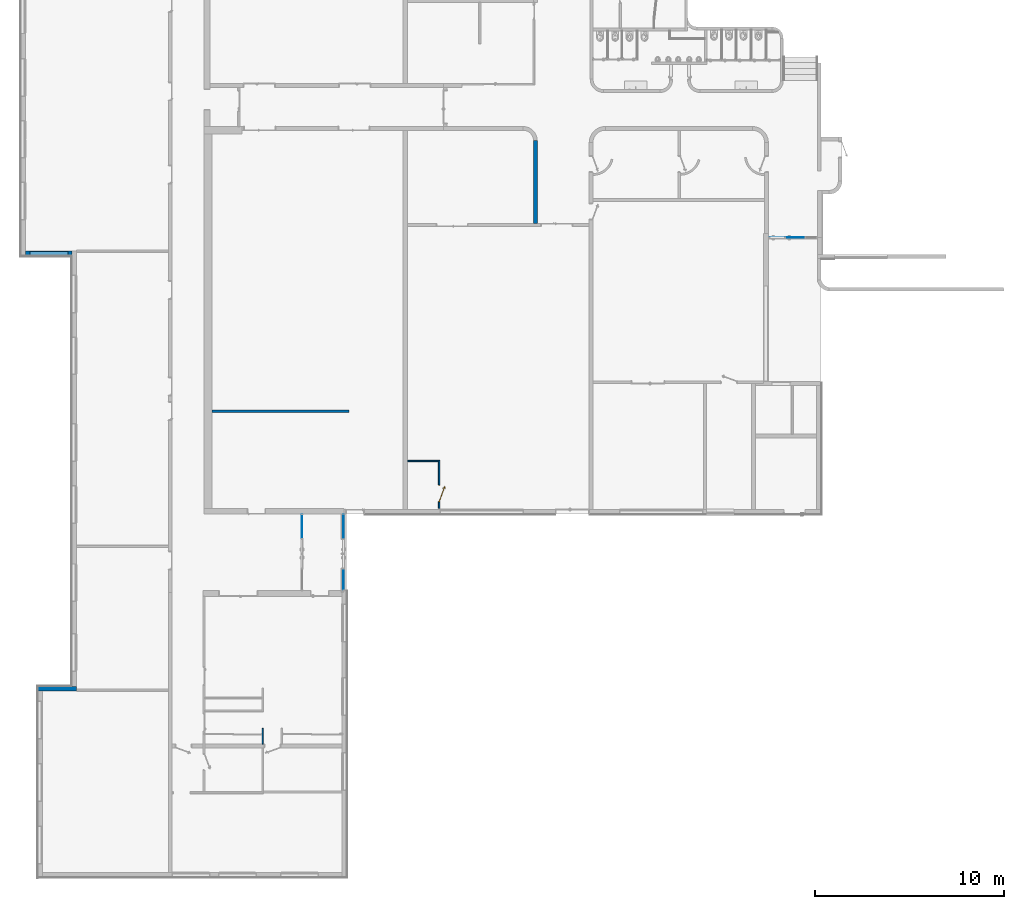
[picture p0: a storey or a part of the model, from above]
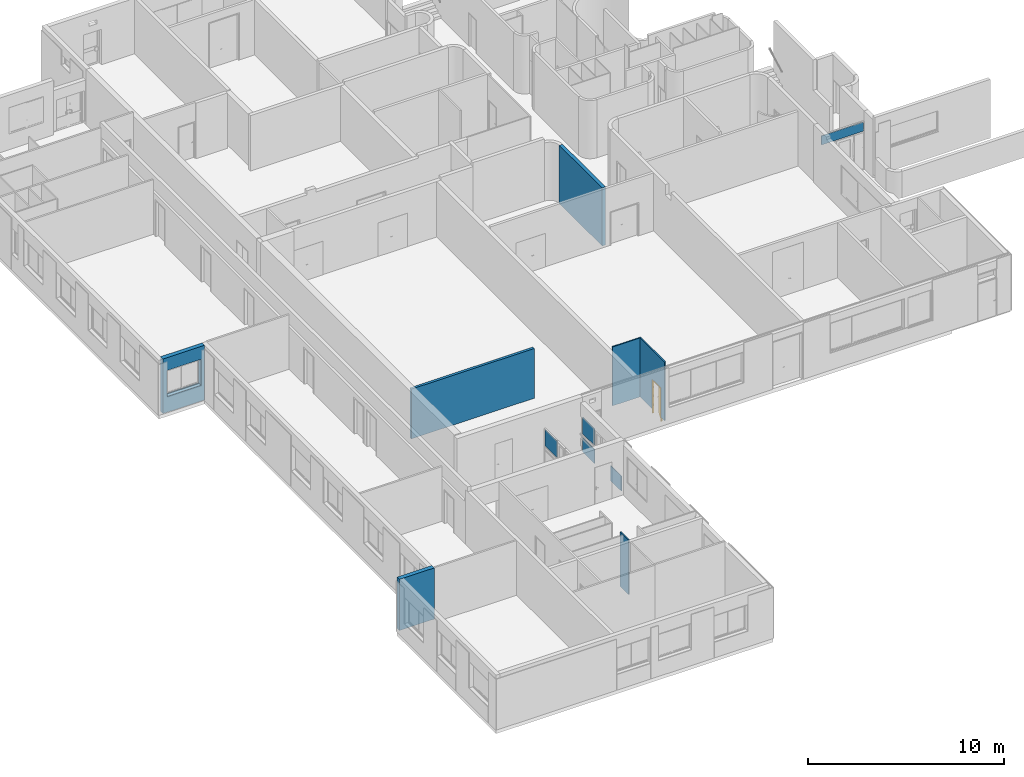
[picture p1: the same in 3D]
Properties of the parts of a building model (IFC2X3), part 1 of 4

# File
Description: ViewDefinition [CoordinationView_V2.0]
File name: 0001
Time: 2023-09-12T17:05:40
Written by: The EXPRESS Data Manager Version 5.02.0100.07 : 28 Aug 2013
Made in: 21.1.21.45 - Exporter 21.1.21.45 - Interface utilisateur alternative 21.1.21.45
Comment: STEP Physical File produced by: The EXPRESS Data Manager Version 5.02.0100.07 : 28 Aug 2013 * Module: EDMstepFileFactory/EDMstandAlone * Creation date: Tue Sep 12 17:05:40 2023 * Host: ws-vpa-259 * Database: C:\Users\ABDENO~1.BOU\AppData\Local\Temp\62183a18-c517-4f01-aa17-57c33f67edc7\9ac1ab08-a385-47ce-b0ed-35d248a44ec6\ifc * Database version: 5507 * Database creation date: Tue Sep 12 17:04:09 2023 * Schema: IFC2X3 * Model: DataRepository.ifc * Model creation date: Tue Sep 12 17:04:09 2023 * Header model: DataRepository.ifc_HeaderModel * Header model creation date: Tue Sep 12 17:04:09 2023 * EDMuser: sdai-user * EDMgroup: sdai-group * License ID and type: 5605 : Permanent license. Expiry date: * EDMstepFileFactory options: 020000

# IfcProject, 0001
LongName: SITE CEPRECO; Phase: Etat du projet

# IfcSite, Default
RefLatitude: 48, 51, 23, 999633; RefLongitude: 2, 21, 3, 553905; RefElevation: 35.0467 m

# IfcBuilding
Pset_BuildingCommon - NumberOfStoreys: 16

# IfcBuildingStorey: Niveau:Pointe 8 mm (16)
Name | LongName | Elevation (m)
SOUS SOL | SOUS SOL | -0.316692
Niveau 00 | Niveau 00 | 0
Niveau 00 - 01 | Niveau 00 - 01 | 0.253308
Niveau 00 - 02 | Niveau 00 - 02 | 0.893308
Niveau 00 - 03 | Niveau 00 - 03 | 2.31331
Niveau 1 - 03 | Niveau 1 - 03 | 3.22981
Niveau 1 - 01 | Niveau 1 - 01 | 3.95331
Niveau 1 | Niveau 1 | 4.12187
Niveau 1 - 02 | Niveau 1 - 02 | 4.31331
Niveau 1 - 03 | Niveau 1 - 03 | 5.77187
Niveau 2 | Niveau 2 | 7.36731
Niveau 3 - 02 | Niveau 3 - 02 | 9.74731
Niveau 3 - 01 | Niveau 3 - 01 | 10.1533
Niveau 3 | Niveau 3 | 10.7533
Niveau 4 | Niveau 4 | 13.0433
Niveau Toiture | Niveau Toiture | 14.9533

# IfcBeam: IPE 30:IPE300 (4)
In: Niveau 2
Type - Pset_BeamCommon - IsExternal: no; Reference: IPE300; LoadBearing: yes
Type - Pset_QuantityTakeOff - Reference: IPE300
Type - Pset_ReinforcementBarPitchOfBeam - Reference: IPE300
Material: Acier structurel - S235
Pset_BeamCommon - Slope: 0 deg
Pset_QuantityTakeOff - sets with these values: 2
Name (IPE 30:IPE300:...) | Span (m)
1296346 | 5.86
1296515 | 6.495
1296573 | 5.86
1481665 | 6.535

# IfcBeam: M_Béton-Poutre rectangulaire T2:20x60h (3)
In: Niveau 1 - 01
Type - Pset_BeamCommon - IsExternal: no; LoadBearing: yes; Reference: 20x60h
Type - Pset_QuantityTakeOff - Reference: 20x60h
Type - Pset_ReinforcementBarPitchOfBeam - Reference: 20x60h
Material: Béton, coulé sur place gris
Pset_BeamCommon - Slope: 0 deg
Pset_QuantityTakeOff - sets with these values: 2
Name (M_Béton-Poutre rectangulaire T2:20x60h:...) | Span (m)
1301493 | 29.0879
1301525 | 25.9214
1309314 | 25.9214

# IfcBeam: M_Béton-Poutre rectangulaire T2:20x65h (5)
In: Niveau 1 - 01
Type - Pset_BeamCommon - IsExternal: no; LoadBearing: yes; Reference: 20x65h
Type - Pset_QuantityTakeOff - Reference: 20x65h
Type - Pset_ReinforcementBarPitchOfBeam - Reference: 20x65h
Material: Béton, coulé sur place gris
Pset_BeamCommon - Slope: 0 deg
Pset_QuantityTakeOff - sets with these values: 2
Name (M_Béton-Poutre rectangulaire T2:20x65h:...) | Span (m)
1301378 | 29.0879
1309497 | 10.075
1309510 | 10.075
1506846 | 10.075
1506879 | 10.075

# IfcBeam: M_Béton-Poutre rectangulaire T2:30x65h, M_Béton-Poutre rectangulaire T2:30x65h:1506975
In: Niveau 1 - 01
Type - Pset_BeamCommon - IsExternal: no; LoadBearing: yes; Reference: 30x65h
Type - Pset_QuantityTakeOff - Reference: 30x65h
Type - Pset_ReinforcementBarPitchOfBeam - Reference: 30x65h
Material: Béton, coulé sur place gris
Pset_BeamCommon - Slope: 0 deg; Span: 10.075 m
Pset_QuantityTakeOff - sets with these values: 2

# IfcBeam: M_Béton-Poutre rectangulaire T2:40x90h, M_Béton-Poutre rectangulaire T2:40x90h:1398448
In: Niveau 2
Type - Pset_BeamCommon - IsExternal: no; LoadBearing: yes; Reference: 40x90h
Type - Pset_QuantityTakeOff - Reference: 40x90h
Type - Pset_ReinforcementBarPitchOfBeam - Reference: 40x90h
Material: Béton, coulé sur place gris
Pset_BeamCommon - Slope: 0 deg; Span: 9 m
Pset_QuantityTakeOff - sets with these values: 2

# IfcBeam: M_Béton-Poutre rectangulaire T2:55x65h, M_Béton-Poutre rectangulaire T2:55x65h:1502197
In: Niveau 00
Type - Pset_BeamCommon - IsExternal: no; LoadBearing: yes; Reference: 55x65h
Type - Pset_QuantityTakeOff - Reference: 55x65h
Type - Pset_ReinforcementBarPitchOfBeam - Reference: 55x65h
Material: Béton, coulé sur place gris
Pset_BeamCommon - Slope: 0 deg; Span: 29.0879 m
Pset_QuantityTakeOff - sets with these values: 2

# IfcBuildingElementProxy: Accrotère R+1:Accrotère R+1, Accrotère R+1:Accrotère R+1:1333942
In: Niveau 1 - 03
Type - Pset_BuildingElementProxyCommon - Reference: Accrotère R+1
Type - Pset_QuantityTakeOff - Reference: Accrotère R+1
Pset_BuildingElementProxyCommon - sets with these values: 2

# IfcBuildingElementProxy: BAC:BAC, BAC:BAC:1120224
In: Niveau 00 - 02
Type - Pset_BuildingElementProxyCommon - Reference: BAC
Type - Pset_QuantityTakeOff - Reference: BAC
Pset_BuildingElementProxyCommon - sets with these values: 2

# IfcBuildingElementProxy: Conduit Gaz1:Conduit Gaz, Conduit Gaz1:Conduit Gaz:1187289
In: Niveau 3
Type - Material: @_Peinture Gris Anthracite
Type - Pset_BuildingElementProxyCommon - Reference: Conduit Gaz
Type - Pset_QuantityTakeOff - Reference: Conduit Gaz
Pset_BuildingElementProxyCommon - sets with these values: 2
Pset_ProvisionForVoid - Width: 0.76389 m; Height: 0.308591 m; Depth: 0.76389 m

# IfcBuildingElementProxy: Conduit Gaz2:Conduit Gaz, Conduit Gaz2:Conduit Gaz:1188168
In: Niveau 3
Type - Material: @_Peinture Gris Anthracite
Type - Pset_BuildingElementProxyCommon - Reference: Conduit Gaz
Type - Pset_QuantityTakeOff - Reference: Conduit Gaz
Pset_BuildingElementProxyCommon - sets with these values: 2
Pset_ProvisionForVoid - Width: 0.76389 m; Height: 0.308591 m; Depth: 0.76389 m

# IfcBuildingElementProxy: Conduit Gaz3:Conduit Gaz, Conduit Gaz3:Conduit Gaz:1188640
In: Niveau 3
Type - Material: @_Peinture Gris Anthracite
Type - Pset_BuildingElementProxyCommon - Reference: Conduit Gaz
Type - Pset_QuantityTakeOff - Reference: Conduit Gaz
Pset_BuildingElementProxyCommon - sets with these values: 2

# IfcBuildingElementProxy: Conduit Gaz4:Conduit Gaz, Conduit Gaz4:Conduit Gaz:1189637
In: Niveau 3
Type - Material: @_Peinture Gris Anthracite
Type - Pset_BuildingElementProxyCommon - Reference: Conduit Gaz
Type - Pset_QuantityTakeOff - Reference: Conduit Gaz
Pset_BuildingElementProxyCommon - sets with these values: 2
Pset_ProvisionForVoid - Width: 0.506277 m; Height: 0.571712 m; Depth: 0.506277 m

# IfcBuildingElementProxy: Conduit Gaz5:Conduit Gaz, Conduit Gaz5:Conduit Gaz:1326465
In: Niveau 1 - 01
Type - Material: @_Peinture Gris Anthracite
Type - Pset_BuildingElementProxyCommon - Reference: Conduit Gaz
Type - Pset_QuantityTakeOff - Reference: Conduit Gaz
Pset_BuildingElementProxyCommon - sets with these values: 2
Pset_ProvisionForVoid - Width: 0.419194 m; Height: 0.55 m; Depth: 0.419194 m

# IfcBuildingElementProxy: Conduit Gaz6:Conduit Gaz, Conduit Gaz6:Conduit Gaz:1327238
In: Niveau 1
Type - Material: @_Peinture Gris Anthracite
Type - Pset_BuildingElementProxyCommon - Reference: Conduit Gaz
Type - Pset_QuantityTakeOff - Reference: Conduit Gaz
Pset_BuildingElementProxyCommon - sets with these values: 2
Pset_ProvisionForVoid - Width: 0.499194 m; Height: 0.55 m; Depth: 0.499194 m

# IfcBuildingElementProxy: Conduit Gaz:Conduit Gaz, Conduit Gaz:Conduit Gaz:1063076
In: Niveau 00
Type - Material: rouge
Type - Pset_BuildingElementProxyCommon - Reference: Conduit Gaz
Type - Pset_QuantityTakeOff - Reference: Conduit Gaz
Material: rouge, @_Peinture Gris Anthracite, Gaz jaune
Pset_BuildingElementProxyCommon - sets with these values: 2
Pset_ProvisionForVoid - Width: 11.1694 m; Height: 0.16 m; Depth: 11.1694 m

# IfcBuildingElementProxy: Famille 0:Famille 110x110 (3)
Type - Material: Métal - Aluminium, Verre
Type - Pset_BuildingElementProxyCommon - Reference: Famille 110x110
Type - Pset_QuantityTakeOff - Reference: Famille 110x110
Material: Verre, Métal - Aluminium
Pset_BuildingElementProxyCommon - sets with these values: 2
Name (Famille 0:Famille 110x110:...) | In
1185069 | Niveau 00 - 02
1326302 | Niveau 1 - 03
1326333 | Niveau 1 - 03

# IfcBuildingElementProxy: Famille 0:Famille 110x110 TYPE 2, Famille 0:Famille 110x110 TYPE 2:1201014
In: Niveau 00 - 02
Type - Material: Métal - Aluminium, Verre
Type - Pset_BuildingElementProxyCommon - Reference: Famille 110x110 TYPE 2
Type - Pset_QuantityTakeOff - Reference: Famille 110x110 TYPE 2
Material: Verre, Métal - Aluminium
Pset_BuildingElementProxyCommon - sets with these values: 2

# IfcBuildingElementProxy: Famille 0:Famille 120x120 (2)
In: Niveau 00 - 02
Type - Material: Métal - Aluminium, Verre
Type - Pset_BuildingElementProxyCommon - Reference: Famille 120x120
Type - Pset_QuantityTakeOff - Reference: Famille 120x120
Material: Verre, Métal - Aluminium
Pset_BuildingElementProxyCommon - sets with these values: 2
Name (Famille 0:Famille 120x120:...)
1168692
1168734

# IfcBuildingElementProxy: Famille 0:Famille 140x110, Famille 0:Famille 140x110:1310774
In: Niveau 1 - 01
Type - Material: Métal - Aluminium
Type - Pset_BuildingElementProxyCommon - Reference: Famille 140x110
Type - Pset_QuantityTakeOff - Reference: Famille 140x110
Material: Métal - Aluminium, Verre
Pset_BuildingElementProxyCommon - sets with these values: 2

# IfcBuildingElementProxy: Famille 0:Famille 140x110 (7)
Type - Material: Métal - Aluminium, Verre
Type - Pset_BuildingElementProxyCommon - Reference: Famille 140x110
Type - Pset_QuantityTakeOff - Reference: Famille 140x110
Material: Verre, Métal - Aluminium
Pset_BuildingElementProxyCommon - sets with these values: 2
Name (Famille 0:Famille 140x110:...) | In
1310134 | Niveau 1 - 03
1310135 | Niveau 1 - 03
1310775 | Niveau 1 - 01
1310776 | Niveau 1 - 01
1310777 | Niveau 1 - 01
1310778 | Niveau 1 - 01
1310779 | Niveau 1 - 01

# IfcBuildingElementProxy: Famille 0:Famille 150x120 (14)
Type - Material: Métal - Aluminium, Verre
Type - Pset_BuildingElementProxyCommon - Reference: Famille 150x120
Type - Pset_QuantityTakeOff - Reference: Famille 150x120
Material: Verre, Métal - Aluminium
Pset_BuildingElementProxyCommon - sets with these values: 2
Name (Famille 0:Famille 150x120:...) | In
1163506 | Niveau 00 - 02
1298098 | Niveau 00 - 02
1310329 | Niveau 1 - 01
1310574 | Niveau 1 - 01
1310575 | Niveau 1 - 01
1310576 | Niveau 1 - 01
1310577 | Niveau 1 - 01
1310578 | Niveau 1 - 01
1310588 | Niveau 1 - 01
1310761 | Niveau 1 - 01
1310762 | Niveau 1 - 01
1310763 | Niveau 1 - 01
1310764 | Niveau 1 - 01
1310765 | Niveau 1 - 01

# IfcBuildingElementProxy: Famille 0:Famille 85x55, Famille 0:Famille 85x55:1194350
In: Niveau 00 - 02
Type - Material: Métal - Aluminium, Verre
Type - Pset_BuildingElementProxyCommon - Reference: Famille 85x55
Type - Pset_QuantityTakeOff - Reference: Famille 85x55
Material: Verre, Métal - Aluminium
Pset_BuildingElementProxyCommon - sets with these values: 2

# IfcBuildingElementProxy: GAZ:#01, GAZ:#01:1062761
In: Niveau 00
Type - Material: rouge
Type - Pset_BuildingElementProxyCommon - Reference: #01
Type - Pset_QuantityTakeOff - Reference: #01
Pset_BuildingElementProxyCommon - sets with these values: 2

# IfcBuildingElementProxy: Grille d'aération - Mur:1000 x 820 mm, Grille d'aération - Mur:1000 x 820 mm:1200349
In: Niveau 3 - 02
Type - Material: Acier - Galvanisé (2)
Type - Pset_BuildingElementProxyCommon - Reference: 1000 x 820 mm
Type - Pset_QuantityTakeOff - Reference: 1000 x 820 mm
Material: Acier - Galvanisé
Pset_OpeningElementCommon - Reference: 1000 x 820 mm; sets with these values: 2

# IfcBuildingElementProxy: Grille d'aération - Mur:Type A (6)
Type - Material: Acier - Galvanisé (2)
Type - Pset_BuildingElementProxyCommon - Reference: Type A
Type - Pset_QuantityTakeOff - Reference: Type A
Material: Acier - Galvanisé
Name (Grille d'aération - Mur:Type A:...) | In | Reference | Pset_OpeningElementCommon, sets with these values
1138769 | Niveau 3 - 02 | Pset_BuildingElementProxyCommon - sets with these values: 2
1138918 | Niveau 3 - 02 | Type A | 2
1367621 | Niveau 00 | Type A | 2
1383589 | Niveau 00 - 03 | Type A | 2
1393028 | Niveau 00 - 03 | Type A | 2
1419079 | Niveau 00 - 03 | Type A | 2

# IfcBuildingElementProxy: Grille sol:Famille 2, Grille sol:Famille 2:1334444
In: Niveau 00 - 02
Type - Material: surface caillebotis
Type - Pset_BuildingElementProxyCommon - Reference: Famille 2
Type - Pset_QuantityTakeOff - Reference: Famille 2
Pset_BuildingElementProxyCommon - sets with these values: 2
Pset_ProvisionForVoid - Width: 0.025 m; Height: 0.4 m; Depth: 0.025 m

# IfcBuildingElementProxy: Grille sol:Famille1 (2)
In: Niveau 00 - 03
Type - Material: surface caillebotis
Type - Pset_BuildingElementProxyCommon - Reference: Famille1
Type - Pset_QuantityTakeOff - Reference: Famille1
Pset_BuildingElementProxyCommon - sets with these values: 2
Name (Grille sol:Famille1:...)
1186852 | Pset_ProvisionForVoid - Width: 0.025 m; Height: 1.25 m; Depth: 0.025 m
1186888

# IfcBuildingElementProxy: Modèles génériques 1:Modèles génériques 1, Modèles génériques 1:Modèles génériques 1:1211554
In: Niveau 3 - 01
Type - Pset_BuildingElementProxyCommon - Reference: Modèles génériques 1
Type - Pset_QuantityTakeOff - Reference: Modèles génériques 1
Pset_BuildingElementProxyCommon - sets with these values: 2
Pset_ProvisionForVoid - Width: 0.045 m; Height: 1.26264 m; Depth: 0.045 m

# IfcBuildingElementProxy: Modèles génériques 2:Modèles génériques 2, Modèles génériques 2:Modèles génériques 2:1303948
In: Niveau 00 - 03
Type - Pset_BuildingElementProxyCommon - Reference: Modèles génériques 2
Type - Pset_QuantityTakeOff - Reference: Modèles génériques 2
Pset_BuildingElementProxyCommon - sets with these values: 2
Pset_ProvisionForVoid - Width: 0.843308 m; Height: 1.215 m; Depth: 0.843308 m

# IfcBuildingElementProxy: Modèles génériques 3:Modèles génériques 3, Modèles génériques 3:Modèles génériques 3:1354350
In: Niveau 00 - 02
Type - Material: Maçonnerie - Voile BA rouge Brique
Type - Pset_BuildingElementProxyCommon - Reference: Modèles génériques 3
Type - Pset_QuantityTakeOff - Reference: Modèles génériques 3
Pset_BuildingElementProxyCommon - sets with these values: 2

# IfcBuildingElementProxy: Modèles génériques 4:Modèles génériques 4, Modèles génériques 4:Modèles génériques 4:1358634
In: Niveau 00 - 02
Type - Pset_BuildingElementProxyCommon - Reference: Modèles génériques 4
Type - Pset_QuantityTakeOff - Reference: Modèles génériques 4
Pset_BuildingElementProxyCommon - sets with these values: 2
Pset_ProvisionForVoid - Width: 0.89611 m; Height: 1.20011 m; Depth: 0.89611 m

# IfcBuildingElementProxy: Modèles génériques 5:Modèles génériques 5, Modèles génériques 5:Modèles génériques 5:1377466
In: Niveau 00 - 02
Type - Pset_BuildingElementProxyCommon - Reference: Modèles génériques 5
Type - Pset_QuantityTakeOff - Reference: Modèles génériques 5
Pset_BuildingElementProxyCommon - sets with these values: 2
Pset_ProvisionForVoid - Width: 0.160138 m; Height: 1.22 m; Depth: 0.160138 m

# IfcBuildingElementProxy: Modèles génériques 6:Modèles génériques 6, Modèles génériques 6:Modèles génériques 6:1497768
In: Niveau 00 - 02
Type - Pset_BuildingElementProxyCommon - Reference: Modèles génériques 6
Type - Pset_QuantityTakeOff - Reference: Modèles génériques 6
Pset_BuildingElementProxyCommon - sets with these values: 2
Pset_ProvisionForVoid - Width: 1.25 m; Height: 0.08 m; Depth: 1.25 m

# IfcBuildingElementProxy: Plan de travail:Plan de travail, Plan de travail:Plan de travail:1292339
In: Niveau 1
Type - Pset_BuildingElementProxyCommon - Reference: Plan de travail
Type - Pset_QuantityTakeOff - Reference: Plan de travail
Pset_BuildingElementProxyCommon - sets with these values: 2
Pset_ProvisionForVoid - Width: 0.874358 m; Height: 3.3175 m; Depth: 0.874358 m

# IfcBuildingElementProxy: Skydome 1:Skydome 110x120, Skydome 1:Skydome 110x120:1168822
In: Niveau 00 - 02
Type - Material: Verre, Métal - Bronze, Léger brossage
Type - Pset_BuildingElementProxyCommon - Reference: Skydome 110x120
Type - Pset_QuantityTakeOff - Reference: Skydome 110x120
Material: Métal - Bronze, Léger brossage, Verre
Pset_BuildingElementProxyCommon - sets with these values: 2

# IfcBuildingElementProxy: Skydome 3:Skydome 3, Skydome 3:Skydome 3:1171397
In: Niveau 00 - 02
Type - Material: Métal - Bronze, Léger brossage, Verre
Type - Pset_BuildingElementProxyCommon - Reference: Skydome 3
Type - Pset_QuantityTakeOff - Reference: Skydome 3
Material: Métal - Bronze, Léger brossage
Pset_BuildingElementProxyCommon - sets with these values: 2

# IfcBuildingElementProxy: Skydome 4:Skydome 110x110, Skydome 4:Skydome 110x110:1185118
In: Niveau 00 - 02
Type - Material: Métal - Bronze, Léger brossage, Verre
Type - Pset_BuildingElementProxyCommon - Reference: Skydome 110x110
Type - Pset_QuantityTakeOff - Reference: Skydome 110x110
Material: Verre
Pset_BuildingElementProxyCommon - sets with these values: 2

# IfcBuildingElementProxy: Skydome 4:Skydome 110x120, Skydome 4:Skydome 110x120:1178745
In: Niveau Toiture
Type - Material: Verre, Métal - Bronze, Léger brossage
Type - Pset_BuildingElementProxyCommon - Reference: Skydome 110x120
Type - Pset_QuantityTakeOff - Reference: Skydome 110x120
Material: Verre
Pset_BuildingElementProxyCommon - sets with these values: 2

# IfcBuildingElementProxy: Skydome 4:Skydome 110x120 (2)
In: Niveau 00 - 02
Type - Material: Verre, Métal - Bronze, Léger brossage, LIGNES
Type - Pset_BuildingElementProxyCommon - Reference: Skydome 110x120
Type - Pset_QuantityTakeOff - Reference: Skydome 110x120
Material: LIGNES, Verre
Pset_BuildingElementProxyCommon - sets with these values: 2
Name (Skydome 4:Skydome 110x120:...)
1184977
1185008

# IfcBuildingElementProxy: Tube de toiture1:Tube de toiture, Tube de toiture1:Tube de toiture:1176083
In: Niveau 1 - 03
Type - Material: @_Peinture Gris Anthracite
Type - Pset_BuildingElementProxyCommon - Reference: Tube de toiture
Type - Pset_QuantityTakeOff - Reference: Tube de toiture
Pset_BuildingElementProxyCommon - sets with these values: 2

# IfcBuildingElementProxy: Tube de toiture2:Tube de toiture, Tube de toiture2:Tube de toiture:1191322
In: Niveau 3
Type - Material: @_Peinture Gris Anthracite
Type - Pset_BuildingElementProxyCommon - Reference: Tube de toiture
Type - Pset_QuantityTakeOff - Reference: Tube de toiture
Pset_BuildingElementProxyCommon - sets with these values: 2

# IfcBuildingElementProxy: Tube de toiture3:Tube de toiture, Tube de toiture3:Tube de toiture:1312801
In: Niveau 1
Type - Material: @_Peinture Gris Anthracite
Type - Pset_BuildingElementProxyCommon - Reference: Tube de toiture
Type - Pset_QuantityTakeOff - Reference: Tube de toiture
Pset_BuildingElementProxyCommon - sets with these values: 2

# IfcBuildingElementProxy: Tube de toiture:Tube de toiture, Tube de toiture:Tube de toiture:1136618
In: Niveau 4
Type - Material: @_Peinture Gris Anthracite
Type - Pset_BuildingElementProxyCommon - Reference: Tube de toiture
Type - Pset_QuantityTakeOff - Reference: Tube de toiture
Pset_BuildingElementProxyCommon - sets with these values: 2

# IfcBuildingElementProxy: accortère1:accortère, accortère1:accortère:1152871
In: Niveau 3
Type - Pset_BuildingElementProxyCommon - Reference: accortère
Type - Pset_QuantityTakeOff - Reference: accortère
Pset_BuildingElementProxyCommon - sets with these values: 2

# IfcBuildingElementProxy: accortère2:accortère, accortère2:accortère:1436307
In: Niveau 1 - 03
Type - Pset_BuildingElementProxyCommon - Reference: accortère
Type - Pset_QuantityTakeOff - Reference: accortère
Pset_BuildingElementProxyCommon - sets with these values: 2

# IfcBuildingElementProxy: accortère3:accortère, accortère3:accortère:1436549
In: Niveau 1 - 03
Type - Pset_BuildingElementProxyCommon - Reference: accortère
Type - Pset_QuantityTakeOff - Reference: accortère
Pset_BuildingElementProxyCommon - sets with these values: 2

# IfcBuildingElementProxy: accortère4:accortère, accortère4:accortère:1436791
In: Niveau 00 - 03
Type - Pset_BuildingElementProxyCommon - Reference: accortère
Type - Pset_QuantityTakeOff - Reference: accortère
Pset_BuildingElementProxyCommon - sets with these values: 2

# IfcBuildingElementProxy: accortère5:accortère, accortère5:accortère:1437154
In: Niveau 3 - 02
Type - Pset_BuildingElementProxyCommon - Reference: accortère
Type - Pset_QuantityTakeOff - Reference: accortère
Pset_BuildingElementProxyCommon - sets with these values: 2

# IfcBuildingElementProxy: accortère6:accortère, accortère6:accortère:1437329
In: Niveau 00 - 03
Type - Pset_BuildingElementProxyCommon - Reference: accortère
Type - Pset_QuantityTakeOff - Reference: accortère
Pset_BuildingElementProxyCommon - sets with these values: 2

# IfcBuildingElementProxy: accortère:accortère, accortère:accortère:980411
In: Niveau 4
Type - Pset_BuildingElementProxyCommon - Reference: accortère
Type - Pset_QuantityTakeOff - Reference: accortère
Pset_BuildingElementProxyCommon - sets with these values: 2

# IfcCovering: Plafond composé:Normal (20)
Type - PredefinedType: CEILING
Type - Pset_CoveringCommon - Reference: Normal; TotalThickness: 0.05 m
Type - Pset_QuantityTakeOff - Reference: Normal
Material: Montant métallique 0.04 m, Faux-plafond - Trame 600 x 600 -90 0.01 m
Pset_CoveringCommon - Finish: Faux-plafond - Trame 600 x 600 -90;
Name (Plafond composé:Normal:...) | In
1043636 | Niveau 00 - 03
1047342 | Niveau 00 - 03
1047447 | Niveau 00
1047878 | Niveau 00
1124583 | Niveau 3
1255899 | Niveau 1
1302928 | Niveau 00
1314552 | Niveau 00
1315372 | Niveau 00
1335122 | Niveau 00
1398915 | Niveau 00
1403133 | Niveau 00
1407076 | Niveau 00
1500427 | Niveau 00
1501346 | Niveau 00
1501489 | Niveau 00
1501652 | SOUS SOL
1502257 | Niveau 00
1504277 | SOUS SOL
1508162 | Niveau 00

# IfcCovering: Plafond composé:Normal FP Bleu, Plafond composé:Normal FP Bleu:1109035
In: Niveau 00
Type - PredefinedType: CEILING
Type - Pset_CoveringCommon - Reference: Normal FP Bleu; TotalThickness: 0.03 m
Type - Pset_QuantityTakeOff - Reference: Normal FP Bleu
Material: FP - Peinture Grise 0.02 m, FP - Peinture bleu 0.01 m
Pset_CoveringCommon - Finish: FP - Peinture bleu;

# IfcCovering: Plafond composé:Normal FP bois, Plafond composé:Normal FP bois:1043869
In: Niveau 00 - 03
Type - PredefinedType: CEILING
Type - Pset_CoveringCommon - Reference: Normal FP bois; TotalThickness: 0.05 m
Type - Pset_QuantityTakeOff - Reference: Normal FP bois
Material: Montant métallique 0.04 m, Faux-plafond - bande bois 0.01 m
Pset_CoveringCommon - Finish: Faux-plafond - bande bois;

# IfcCurtainWall: Mur-rideau:SANS Calpinage (5)
Type - Pset_CurtainWallCommon - IsExternal: no; Reference: SANS Calpinage
Type - Pset_QuantityTakeOff - Reference: SANS Calpinage
Name (Mur-rideau:SANS Calpinage:...) | In
1121815 | Niveau 00 - 02
1361501 | Niveau 00 - 02 | Pset_OpeningElementCommon - Reference: SANS Calpinage; sets with these values: 2
1368376 | Niveau 00 - 01
1374202 | Niveau 00 - 01 | Pset_OpeningElementCommon - Reference: SANS Calpinage; sets with these values: 2
1528180 | Niveau 00 - 01

# IfcDistributionPort (2)
Description: Flow; FlowDirection: SINK
Name
Port_1289371
Port_1294219

# IfcDoor: @_Int. Simple:@_PP (0.63m x 2.04m) (3)
In: Niveau 00 - 01
Type - ParameterTakesPrecedence: no; Sizeable: no; Material: @_Finition Peinture - Blanc satiné, RAL1013-Blanc perle (3)
Type - Pset_DoorCommon - IsExternal: no; Reference: @_PP (0.63m x 2.04m)
Type - Pset_QuantityTakeOff - Reference: @_PP (0.63m x 2.04m)
OverallHeight: 2.075 m; OverallWidth: 0.7 m; Material: @_Finition Peinture - Blanc satiné, RAL1013-Blanc perle
Name (@_Int. Simple:@_PP (0.63m x 2.04m):...)
1404769
1404851
1404919

# IfcDoor: @_Int. Simple:@_PP (0.63m x 2.04m) (25)
Type - ParameterTakesPrecedence: no; Sizeable: no; Material: RAL1013-Blanc perle (3), @_Finition Peinture - Blanc satiné
Type - Pset_DoorCommon - IsExternal: no; Reference: @_PP (0.63m x 2.04m)
Type - Pset_QuantityTakeOff - Reference: @_PP (0.63m x 2.04m)
OverallHeight: 2.075 m; OverallWidth: 0.7 m; Material: @_Finition Peinture - Blanc satiné, RAL1013-Blanc perle
Name (@_Int. Simple:@_PP (0.63m x 2.04m):...) | In
1282573 | Niveau 1
1282698 | Niveau 1
1282734 | Niveau 1
1293008 | Niveau 2 | Pset_OpeningElementCommon - Reference: @_PP (0.63m x 2.04m); sets with these values: 2
1293082 | Niveau 2
1293188 | Niveau 2
1293949 | Niveau 1
1294012 | Niveau 1
1294067 | Niveau 1
1294088 | Niveau 1
1294376 | Niveau 2
1294378 | Niveau 2
1294380 | Niveau 2
1294382 | Niveau 2
1350456 | Niveau 00 - 02
1404965 | Niveau 00 - 01
1405068 | Niveau 00 - 01
1405116 | Niveau 00 - 01
1405150 | Niveau 00 - 01
1405199 | Niveau 00 - 01
1412120 | Niveau 00 - 01 | Pset_OpeningElementCommon - Reference: @_PP (0.63m x 2.04m); sets with these values: 2
1412158 | Niveau 00 - 01
1412204 | Niveau 00 - 01 | Pset_OpeningElementCommon - Reference: @_PP (0.63m x 2.04m); sets with these values: 2
1415135 | Niveau 00 - 01
1415207 | Niveau 00 - 01

# IfcDoor: @_Int. Simple:@_PP (0.73m x 2.04m) (14)
Type - ParameterTakesPrecedence: no; Sizeable: no; Material: @_Finition Peinture - Blanc satiné, RAL1013-Blanc perle (3)
Type - Pset_DoorCommon - IsExternal: no; Reference: @_PP (0.73m x 2.04m)
Type - Pset_QuantityTakeOff - Reference: @_PP (0.73m x 2.04m)
OverallHeight: 2.075 m; OverallWidth: 0.8 m; Material: @_Finition Peinture - Blanc satiné, RAL1013-Blanc perle
Name (@_Int. Simple:@_PP (0.73m x 2.04m):...) | In
1269008 | Niveau 1
1272663 | Niveau 1
1272706 | Niveau 1
1274033 | Niveau 1 | Pset_OpeningElementCommon - Reference: @_PP (0.73m x 2.04m); sets with these values: 2
1285083 | Niveau 1
1350262 | Niveau 00 - 02
1350312 | Niveau 00 - 02
1350398 | Niveau 00 - 02
1350508 | Niveau 00 - 02
1350536 | Niveau 00 - 02
1401739 | Niveau 00 - 01 | Pset_OpeningElementCommon - Reference: @_PP (0.73m x 2.04m); sets with these values: 2
1407251 | Niveau 00 - 01
1407285 | Niveau 00 - 01
1418454 | Niveau 00 - 02

# IfcDoor: @_Int. Simple:@_PP (0.73m x 2.04m) (13)
Type - ParameterTakesPrecedence: no; Sizeable: no; Material: RAL1013-Blanc perle (3), @_Finition Peinture - Blanc satiné
Type - Pset_DoorCommon - IsExternal: no; Reference: @_PP (0.73m x 2.04m)
Type - Pset_QuantityTakeOff - Reference: @_PP (0.73m x 2.04m)
OverallHeight: 2.075 m; OverallWidth: 0.8 m; Material: @_Finition Peinture - Blanc satiné, RAL1013-Blanc perle
Name (@_Int. Simple:@_PP (0.73m x 2.04m):...) | In
1095932 | SOUS SOL
1265753 | Niveau 1
1268579 | Niveau 1
1268599 | Niveau 1
1272618 | Niveau 1
1273967 | Niveau 1 | Pset_OpeningElementCommon - Reference: @_PP (0.73m x 2.04m); sets with these values: 2
1350556 | Niveau 00 - 02
1358109 | Niveau 00 - 02
1401716 | Niveau 00 - 01 | Pset_OpeningElementCommon - Reference: @_PP (0.73m x 2.04m); sets with these values: 2
1406095 | Niveau 00 - 01 | Pset_OpeningElementCommon - Reference: @_PP (0.73m x 2.04m); sets with these values: 2
1406932 | Niveau 00 - 01
1407017 | Niveau 00 - 01
1447539 | Niveau 1

# IfcDoor: @_Int. Simple:@_PP (0.83m x 2.04m) (4)
Type - ParameterTakesPrecedence: no; Sizeable: no; Material: @_Finition Peinture - Blanc satiné, RAL1013-Blanc perle (3)
Type - Pset_DoorCommon - IsExternal: no; Reference: @_PP (0.83m x 2.04m)
Type - Pset_QuantityTakeOff - Reference: @_PP (0.83m x 2.04m)
OverallHeight: 2.075 m; OverallWidth: 0.9 m; Material: @_Finition Peinture - Blanc satiné, RAL1013-Blanc perle
Name (@_Int. Simple:@_PP (0.83m x 2.04m):...) | In
1272736 | Niveau 1
1290945 | Niveau 1 | Pset_OpeningElementCommon - Reference: @_PP (0.83m x 2.04m); sets with these values: 2
1400419 | Niveau 00 - 02 | Pset_OpeningElementCommon - Reference: @_PP (0.83m x 2.04m); sets with these values: 2
1499070 | Niveau 00

# IfcDoor: @_Int. Simple:@_PP (0.83m x 2.04m) (19)
Type - ParameterTakesPrecedence: no; Sizeable: no; Material: RAL1013-Blanc perle (3), @_Finition Peinture - Blanc satiné
Type - Pset_DoorCommon - IsExternal: no; Reference: @_PP (0.83m x 2.04m)
Type - Pset_QuantityTakeOff - Reference: @_PP (0.83m x 2.04m)
OverallHeight: 2.075 m; OverallWidth: 0.9 m; Material: @_Finition Peinture - Blanc satiné, RAL1013-Blanc perle
Name (@_Int. Simple:@_PP (0.83m x 2.04m):...) | In
1225907 | Niveau 2 | Pset_OpeningElementCommon - Reference: @_PP (0.83m x 2.04m); sets with these values: 2
1225978 | Niveau 2
1228291 | Niveau 2
1272451 | Niveau 1
1273015 | Niveau 1
1292449 | Niveau 2
1397800 | Niveau 00 - 02
1401519 | Niveau 00 - 01
1406522 | Niveau 00 - 01
1408859 | Niveau 00 - 01
1409023 | Niveau 00 - 01
1410527 | Niveau 00 - 01
1411509 | Niveau 00 - 01
1414568 | Niveau 00 - 01
1414616 | Niveau 00 - 01
1487658 | Niveau 00
1518072 | Niveau 2
1522945 | Niveau 00
1535016 | Niveau 2

# IfcDoor: @_Int. Simple:@_PP (0.93m x 2.04m), @_Int. Simple:@_PP (0.93m x 2.04m):1490559
In: Niveau 00 - 02
Type - ParameterTakesPrecedence: no; Sizeable: no; Material: @_Finition Peinture - Blanc satiné, RAL1013-Blanc perle (3)
Type - Pset_DoorCommon - IsExternal: no; Reference: @_PP (0.93m x 2.04m)
Type - Pset_QuantityTakeOff - Reference: @_PP (0.93m x 2.04m)
OverallHeight: 2.075 m; OverallWidth: 1 m; Material: @_Finition Peinture - Blanc satiné, RAL1013-Blanc perle

# IfcDoor: @_Int. Simple:@_PP (0.93m x 2.04m) (11)
Type - ParameterTakesPrecedence: no; Sizeable: no; Material: RAL1013-Blanc perle (3), @_Finition Peinture - Blanc satiné
Type - Pset_DoorCommon - IsExternal: no; Reference: @_PP (0.93m x 2.04m)
Type - Pset_QuantityTakeOff - Reference: @_PP (0.93m x 2.04m)
OverallHeight: 2.075 m; OverallWidth: 1 m; Material: @_Finition Peinture - Blanc satiné, RAL1013-Blanc perle
Name (@_Int. Simple:@_PP (0.93m x 2.04m):...) | In
1100691 | SOUS SOL
1100895 | SOUS SOL
1211804 | Niveau 3 - 01
1232404 | Niveau 2
1265986 | Niveau 1 | Pset_OpeningElementCommon - Reference: @_PP (0.93m x 2.04m); sets with these values: 2
1266033 | Niveau 1
1272880 | Niveau 1
1291137 | Niveau 1
1291917 | Niveau 1
1400321 | Niveau 00 - 02
1410215 | Niveau 00 - 01

# IfcDoor: @_Int. Simple:@_PP (0.93m x 2.25), @_Int. Simple:@_PP (0.93m x 2.25):1415418
In: Niveau 00 - 01
Type - ParameterTakesPrecedence: no; Sizeable: no; Material: @_Finition Peinture - Blanc satiné, RAL1013-Blanc perle (3)
Type - Pset_DoorCommon - IsExternal: no; Reference: @_PP (0.93m x 2.25)
Type - Pset_QuantityTakeOff - Reference: @_PP (0.93m x 2.25)
OverallHeight: 2.265 m; OverallWidth: 1 m; Material: @_Finition Peinture - Blanc satiné, RAL1013-Blanc perle

# IfcDoor: @_Int. Simple:@_PP (0.93m x 2.25) (13)
In: Niveau 00 - 01
Type - ParameterTakesPrecedence: no; Sizeable: no; Material: RAL1013-Blanc perle (3), @_Finition Peinture - Blanc satiné
Type - Pset_DoorCommon - IsExternal: no; Reference: @_PP (0.93m x 2.25)
Type - Pset_QuantityTakeOff - Reference: @_PP (0.93m x 2.25)
OverallHeight: 2.265 m; OverallWidth: 1 m; Material: @_Finition Peinture - Blanc satiné, RAL1013-Blanc perle
Name (@_Int. Simple:@_PP (0.93m x 2.25):...)
1373748
1409657
1409742
1409800
1409892
1409947
1410001
1410127
1410189
1411536
1411562
1411926
1416117

# IfcDoor: @_Int. Simple:@_PP (1.03m x 1.8m), @_Int. Simple:@_PP (1.03m x 1.8m):1408319
In: Niveau 00 - 01
Type - ParameterTakesPrecedence: no; Sizeable: no; Material: RAL1013-Blanc perle (3), @_Finition Peinture - Blanc satiné
Type - Pset_DoorCommon - IsExternal: no; Reference: @_PP (1.03m x 1.8m)
Type - Pset_QuantityTakeOff - Reference: @_PP (1.03m x 1.8m)
OverallHeight: 1.835 m; OverallWidth: 1.1 m; Material: @_Finition Peinture - Blanc satiné, RAL1013-Blanc perle

# IfcDoor: @_Int. Simple:@_PP (1.03m x 2.30m), @_Int. Simple:@_PP (1.03m x 2.30m):1419078
In: Niveau 00 - 01
Type - ParameterTakesPrecedence: no; Sizeable: no; Material: RAL1013-Blanc perle (3), @_Finition Peinture - Blanc satiné
Type - Pset_DoorCommon - IsExternal: no; Reference: @_PP (1.03m x 2.30m)
Type - Pset_QuantityTakeOff - Reference: @_PP (1.03m x 2.30m)
OverallHeight: 2.335 m; OverallWidth: 1.1 m; Material: @_Finition Peinture - Blanc satiné, RAL1013-Blanc perle
Pset_OpeningElementCommon - Reference: @_PP (1.03m x 2.30m); sets with these values: 2

# IfcDoor: Double (R):1.23m x 2.04m, Double (R):1.23m x 2.04m:1094404
In: SOUS SOL
Type - OperationType: DOUBLE_DOOR_SINGLE_SWING; ParameterTakesPrecedence: no; Sizeable: no; Material: Porte - Panneau, Porte - Poignée, Porte - Cadre
Type - Double (R):1.23m x 2.04m:1094404 - PanelOperation: SWINGING
Type - Pset_DoorCommon - IsExternal: no; Reference: 1.23m x 2.04m; ThermalTransmittance: 3.7021 kg/K/s3
Type - Pset_QuantityTakeOff - Reference: 1.23m x 2.04m
OverallHeight: 2.075 m; OverallWidth: 1.3 m; Material: Porte - Poignée, Porte - Cadre, Porte - Panneau

# IfcDoor: Double (R):1.23m x 2.04m (2)
Type - OperationType: DOUBLE_DOOR_SINGLE_SWING; ParameterTakesPrecedence: no; Sizeable: no; Material: Porte - Poignée, Porte - Panneau, Porte - Cadre
Type - Double (R):1.23m x 2.04m:1094072 - PanelOperation: SWINGING
Type - Pset_DoorCommon - IsExternal: no; Reference: 1.23m x 2.04m; ThermalTransmittance: 3.7021 kg/K/s3
Type - Pset_QuantityTakeOff - Reference: 1.23m x 2.04m
OverallHeight: 2.075 m; OverallWidth: 1.3 m; Material: Porte - Poignée, Porte - Cadre, Porte - Panneau
Name (Double (R):1.23m x 2.04m:...) | In
1094072 | Niveau 00 - 02
1406318 | Niveau 00 - 01

# IfcDoor: Double (R):1.43m x 2.04m, Double (R):1.43m x 2.04m:1397711
In: Niveau 00 - 02
Type - OperationType: DOUBLE_DOOR_SINGLE_SWING; ParameterTakesPrecedence: no; Sizeable: no; Material: Porte - Cadre, Porte - Poignée, Porte - Panneau
Type - Double (R):1.43m x 2.04m:1397711 - PanelOperation: SWINGING
Type - Pset_DoorCommon - IsExternal: no; Reference: 1.43m x 2.04m; ThermalTransmittance: 3.7021 kg/K/s3
Type - Pset_QuantityTakeOff - Reference: 1.43m x 2.04m
OverallHeight: 2.075 m; OverallWidth: 1.5 m; Material: Porte - Poignée, Porte - Cadre, Porte - Panneau
Pset_OpeningElementCommon - Reference: 1.43m x 2.04m; sets with these values: 2

# IfcDoor: Double (R):1.43m x 2.04m (2)
In: Niveau 1
Type - OperationType: DOUBLE_DOOR_SINGLE_SWING; ParameterTakesPrecedence: no; Sizeable: no; Material: Porte - Panneau, Porte - Cadre, Porte - Poignée
Type - Double (R):1.43m x 2.04m:1269104 - PanelOperation: SWINGING
Type - Pset_DoorCommon - IsExternal: no; Reference: 1.43m x 2.04m; ThermalTransmittance: 3.7021 kg/K/s3
Type - Pset_QuantityTakeOff - Reference: 1.43m x 2.04m
OverallHeight: 2.075 m; OverallWidth: 1.5 m; Material: Porte - Poignée, Porte - Cadre, Porte - Panneau
Pset_OpeningElementCommon - Reference: 1.43m x 2.04m; sets with these values: 2
Name (Double (R):1.43m x 2.04m:...)
1269104
1269138

# IfcDoor: Double (R):1.43m x 2.04m (3)
Type - OperationType: DOUBLE_DOOR_SINGLE_SWING; ParameterTakesPrecedence: no; Sizeable: no; Material: Porte - Poignée, Porte - Panneau, Porte - Cadre
Type - Double (R):1.43m x 2.04m:1231099 - PanelOperation: SWINGING
Type - Pset_DoorCommon - IsExternal: no; Reference: 1.43m x 2.04m; ThermalTransmittance: 3.7021 kg/K/s3
Type - Pset_QuantityTakeOff - Reference: 1.43m x 2.04m
OverallHeight: 2.075 m; OverallWidth: 1.5 m; Material: Porte - Poignée, Porte - Cadre, Porte - Panneau
Name (Double (R):1.43m x 2.04m:...) | In
1231099 | Niveau 2
1231157 | Niveau 2
1409179 | Niveau 00 - 01

# IfcDoor: Double (R):1.43m x 2.04m, Double (R):1.43m x 2.04m:1265112
In: Niveau 1
Type - OperationType: DOUBLE_DOOR_SINGLE_SWING; ParameterTakesPrecedence: no; Sizeable: no; Material: Porte - Poignée, Porte - Panneau, Porte - Cadre
Type - Double (R):1.43m x 2.04m:1265112 - PanelOperation: SWINGING
Type - Pset_DoorCommon - IsExternal: no; Reference: 1.43m x 2.04m; ThermalTransmittance: 3.7021 kg/K/s3
Type - Pset_QuantityTakeOff - Reference: 1.43m x 2.04m
OverallHeight: 2.075 m; OverallWidth: 1.5 m; Material: Porte - Poignée, Porte - Cadre, Porte - Panneau

# IfcDoor: Double (R):1.63m x 2.04m, Double (R):1.63m x 2.04m:1397896
In: Niveau 00 - 02
Type - OperationType: DOUBLE_DOOR_SINGLE_SWING; ParameterTakesPrecedence: no; Sizeable: no; Material: Porte - Cadre, Porte - Panneau, Porte - Poignée
Type - Double (R):1.63m x 2.04m:1397896 - PanelOperation: SWINGING
Type - Pset_DoorCommon - IsExternal: no; Reference: 1.63m x 2.04m; ThermalTransmittance: 3.7021 kg/K/s3
Type - Pset_QuantityTakeOff - Reference: 1.63m x 2.04m
OverallHeight: 2.075 m; OverallWidth: 1.7 m; Material: Porte - Poignée, Porte - Cadre, Porte - Panneau

# IfcDoor: Double (R):1.63m x 2.04m (3)
Type - OperationType: DOUBLE_DOOR_SINGLE_SWING; ParameterTakesPrecedence: no; Sizeable: no; Material: Porte - Cadre, Porte - Panneau, Porte - Poignée
Type - Double (R):1.63m x 2.04m:1398069 - PanelOperation: SWINGING
Type - Pset_DoorCommon - IsExternal: no; Reference: 1.63m x 2.04m; ThermalTransmittance: 3.7021 kg/K/s3
Type - Pset_QuantityTakeOff - Reference: 1.63m x 2.04m
OverallHeight: 2.075 m; OverallWidth: 1.7 m; Material: Porte - Poignée, Porte - Cadre, Porte - Panneau
Name (Double (R):1.63m x 2.04m:...) | In
1398069 | Niveau 00 - 02
1408812 | Niveau 00 - 01
1414296 | Niveau 00 - 01

# IfcDoor: Double (R):1.63m x 2.04m (2)
In: Niveau 2
Type - OperationType: DOUBLE_DOOR_SINGLE_SWING; ParameterTakesPrecedence: no; Sizeable: no; Material: Porte - Panneau, Porte - Cadre, Porte - Poignée
Type - Double (R):1.63m x 2.04m:1226216 - PanelOperation: SWINGING
Type - Pset_DoorCommon - IsExternal: no; Reference: 1.63m x 2.04m; ThermalTransmittance: 3.7021 kg/K/s3
Type - Pset_QuantityTakeOff - Reference: 1.63m x 2.04m
OverallHeight: 2.075 m; OverallWidth: 1.7 m; Material: Porte - Poignée, Porte - Cadre, Porte - Panneau
Name (Double (R):1.63m x 2.04m:...)
1226216
1232490

# IfcDoor: Double (R):1.63m x 2.04m (2)
In: Niveau 1
Type - OperationType: DOUBLE_DOOR_SINGLE_SWING; ParameterTakesPrecedence: no; Sizeable: no; Material: Porte - Panneau, Porte - Cadre, Porte - Poignée
Type - Double (R):1.63m x 2.04m:1265850 - PanelOperation: SWINGING
Type - Pset_DoorCommon - IsExternal: no; Reference: 1.63m x 2.04m; ThermalTransmittance: 3.7021 kg/K/s3
Type - Pset_QuantityTakeOff - Reference: 1.63m x 2.04m
OverallHeight: 2.075 m; OverallWidth: 1.7 m; Material: Porte - Poignée, Porte - Cadre, Porte - Panneau
Name (Double (R):1.63m x 2.04m:...)
1265850
1273372

# IfcDoor: Double (R):1.63m x 2.04m, Double (R):1.63m x 2.04m:1408282
In: Niveau 00 - 01
Type - OperationType: DOUBLE_DOOR_SINGLE_SWING; ParameterTakesPrecedence: no; Sizeable: no; Material: Porte - Panneau, Porte - Cadre, Porte - Poignée
Type - Double (R):1.63m x 2.04m:1408282 - PanelOperation: SWINGING
Type - Pset_DoorCommon - IsExternal: no; Reference: 1.63m x 2.04m; ThermalTransmittance: 3.7021 kg/K/s3
Type - Pset_QuantityTakeOff - Reference: 1.63m x 2.04m
OverallHeight: 2.075 m; OverallWidth: 1.7 m; Material: Porte - Poignée, Porte - Cadre, Porte - Panneau

# IfcDoor: Double (R):1.63m x 2.04m (3)
Type - OperationType: DOUBLE_DOOR_SINGLE_SWING; ParameterTakesPrecedence: no; Sizeable: no; Material: Porte - Panneau, Porte - Poignée, Porte - Cadre
Type - Double (R):1.63m x 2.04m:1213401 - PanelOperation: SWINGING
Type - Pset_DoorCommon - IsExternal: no; Reference: 1.63m x 2.04m; ThermalTransmittance: 3.7021 kg/K/s3
Type - Pset_QuantityTakeOff - Reference: 1.63m x 2.04m
OverallHeight: 2.075 m; OverallWidth: 1.7 m; Material: Porte - Poignée, Porte - Cadre, Porte - Panneau
Name (Double (R):1.63m x 2.04m:...) | In
1213401 | Niveau 2
1232284 | Niveau 2
1275222 | Niveau 1

# IfcDoor: Double (R):1.63m x 2.04m, Double (R):1.63m x 2.04m:1397982
In: Niveau 00 - 02
Type - OperationType: DOUBLE_DOOR_SINGLE_SWING; ParameterTakesPrecedence: no; Sizeable: no; Material: Porte - Panneau, Porte - Poignée, Porte - Cadre
Type - Double (R):1.63m x 2.04m:1397982 - PanelOperation: SWINGING
Type - Pset_DoorCommon - IsExternal: no; Reference: 1.63m x 2.04m; ThermalTransmittance: 3.7021 kg/K/s3
Type - Pset_QuantityTakeOff - Reference: 1.63m x 2.04m
OverallHeight: 2.075 m; OverallWidth: 1.7 m; Material: Porte - Poignée, Porte - Cadre, Porte - Panneau

# IfcDoor: Double (R):1.63m x 2.04m, Double (R):1.63m x 2.04m:1281705
In: Niveau 1
Type - OperationType: DOUBLE_DOOR_SINGLE_SWING; ParameterTakesPrecedence: no; Sizeable: no; Material: Porte - Poignée, Porte - Cadre, Porte - Panneau
Type - Double (R):1.63m x 2.04m:1281705 - PanelOperation: SWINGING
Type - Pset_DoorCommon - IsExternal: no; Reference: 1.63m x 2.04m; ThermalTransmittance: 3.7021 kg/K/s3
Type - Pset_QuantityTakeOff - Reference: 1.63m x 2.04m
OverallHeight: 2.075 m; OverallWidth: 1.7 m

# IfcDoor: Double (R):1.63m x 2.04m (3)
In: Niveau 00 - 01
Type - OperationType: DOUBLE_DOOR_SINGLE_SWING; ParameterTakesPrecedence: no; Sizeable: no; Material: Porte - Poignée, Porte - Cadre, Porte - Panneau
Type - Double (R):1.63m x 2.04m:1408029 - PanelOperation: SWINGING
Type - Pset_DoorCommon - IsExternal: no; Reference: 1.63m x 2.04m; ThermalTransmittance: 3.7021 kg/K/s3
Type - Pset_QuantityTakeOff - Reference: 1.63m x 2.04m
OverallHeight: 2.075 m; OverallWidth: 1.7 m
Name (Double (R):1.63m x 2.04m:...)
1408029
1408130
1408237

# IfcDoor: Double (R):1.73m x 2.10m, Double (R):1.73m x 2.10m:1398163
In: Niveau 00 - 02
Type - OperationType: DOUBLE_DOOR_SINGLE_SWING; ParameterTakesPrecedence: no; Sizeable: no; Material: Porte - Cadre, Porte - Panneau, Porte - Poignée
Type - Double (R):1.73m x 2.10m:1398163 - PanelOperation: SWINGING
Type - Pset_DoorCommon - IsExternal: no; Reference: 1.73m x 2.10m; ThermalTransmittance: 3.7021 kg/K/s3
Type - Pset_QuantityTakeOff - Reference: 1.73m x 2.10m
OverallHeight: 2.135 m; OverallWidth: 1.8 m; Material: Porte - Poignée, Porte - Cadre, Porte - Panneau

# IfcDoor: Double (R):1.73m x 2.10m, Double (R):1.73m x 2.10m:1405736
In: Niveau 00 - 01
Type - OperationType: DOUBLE_DOOR_SINGLE_SWING; ParameterTakesPrecedence: no; Sizeable: no; Material: Porte - Cadre, Porte - Poignée, Porte - Panneau
Type - Double (R):1.73m x 2.10m:1405736 - PanelOperation: SWINGING
Type - Pset_DoorCommon - IsExternal: no; Reference: 1.73m x 2.10m; ThermalTransmittance: 3.7021 kg/K/s3
Type - Pset_QuantityTakeOff - Reference: 1.73m x 2.10m
OverallHeight: 2.135 m; OverallWidth: 1.8 m; Material: Porte - Poignée, Porte - Cadre, Porte - Panneau

# IfcDoor: Double (R):1.73m x 2.10m (2)
In: Niveau 00 - 01
Type - OperationType: DOUBLE_DOOR_SINGLE_SWING; ParameterTakesPrecedence: no; Sizeable: no; Material: Porte - Poignée, Porte - Cadre, Porte - Panneau
Type - Double (R):1.73m x 2.10m:1406038 - PanelOperation: SWINGING
Type - Pset_DoorCommon - IsExternal: no; Reference: 1.73m x 2.10m; ThermalTransmittance: 3.7021 kg/K/s3
Type - Pset_QuantityTakeOff - Reference: 1.73m x 2.10m
OverallHeight: 2.135 m; OverallWidth: 1.8 m
Pset_OpeningElementCommon - Reference: 1.73m x 2.10m; sets with these values: 2
Name (Double (R):1.73m x 2.10m:...)
1406038
1406223

# IfcDoor: Double (R):1.73m x 2.9m, Double (R):1.73m x 2.9m:1414511
In: Niveau 00 - 01
Type - OperationType: DOUBLE_DOOR_SINGLE_SWING; ParameterTakesPrecedence: no; Sizeable: no; Material: Porte - Cadre, Porte - Panneau, Porte - Poignée
Type - Double (R):1.73m x 2.9m:1414511 - PanelOperation: SWINGING
Type - Pset_DoorCommon - IsExternal: no; Reference: 1.73m x 2.9m; ThermalTransmittance: 3.7021 kg/K/s3
Type - Pset_QuantityTakeOff - Reference: 1.73m x 2.9m
OverallHeight: 2.935 m; OverallWidth: 1.8 m; Material: Porte - Poignée, Porte - Cadre, Porte - Panneau

# IfcDoor: Double (R):1.73m x 2.9m, Double (R):1.73m x 2.9m:1372745
In: Niveau 00 - 01
Type - OperationType: DOUBLE_DOOR_SINGLE_SWING; ParameterTakesPrecedence: no; Sizeable: no; Material: Porte - Cadre, Porte - Poignée, Porte - Panneau
Type - Double (R):1.73m x 2.9m:1372745 - PanelOperation: SWINGING
Type - Pset_DoorCommon - IsExternal: no; Reference: 1.73m x 2.9m; ThermalTransmittance: 3.7021 kg/K/s3
Type - Pset_QuantityTakeOff - Reference: 1.73m x 2.9m
OverallHeight: 2.935 m; OverallWidth: 1.8 m; Material: Porte - Poignée, Porte - Cadre, Porte - Panneau

# IfcDoor: Double (R):1.73m x 2.9m, Double (R):1.73m x 2.9m:1415340
In: Niveau 00 - 01
Type - OperationType: DOUBLE_DOOR_SINGLE_SWING; ParameterTakesPrecedence: no; Sizeable: no; Material: Porte - Panneau, Porte - Poignée, Porte - Cadre
Type - Double (R):1.73m x 2.9m:1415340 - PanelOperation: SWINGING
Type - Pset_DoorCommon - IsExternal: no; Reference: 1.73m x 2.9m; ThermalTransmittance: 3.7021 kg/K/s3
Type - Pset_QuantityTakeOff - Reference: 1.73m x 2.9m
OverallHeight: 2.935 m; OverallWidth: 1.8 m; Material: Porte - Poignée, Porte - Cadre, Porte - Panneau

# IfcDoor: Double (R):200m x 2.10m, Double (R):200m x 2.10m:1411594
In: Niveau 00 - 01
Type - OperationType: DOUBLE_DOOR_SINGLE_SWING; ParameterTakesPrecedence: no; Sizeable: no; Material: Porte - Cadre, Porte - Poignée, Porte - Panneau
Type - Double (R):200m x 2.10m:1411594 - PanelOperation: SWINGING
Type - Pset_DoorCommon - IsExternal: no; Reference: 200m x 2.10m; ThermalTransmittance: 3.7021 kg/K/s3
Type - Pset_QuantityTakeOff - Reference: 200m x 2.10m
OverallHeight: 2.135 m; OverallWidth: 2.07 m; Material: Porte - Poignée, Porte - Cadre, Porte - Panneau

# IfcDoor: Double Vitrée :1.63m x 2.04m, Double Vitrée :1.63m x 2.04m:1223007
In: Niveau 2
Type - OperationType: DOUBLE_DOOR_SINGLE_SWING; ParameterTakesPrecedence: no; Sizeable: no; Material: Porte - Poignée, Porte - Panneau, Porte - Cadre
Type - Double Vitrée :1.63m x 2.04m:1223007 - PanelOperation: SWINGING
Type - Pset_DoorCommon - IsExternal: no; Reference: 1.63m x 2.04m; ThermalTransmittance: 3.7021 kg/K/s3
Type - Pset_QuantityTakeOff - Reference: 1.63m x 2.04m
OverallHeight: 2.08 m; OverallWidth: 1.71 m; Material: Porte - Poignée, Porte - Cadre, Porte - Panneau, Verre

# IfcDoor: Ouverture en rectangle:Ouverture 85x210, Ouverture en rectangle:Ouverture 85x210:1272475
In: Niveau 1
Type - ParameterTakesPrecedence: no; Sizeable: no; Material: Bois - Chêne
Type - Pset_DoorCommon - IsExternal: no; Reference: Ouverture 85x210
Type - Pset_QuantityTakeOff - Reference: Ouverture 85x210
OverallHeight: 2.1 m; OverallWidth: 0.85 m

# IfcDoor: Ouverture en rectangle:Ouverture 90x210, Ouverture en rectangle:Ouverture 90x210:1523056
In: Niveau 00
Type - ParameterTakesPrecedence: no; Sizeable: no; Material: Bois - Chêne
Type - Pset_DoorCommon - IsExternal: no; Reference: Ouverture 90x210
Type - Pset_QuantityTakeOff - Reference: Ouverture 90x210
OverallHeight: 2.1 m; OverallWidth: 0.9 m

# IfcDoor: Ouverture en rectangle:Ouverture100x200 (8)
In: Niveau 2
Type - ParameterTakesPrecedence: no; Sizeable: no; Material: Bois - Chêne
Type - Pset_DoorCommon - IsExternal: no; Reference: Ouverture100x200
Type - Pset_QuantityTakeOff - Reference: Ouverture100x200
OverallHeight: 2 m; OverallWidth: 1 m
Name (Ouverture en rectangle:Ouverture100x200:...)
1215167
1221558
1228006
1228117
1230978
1230979
1231056 | Pset_OpeningElementCommon - Reference: Ouverture100x200; sets with these values: 2
1231057 | Pset_OpeningElementCommon - Reference: Ouverture100x200; sets with these values: 2

# IfcDoor: Ouverture en rectangle:Ouverture110x210, Ouverture en rectangle:Ouverture110x210:1408471
In: Niveau 00 - 01
Type - ParameterTakesPrecedence: no; Sizeable: no; Material: Bois - Chêne
Type - Pset_DoorCommon - IsExternal: no; Reference: Ouverture110x210
Type - Pset_QuantityTakeOff - Reference: Ouverture110x210
OverallHeight: 2.1 m; OverallWidth: 1.1 m

# IfcDoor: PRT-plaard coulissant:PRT_COL_207*100 (3)
In: Niveau 00
Type - ParameterTakesPrecedence: no; Sizeable: no; Material: <Unnamed> (4)
Type - Pset_DoorCommon - IsExternal: no; Reference: PRT_COL_207*100
Type - Pset_QuantityTakeOff - Reference: PRT_COL_207*100
OverallHeight: 2.075 m; OverallWidth: 3.05 m
Name (PRT-plaard coulissant:PRT_COL_207*100:...) | Reference | sets with these values
1523199 | PRT_COL_207*100 | 2
1527764 | PRT_COL_207*100 | 2
1527814

# IfcDoor: PVC Double - Panneaux vitrés haut:1.43m x 2.20m, PVC Double - Panneaux vitrés haut:1.43m x 2.20m:1047159
In: Niveau 00 - 02
Type - OperationType: DOUBLE_DOOR_SINGLE_SWING; ParameterTakesPrecedence: no; Sizeable: no; Material: PVC - Blanc (3)
Type - PVC Double - Panneaux vitrés haut:1.43m x 2.20m:1047159 - PanelOperation: SWINGING
Type - Pset_DoorCommon - IsExternal: no; Reference: 1.43m x 2.20m; ThermalTransmittance: 3.6886 kg/K/s3
Type - Pset_QuantityTakeOff - Reference: 1.43m x 2.20m
OverallHeight: 2.25 m; OverallWidth: 1.53 m; Material: PVC - Blanc, Verre

# IfcDoor: PVC Double - Panneaux vitrés haut:1.43m x 2.20m, PVC Double - Panneaux vitrés haut:1.43m x 2.20m:1062307
In: Niveau 00 - 01
Type - OperationType: DOUBLE_DOOR_SINGLE_SWING; ParameterTakesPrecedence: no; Sizeable: no; Material: PVC - Blanc (3)
Type - PVC Double - Panneaux vitrés haut:1.43m x 2.20m:1062307 - PanelOperation: SWINGING
Type - Pset_DoorCommon - IsExternal: no; Reference: 1.43m x 2.20m; ThermalTransmittance: 3.6886 kg/K/s3
Type - Pset_QuantityTakeOff - Reference: 1.43m x 2.20m
OverallHeight: 2.25 m; OverallWidth: 1.53 m; Material: PVC - Blanc, Verre
Pset_OpeningElementCommon - Reference: 1.43m x 2.20m; sets with these values: 2

# IfcDoor: PVC Double - Panneaux vitrés haut:1.63m x 2.10m, PVC Double - Panneaux vitrés haut:1.63m x 2.10m:1046917
In: Niveau 00 - 03
Type - OperationType: DOUBLE_DOOR_SINGLE_SWING; ParameterTakesPrecedence: no; Sizeable: no; Material: PVC - Blanc (3)
Type - PVC Double - Panneaux vitrés haut:1.63m x 2.10m:1046917 - PanelOperation: SWINGING
Type - Pset_DoorCommon - IsExternal: no; Reference: 1.63m x 2.10m; ThermalTransmittance: 3.6886 kg/K/s3
Type - Pset_QuantityTakeOff - Reference: 1.63m x 2.10m
OverallHeight: 2.15 m; OverallWidth: 1.73 m; Material: PVC - Blanc, Verre

# IfcDoor: PVC Double - Panneaux vitrés haut:1.63m x 2.10m, PVC Double - Panneaux vitrés haut:1.63m x 2.10m:1386985
In: Niveau 00 - 01
Type - OperationType: DOUBLE_DOOR_SINGLE_SWING; ParameterTakesPrecedence: no; Sizeable: no; Material: PVC - Blanc (3)
Type - PVC Double - Panneaux vitrés haut:1.63m x 2.10m:1386985 - PanelOperation: SWINGING
Type - Pset_DoorCommon - IsExternal: no; Reference: 1.63m x 2.10m; ThermalTransmittance: 3.6886 kg/K/s3
Type - Pset_QuantityTakeOff - Reference: 1.63m x 2.10m
OverallHeight: 2.15 m; OverallWidth: 1.73 m; Material: PVC - Blanc, Verre

# IfcDoor: PVC Double - Panneaux vitrés haut:2m x 2.20m (2)
In: Niveau 00 - 03
Type - OperationType: DOUBLE_DOOR_SINGLE_SWING; ParameterTakesPrecedence: no; Sizeable: no; Material: PVC - Blanc (3)
Type - PVC Double - Panneaux vitrés haut:2m x 2.20m:1043306 - PanelOperation: SWINGING
Type - Pset_DoorCommon - IsExternal: no; Reference: 2m x 2.20m; ThermalTransmittance: 3.6886 kg/K/s3
Type - Pset_QuantityTakeOff - Reference: 2m x 2.20m
OverallHeight: 2.25 m; OverallWidth: 2.1 m; Material: PVC - Blanc, Verre
Pset_OpeningElementCommon - Reference: 2m x 2.20m; sets with these values: 2
Name (PVC Double - Panneaux vitrés haut:2m x 2.20m:...)
1043306
1043378

# IfcDoor: PVC Double - Panneaux vitrés haut:2m x 2.5m, PVC Double - Panneaux vitrés haut:2m x 2.5m:1386681
In: Niveau 00 - 01
Type - OperationType: DOUBLE_DOOR_SINGLE_SWING; ParameterTakesPrecedence: no; Sizeable: no; Material: PVC - Blanc (3)
Type - PVC Double - Panneaux vitrés haut:2m x 2.5m:1386681 - PanelOperation: SWINGING
Type - Pset_DoorCommon - IsExternal: no; Reference: 2m x 2.5m; ThermalTransmittance: 3.6886 kg/K/s3
Type - Pset_QuantityTakeOff - Reference: 2m x 2.5m
OverallHeight: 2.55 m; OverallWidth: 2.1 m; Material: PVC - Blanc, Verre

# IfcDoor: PVC Panneau Vitré - Traverse:0.93m x 2.10m, PVC Panneau Vitré - Traverse:0.93m x 2.10m:1396995
In: Niveau 00 - 02
Type - OperationType: SINGLE_SWING_RIGHT; ParameterTakesPrecedence: no; Sizeable: no; Material: PVC - Blanc (3)
Type - PVC Panneau Vitré - Traverse:0.93m x 2.10m:1396995 - PanelOperation: SWINGING
Type - Pset_DoorCommon - IsExternal: no; Reference: 0.93m x 2.10m; ThermalTransmittance: 5.5617 kg/K/s3
Type - Pset_QuantityTakeOff - Reference: 0.93m x 2.10m
OverallHeight: 2.15 m; OverallWidth: 1.03 m; Material: PVC - Blanc, Verre
Pset_OpeningElementCommon - Reference: 0.93m x 2.10m; sets with these values: 2

# IfcDoor: PVC Panneau Vitré - Traverse:103m x 2.20m, PVC Panneau Vitré - Traverse:103m x 2.20m:1054507
In: Niveau 00 - 02
Type - OperationType: SINGLE_SWING_LEFT; ParameterTakesPrecedence: no; Sizeable: no; Material: PVC - Blanc (3)
Type - PVC Panneau Vitré - Traverse:103m x 2.20m:1054507 - PanelOperation: SWINGING
Type - Pset_DoorCommon - IsExternal: no; Reference: 103m x 2.20m; ThermalTransmittance: 5.5617 kg/K/s3
Type - Pset_QuantityTakeOff - Reference: 103m x 2.20m
OverallHeight: 2.25 m; OverallWidth: 1.13 m; Material: PVC - Blanc, Verre

# IfcDoor: PVC Panneau Vitré - Traverse:103m x 2.20m, PVC Panneau Vitré - Traverse:103m x 2.20m:1051442
In: Niveau 00 - 02
Type - OperationType: SINGLE_SWING_RIGHT; ParameterTakesPrecedence: no; Sizeable: no; Material: PVC - Blanc (3)
Type - PVC Panneau Vitré - Traverse:103m x 2.20m:1051442 - PanelOperation: SWINGING
Type - Pset_DoorCommon - IsExternal: no; Reference: 103m x 2.20m; ThermalTransmittance: 5.5617 kg/K/s3
Type - Pset_QuantityTakeOff - Reference: 103m x 2.20m
OverallHeight: 2.25 m; OverallWidth: 1.13 m; Material: PVC - Blanc, Verre

# IfcDoor: PVC Panneau Vitré - Traverse:103m x 2.20m, PVC Panneau Vitré - Traverse:103m x 2.20m:1393332
In: Niveau 00 - 01
Type - OperationType: SINGLE_SWING_RIGHT; ParameterTakesPrecedence: no; Sizeable: no; Material: PVC - Blanc (3)
Type - PVC Panneau Vitré - Traverse:103m x 2.20m:1393332 - PanelOperation: SWINGING
Type - Pset_DoorCommon - IsExternal: no; Reference: 103m x 2.20m; ThermalTransmittance: 5.5617 kg/K/s3
Type - Pset_QuantityTakeOff - Reference: 103m x 2.20m
OverallHeight: 2.25 m; OverallWidth: 1.13 m; Material: PVC - Blanc, Verre

# IfcDoor: Placard pliante:Placard pliante 100, Placard pliante:Placard pliante 100:1350602
In: Niveau 00 - 02
Type - OperationType: FOLDING_TO_RIGHT; ParameterTakesPrecedence: no; Sizeable: no; Material: Placard - Porte, Placard - Encadrement (2)
Type - Placard pliante:Placard pliante 100:1350602 - PanelOperation: FOLDING
Type - Pset_DoorCommon - IsExternal: no; Reference: Placard pliante 100; ThermalTransmittance: 3.7021 kg/K/s3
Type - Pset_QuantityTakeOff - Reference: Placard pliante 100
OverallHeight: 2.1 m; OverallWidth: 1 m; Material: Placard - Encadrement, Placard - Porte

# IfcDoor: Placard pliante:Placard pliante 110, Placard pliante:Placard pliante 110:1351901
In: Niveau 00 - 02
Type - OperationType: FOLDING_TO_RIGHT; ParameterTakesPrecedence: no; Sizeable: no; Material: Placard - Porte, Placard - Encadrement (2)
Type - Placard pliante:Placard pliante 110:1351901 - PanelOperation: FOLDING
Type - Pset_DoorCommon - IsExternal: no; Reference: Placard pliante 110; ThermalTransmittance: 3.7021 kg/K/s3
Type - Pset_QuantityTakeOff - Reference: Placard pliante 110
OverallHeight: 2.1 m; OverallWidth: 1.1 m; Material: Placard - Encadrement, Placard - Porte

# IfcDoor: Placard pliante:Placard pliante 42, Placard pliante:Placard pliante 42:1493985
In: Niveau 00
Type - OperationType: FOLDING_TO_RIGHT; ParameterTakesPrecedence: no; Sizeable: no; Material: Placard - Encadrement (2), Placard - Porte
Type - Placard pliante:Placard pliante 42:1493985 - PanelOperation: FOLDING
Type - Pset_DoorCommon - IsExternal: no; Reference: Placard pliante 42; ThermalTransmittance: 3.7021 kg/K/s3
Type - Pset_QuantityTakeOff - Reference: Placard pliante 42
OverallHeight: 2.1 m; OverallWidth: 0.42 m; Material: Placard - Encadrement, Placard - Porte

# IfcDoor: Porte métal:@_PP (1.03m x 1.8m), Porte métal:@_PP (1.03m x 1.8m):1200092
In: Niveau 3
Type - ParameterTakesPrecedence: no; Sizeable: no; Material: RAL1013-Blanc perle (3), @_Finition Peinture - Blanc satiné
Type - Pset_DoorCommon - IsExternal: no; Reference: @_PP (1.03m x 1.8m)
Type - Pset_QuantityTakeOff - Reference: @_PP (1.03m x 1.8m)
OverallHeight: 1.735 m; OverallWidth: 1.1 m; Material: @_Finition Peinture - Blanc satiné, RAL1013-Blanc perle

# IfcDoor: Simple vitrée:Simple vitrée (2)
In: Niveau 00 - 01
Type - OperationType: SINGLE_SWING_LEFT; ParameterTakesPrecedence: no; Sizeable: no; Material: Porte - Cadre, Porte - Panneau, Porte - Poignée
Type - Simple vitrée:Simple vitrée:1374857 - PanelOperation: SWINGING
Type - Pset_DoorCommon - IsExternal: no; Reference: Simple vitrée; ThermalTransmittance: 3.6886 kg/K/s3
Type - Pset_QuantityTakeOff - Reference: Simple vitrée
OverallHeight: 2.2105 m; OverallWidth: 0.745 m; Material: Porte - Poignée, Porte - Cadre, Verre, Porte - Panneau
Pset_DoorCommon - IsExternal: yes
Name (Simple vitrée:Simple vitrée:...)
1374857
1528203

# IfcDoor: Simple vitrée:Simple vitrée, Simple vitrée:Simple vitrée:1368383
In: Niveau 00 - 01
Type - OperationType: SINGLE_SWING_LEFT; ParameterTakesPrecedence: no; Sizeable: no; Material: Porte - Cadre, Porte - Poignée, Porte - Panneau
Type - Simple vitrée:Simple vitrée:1368383 - PanelOperation: SWINGING
Type - Pset_DoorCommon - IsExternal: no; Reference: Simple vitrée; ThermalTransmittance: 3.6886 kg/K/s3
Type - Pset_QuantityTakeOff - Reference: Simple vitrée
OverallHeight: 2.32833 m; OverallWidth: 1.01507 m; Material: Porte - Poignée, Porte - Cadre, Verre, Porte - Panneau
Pset_DoorCommon - IsExternal: yes

# IfcDoor: Simple vitrée:Simple vitrée, Simple vitrée:Simple vitrée:1368388
In: Niveau 00 - 01
Type - OperationType: SINGLE_SWING_LEFT; ParameterTakesPrecedence: no; Sizeable: no; Material: Porte - Panneau, Porte - Cadre, Porte - Poignée
Type - Simple vitrée:Simple vitrée:1368388 - PanelOperation: SWINGING
Type - Pset_DoorCommon - IsExternal: no; Reference: Simple vitrée; ThermalTransmittance: 3.6886 kg/K/s3
Type - Pset_QuantityTakeOff - Reference: Simple vitrée
OverallHeight: 2.32833 m; OverallWidth: 0.792097 m; Material: Porte - Poignée, Porte - Cadre, Verre, Porte - Panneau
Pset_DoorCommon - IsExternal: yes

# IfcDoor: Simple vitrée:Simple vitrée (2)
In: Niveau 00 - 02
Type - OperationType: SINGLE_SWING_RIGHT; ParameterTakesPrecedence: no; Sizeable: no; Material: Porte - Poignée, Porte - Cadre, Porte - Panneau
Type - Simple vitrée:Simple vitrée:1121981 - PanelOperation: SWINGING
Type - Pset_DoorCommon - IsExternal: no; Reference: Simple vitrée; ThermalTransmittance: 3.6886 kg/K/s3
Type - Pset_QuantityTakeOff - Reference: Simple vitrée
OverallHeight: 2.25 m; OverallWidth: 1.11586 m; Material: Porte - Poignée, Porte - Cadre, Verre, Porte - Panneau
Pset_DoorCommon - IsExternal: yes
Name (Simple vitrée:Simple vitrée:...)
1121981
1361508

# IfcDoor: Simple vitrée:Simple vitrée (2)
In: Niveau 00 - 01
Type - OperationType: SINGLE_SWING_RIGHT; ParameterTakesPrecedence: no; Sizeable: no; Material: Porte - Poignée, Porte - Cadre, Porte - Panneau
Type - Simple vitrée:Simple vitrée:1374209 - PanelOperation: SWINGING
Type - Pset_DoorCommon - IsExternal: no; Reference: Simple vitrée; ThermalTransmittance: 3.6886 kg/K/s3
Type - Pset_QuantityTakeOff - Reference: Simple vitrée
OverallHeight: 2.2105 m; OverallWidth: 0.74663 m; Material: Porte - Poignée, Porte - Cadre, Verre, Porte - Panneau
Pset_DoorCommon - IsExternal: yes
Name (Simple vitrée:Simple vitrée:...)
1374209
1528187

# IfcDoor: Tierce 160:1.10m x 2.04m (8)
Type - ParameterTakesPrecedence: no; Sizeable: no; Material: Porte - Cadre, Porte - Panneau (2), Porte - Poignée
Type - Pset_DoorCommon - IsExternal: no; Reference: 1.10m x 2.04m; ThermalTransmittance: 3.7021 kg/K/s3
Type - Pset_QuantityTakeOff - Reference: 1.10m x 2.04m
OverallHeight: 2.075 m; OverallWidth: 1.12 m; Material: Porte - Poignée, Porte - Cadre, Verre, Porte - Panneau
Name (Tierce 160:1.10m x 2.04m:...) | In
1213566 | Niveau 2
1231607 | Niveau 2
1232174 | Niveau 2
1232216 | Niveau 2 | Pset_OpeningElementCommon - Reference: 1.10m x 2.04m; sets with these values: 2
1232238 | Niveau 2
1232378 | Niveau 2
1233400 | Niveau 2
1275268 | Niveau 1

# IfcDoor: Tierce 160:1.10m x 2.04m (13)
Type - ParameterTakesPrecedence: no; Sizeable: no; Material: Porte - Panneau (2), Porte - Cadre, Porte - Poignée
Type - Pset_DoorCommon - IsExternal: no; Reference: 1.10m x 2.04m; ThermalTransmittance: 3.7021 kg/K/s3
Type - Pset_QuantityTakeOff - Reference: 1.10m x 2.04m
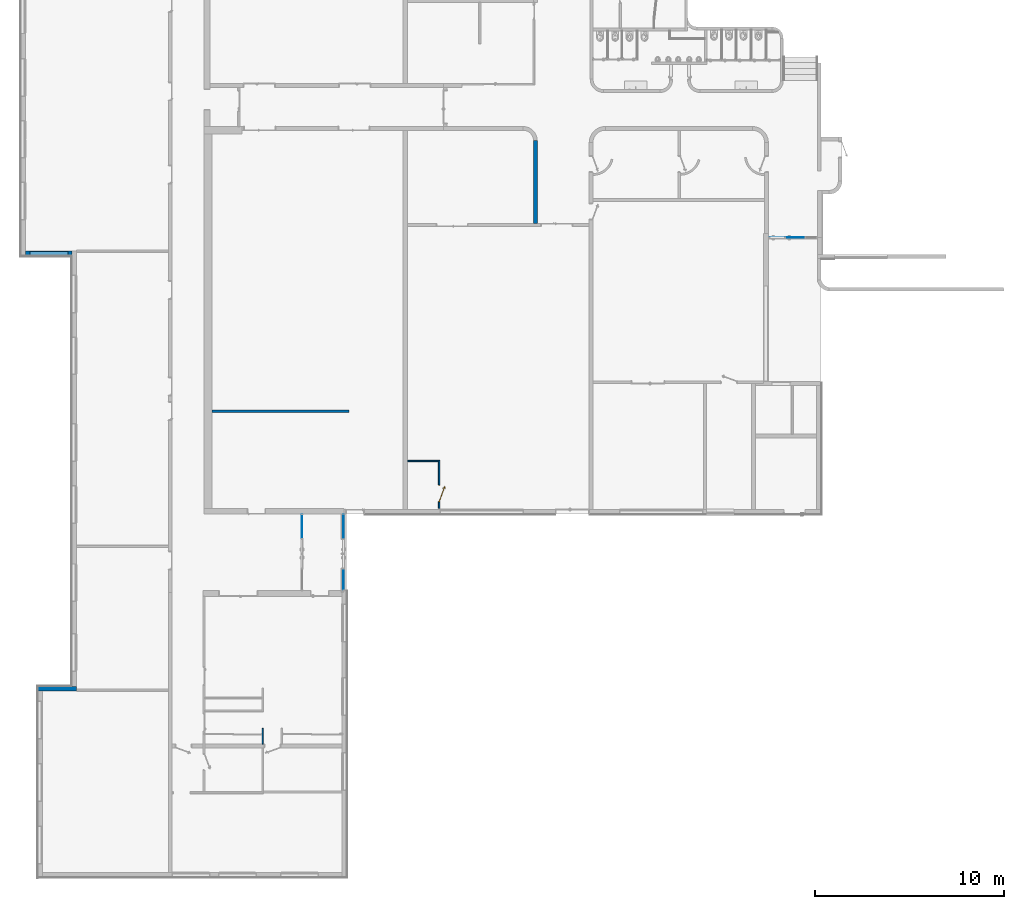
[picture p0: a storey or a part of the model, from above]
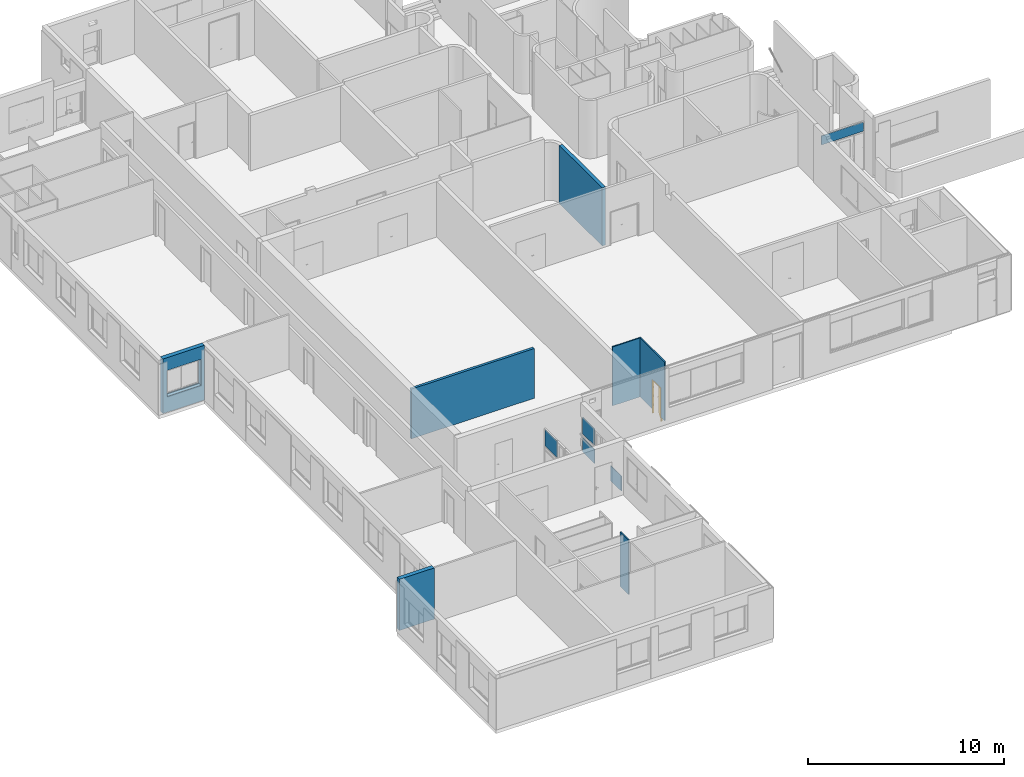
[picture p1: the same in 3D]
Properties of the parts of a building model (IFC2X3), part 2 of 4

# IfcDoor: Tierce 160:1.10m x 2.04m (13)
OverallHeight: 2.075 m; OverallWidth: 1.12 m; Material: Porte - Poignée, Porte - Cadre, Verre, Porte - Panneau
Name (Tierce 160:1.10m x 2.04m:...) | In
1227734 | Niveau 2
1231657 | Niveau 2
1232153 | Niveau 2
1232191 | Niveau 2
1232337 | Niveau 2
1232357 | Niveau 2
1233445 | Niveau 2
1265248 | Niveau 1
1269261 | Niveau 1
1269283 | Niveau 1
1273140 | Niveau 1
1273312 | Niveau 1
1275286 | Niveau 1 | Pset_OpeningElementCommon - Reference: 1.10m x 2.04m; sets with these values: 2

# IfcDoor: Tierce 160:1.10m x 2.04m, Tierce 160:1.10m x 2.04m:1264427
In: Niveau 1
Type - ParameterTakesPrecedence: no; Sizeable: no; Material: Porte - Panneau (2), Porte - Poignée, Porte - Cadre
Type - Pset_DoorCommon - IsExternal: no; Reference: 1.10m x 2.04m; ThermalTransmittance: 3.7021 kg/K/s3
Type - Pset_QuantityTakeOff - Reference: 1.10m x 2.04m
OverallHeight: 2.075 m; OverallWidth: 1.12 m; Material: Porte - Poignée, Porte - Cadre, Verre, Porte - Panneau

# IfcDoor: Tierce 160:1.10m x 2.04m (2)
Type - ParameterTakesPrecedence: no; Sizeable: no; Material: Porte - Poignée, Porte - Panneau (2), Porte - Cadre
Type - Pset_DoorCommon - IsExternal: no; Reference: 1.10m x 2.04m; ThermalTransmittance: 3.7021 kg/K/s3
Type - Pset_QuantityTakeOff - Reference: 1.10m x 2.04m
OverallHeight: 2.075 m; OverallWidth: 1.12 m; Material: Porte - Poignée, Porte - Cadre, Verre, Porte - Panneau
Name (Tierce 160:1.10m x 2.04m:...) | In
1226052 | Niveau 2
1268904 | Niveau 1

# IfcFlowTerminal: Bidet - 02:550 x 360mm (31)
Type - Material: Porcelaine - Blanche
Type - Pset_QuantityTakeOff - Reference: 550 x 360mm
Pset_DistributionFlowElementCommon - Reference: 550 x 360mm; sets with these values: 3
Name (Bidet - 02:550 x 360mm:...) | In
1093461 | Niveau 00
1275656 | Niveau 1
1282869 | Niveau 1
1282890 | Niveau 1
1282944 | Niveau 1
1283186 | Niveau 1
1283241 | Niveau 1
1283313 | Niveau 1
1283341 | Niveau 1
1283534 | Niveau 1
1293533 | Niveau 2
1293614 | Niveau 2
1293654 | Niveau 2
1294210 | Niveau 2
1294211 | Niveau 2
1294212 | Niveau 2
1294214 | Niveau 2
1401819 | Niveau 00 - 01
1401820 | Niveau 00 - 01
1402731 | Niveau 00 - 01
1402762 | Niveau 00 - 01
1402793 | Niveau 00 - 01
1402802 | Niveau 00 - 01
1402811 | Niveau 00 - 01
1402820 | Niveau 00 - 01
1412600 | Niveau 00 - 01
1412635 | Niveau 00 - 01
1412671 | Niveau 00 - 01
1412701 | Niveau 00
1412809 | Niveau 00 - 01
1498514 | Niveau 00

# IfcFlowTerminal: Lavabo de salle de bain blanc:1000 mm x 400 mm (2)
In: Niveau 1
Type - Material: Porcelaine - Blanche, Métal - Chrome
Type - Pset_QuantityTakeOff - Reference: 1000 mm x 400 mm
Material: Métal - Chrome, Porcelaine - Blanche
Pset_DistributionFlowElementCommon - Reference: 1000 mm x 400 mm; sets with these values: 3
Name (Lavabo de salle de bain blanc:1000 mm x 400 mm:...)
1280352
1283612

# IfcFlowTerminal: Lavabo de salle de bain blanc:1200 mm x 400 mm (2)
In: Niveau 00 - 01
Type - Material: Métal - Chrome, Porcelaine - Blanche
Type - Pset_QuantityTakeOff - Reference: 1200 mm x 400 mm
Pset_DistributionFlowElementCommon - Reference: 1200 mm x 400 mm; sets with these values: 3
Name (Lavabo de salle de bain blanc:1200 mm x 400 mm:...)
1413065
1413066

# IfcFlowTerminal: Lavabo de salle de bain blanc:1200 mm x 400 mm (10)
Type - Material: Porcelaine - Blanche, Métal - Chrome
Type - Pset_QuantityTakeOff - Reference: 1200 mm x 400 mm
Material: Métal - Chrome, Porcelaine - Blanche
Pset_DistributionFlowElementCommon - Reference: 1200 mm x 400 mm; sets with these values: 3
Name (Lavabo de salle de bain blanc:1200 mm x 400 mm:...) | In
1283701 | Niveau 1
1283774 | Niveau 1
1293770 | Niveau 2
1403903 | Niveau 00 - 01
1403904 | Niveau 00 - 01
1412313 | Niveau 00 - 01
1412382 | Niveau 00 - 01
1412466 | Niveau 00 - 01
1413027 | Niveau 00 - 01
1413226 | Niveau 00 - 01

# IfcFlowTerminal: Lavabo mural - 02:500 mm x 500 mm, Lavabo mural - 02:500 mm x 500 mm:1093159
In: Niveau 00 - 03
Type - Material: Porcelaine - Blanche
Type - Pset_QuantityTakeOff - Reference: 500 mm x 500 mm
Pset_DistributionFlowElementCommon - Reference: 500 mm x 500 mm; sets with these values: 2

# IfcFlowTerminal: Sanitary_Bidets_Sanitana_CORAL-bidet-wall-mounted:CORAL bidet - wall-mounted (2)
Type - Material: Acrylic-Sanitana-White
Type - Pset_QuantityTakeOff - Reference: CORAL bidet - wall-mounted
Material: Acrylic-Sanitana-White, Metal-Sanitana-Chrome
Pset_DistributionFlowElementCommon - Reference: CORAL bidet - wall-mounted; sets with these values: 3
Name (Sanitary_Bidets_Sanitana_CORAL-bidet-wall-mounted:CORAL bidet - wall-mounted:...) | In
1289371 | Niveau 1
1294219 | Niveau 2

# IfcFlowTerminal: urinoir:Default (27)
Type - Material: CeramicWhite 9650BEC
Type - Pset_QuantityTakeOff - Reference: Default
Pset_DistributionFlowElementCommon - Reference: Default; sets with these values: 3
Name (urinoir:Default:...) | In
1286317 | Niveau 1
1286362 | Niveau 1
1286397 | Niveau 1
1286527 | Niveau 1
1289438 | Niveau 1
1289481 | Niveau 1
1289506 | Niveau 1
1289629 | Niveau 1
1289637 | Niveau 1
1294215 | Niveau 2
1294216 | Niveau 2
1294217 | Niveau 2
1294221 | Niveau 2
1294222 | Niveau 2
1294223 | Niveau 2
1294263 | Niveau 2
1294264 | Niveau 2
1294265 | Niveau 2
1401866 | Niveau 00 - 03
1401885 | Niveau 00 - 01
1401920 | Niveau 00 - 01
1401939 | Niveau 00 - 01
1401958 | Niveau 00 - 01
1401979 | Niveau 00 - 01
1413095 | Niveau 00 - 01
1413158 | Niveau 00 - 01
1413179 | Niveau 00 - 01

# IfcFurnishingElement: Mobilier 1:Mobilier 1, Mobilier 1:Mobilier 1:1089602
In: Niveau 00 - 03
Type - Material: @_Finition Peinture - Blanc satiné
Type - Pset_QuantityTakeOff - Reference: Mobilier 1

# IfcMember: Meneau rectangulaire:50 x 100mm (131)
Type - PredefinedType: MULLION; Material: Aluminium 2
Type - Pset_MemberCommon - IsExternal: no; Reference: 50 x 100mm
Type - Pset_QuantityTakeOff - Reference: 50 x 100mm
Name (Meneau rectangulaire:50 x 100mm:...) | In | Span (m)
1121817 | Niveau 00 - 02 | 1.09086
1121818 | Niveau 00 - 02 | 1.06829
1121819 | Niveau 00 - 02 | 1.01
1121820 | Niveau 00 - 02 | 1.24
1121988 | Niveau 00 - 02 | 1.09329
1121989 | Niveau 00 - 02 | 1.16586
1121990 | Niveau 00 - 02 | 1.01
1122031 | Niveau 00 - 02 | 1.11586
1122032 | Niveau 00 - 02 | 1.16586
1122033 | Niveau 00 - 02 | 1.01
1122104 | Niveau 00 - 02 | 1.29
1122105 | Niveau 00 - 02 | 1.06
1122106 | Niveau 00 - 02 | 1.04329
1122108 | Niveau 00 - 02 | 1.09086
1122109 | Niveau 00 - 02 | 1.29
1122110 | Niveau 00 - 02 | 1.29
1361503 | Niveau 00 - 02 | 1.09086
1361504 | Niveau 00 - 02 | 1.06829
1361505 | Niveau 00 - 02 | 1.01
1361506 | Niveau 00 - 02 | 1.24
1361509 | Niveau 00 - 02 | 1.09329
1361510 | Niveau 00 - 02 | 1.16586
1361511 | Niveau 00 - 02 | 1.01
1361514 | Niveau 00 - 02 | 1.11586
1361515 | Niveau 00 - 02 | 1.16586
1361516 | Niveau 00 - 02 | 1.01
1361521 | Niveau 00 - 02 | 1.29
1361522 | Niveau 00 - 02 | 1.06
1361523 | Niveau 00 - 02 | 1.04329
1361524 | Niveau 00 - 02 | 1.09086
1361525 | Niveau 00 - 02 | 1.29
1361526 | Niveau 00 - 02 | 1.29
1368378 | Niveau 00 - 01 | 0.817097
1368379 | Niveau 00 - 01 | 0.554929
1368380 | Niveau 00 - 01 | 1.06
1368381 | Niveau 00 - 01 | 0.561667
1368384 | Niveau 00 - 01 | 0.629929
1368386 | Niveau 00 - 01 | 1.06
1368389 | Niveau 00 - 01 | 1.06507
1368391 | Niveau 00 - 01 | 1.06
1368396 | Niveau 00 - 01 | 1.29333
1368397 | Niveau 00 - 01 | 1.06
1368400 | Niveau 00 - 01 | 1.31833
1368401 | Niveau 00 - 01 | 1.31833
1368731 | Niveau 00 - 01 | 0.636667
1368732 | Niveau 00 - 01 | 1.26833
1368733 | Niveau 00 - 01 | 0.604929
1368734 | Niveau 00 - 01 | 1.01507
1368735 | Niveau 00 - 01 | 0.792097
1374204 | Niveau 00 - 01 | 1.08837
1374205 | Niveau 00 - 01 | 1.22
1374206 | Niveau 00 - 01 | 0.96
1374207 | Niveau 00 - 01 | 1.04036
1374210 | Niveau 00 - 01 | 0.745
1374214 | Niveau 00 - 01 | 0.74663
1374220 | Niveau 00 - 01 | 0.110138
1374221 | Niveau 00 - 01 | 0.1
1374387 | Niveau 00 - 01 | 0.96
1374388 | Niveau 00 - 01 | 0.96
1374389 | Niveau 00 - 01 | 0.110138
1374390 | Niveau 00 - 01 | 0.110138
1374864 | Niveau 00 - 01 | 1.27
1374866 | Niveau 00 - 01 | 0.96
1374867 | Niveau 00 - 01 | 0.110138
1376400 | Niveau 00 - 01 | 0.1
1376401 | Niveau 00 - 01 | 0.48
1376402 | Niveau 00 - 01 | 1.22
1376406 | Niveau 00 - 01 | 0.1
1376407 | Niveau 00 - 01 | 0.1
1376408 | Niveau 00 - 01 | 0.1
1376518 | Niveau 00 - 01 | 1.09036
1376519 | Niveau 00 - 01 | 0.110138
1376520 | Niveau 00 - 01 | 1.22
1376524 | Niveau 00 - 01 | 1.09036
1376525 | Niveau 00 - 01 | 1.09036
1376526 | Niveau 00 - 01 | 1.09036
1376592 | Niveau 00 - 01 | 1.0005
1376593 | Niveau 00 - 01 | 0.0898625
1376597 | Niveau 00 - 01 | 1.175
1376598 | Niveau 00 - 01 | 1.0005
1376599 | Niveau 00 - 01 | 1.0005
1376600 | Niveau 00 - 01 | 1.0005
1376963 | Niveau 00 - 01 | 1.08837
1377158 | Niveau 00 - 01 | 0.1
1377159 | Niveau 00 - 01 | 0.96
1377163 | Niveau 00 - 01 | 1.08837
1377164 | Niveau 00 - 01 | 0.1
1377165 | Niveau 00 - 01 | 0.1
1377166 | Niveau 00 - 01 | 0.1
1377345 | Niveau 00 - 01 | 1.22
1528182 | Niveau 00 - 01 | 1.08837
1528183 | Niveau 00 - 01 | 1.22
1528184 | Niveau 00 - 01 | 0.96
1528185 | Niveau 00 - 01 | 1.04036
1528188 | Niveau 00 - 01 | 0.745
1528191 | Niveau 00 - 01 | 0.74663
1528196 | Niveau 00 - 01 | 0.110138
1528197 | Niveau 00 - 01 | 0.1
1528198 | Niveau 00 - 01 | 0.96
1528199 | Niveau 00 - 01 | 0.96
1528200 | Niveau 00 - 01 | 0.110138
1528201 | Niveau 00 - 01 | 0.110138
1528205 | Niveau 00 - 01 | 1.27
1528206 | Niveau 00 - 01 | 0.96
1528207 | Niveau 00 - 01 | 0.110138
1528213 | Niveau 00 - 01 | 0.1
1528214 | Niveau 00 - 01 | 0.48
1528215 | Niveau 00 - 01 | 1.22
1528216 | Niveau 00 - 01 | 0.1
1528217 | Niveau 00 - 01 | 0.1
1528218 | Niveau 00 - 01 | 0.1
1528224 | Niveau 00 - 01 | 1.09036
1528225 | Niveau 00 - 01 | 0.110138
1528226 | Niveau 00 - 01 | 1.22
1528227 | Niveau 00 - 01 | 1.09036
1528228 | Niveau 00 - 01 | 1.09036
1528229 | Niveau 00 - 01 | 1.09036
1528235 | Niveau 00 - 01 | 1.0005
1528236 | Niveau 00 - 01 | 0.0898625
1528237 | Niveau 00 - 01 | 1.175
1528238 | Niveau 00 - 01 | 1.0005
1528239 | Niveau 00 - 01 | 1.0005
1528240 | Niveau 00 - 01 | 1.0005
1528241 | Niveau 00 - 01 | 1.08837
1528247 | Niveau 00 - 01 | 0.1
1528248 | Niveau 00 - 01 | 0.96
1528249 | Niveau 00 - 01 | 1.08837
1528250 | Niveau 00 - 01 | 0.1
1528251 | Niveau 00 - 01 | 0.1
1528252 | Niveau 00 - 01 | 0.1
1528253 | Niveau 00 - 01 | 1.22

# IfcOpeningElement: Opening (761)
Name | In | Pset_OpeningElementCommon, Reference | sets with these values
Fenêtre type 1:116x 240 cm:1529254:1 | Niveau 00 - 02
Mur de base:Ext. Voile BA 250:970852 | Niveau 00 - 01 | SANS Calpinage | 2
Mur de base:Ext. Voile BA 250:970854 | Niveau 00 - 01 | @_PP (0.63m x 2.04m) | 2
Mur de base:Ext. Voile BA 250:970858 | Niveau 00 - 01 | 1.43m x 2.20m | 2
Mur de base:Ext. Voile BA 250:970858 | Niveau 00 - 01 | Type A | 2
2 x Mur de base:Mur Blanc 150- isolation 50:970859 | Niveau 00 - 01 | Type 1 | 2
Mur de base:Ext. Voile BA 250:970873 | Niveau 00 - 01 | @_PP (1.03m x 2.30m) | 2
2 x Mur de base:Ext. Voile BA 250:970873 | Niveau 00 - 01 | Type A | 2
2 x Mur de base:Ext. Voile BA 200:970884 | Niveau 00 - 02 | Type 1 | 2
3 x Mur de base:Ext. Voile BA 200:970884 | Niveau 00 - 02 | 48 x 240 cm | 2
Mur de base:Ext. Voile BA 200:970889:1 | Niveau 00 - 01 | Ext. Voile BA 200 | 2
Fenêtre type 1:195 x 240 cm:1529050:1 | Niveau 00 - 02
Mur de base:Ext. Voile BA 200:970896 | Niveau 00 - 01 | 1.73m x 2.10m | 2
Mur de base:Ext. Voile BA 250:970897 | Niveau 00 - 01 | 1.43m x 2.20m | 2
2 x Mur de base:Ext. Voile BA 300:970900 | Niveau 00 - 01 | 190x440 | 2
Mur de base:Ext. Voile BA 200:970914 | Niveau 00 - 01 | 1.73m x 2.10m | 2
Mur de base:Ext. Voile BA 150:970922 | Niveau 00 - 01 | @_PP (0.73m x 2.04m) | 2
Mur de base:Ext. Voile BA 150:970923 | Niveau 00 - 01 | @_PP (0.73m x 2.04m) | 2
2 x Mur de base:@_Générique - Int. 100 mm:970950 | Niveau 00 - 01 | PRT_COL_207*100 | 2
Mur de base:Ext. Voile BA 150:970960 | Niveau 00 - 01 | @_PP (0.73m x 2.04m) | 2
Mur de base:Ext. Voile BA 150:970962 | Niveau 00 - 01 | @_PP (0.73m x 2.04m) | 2
Mur de base:Ext. Voile BA 150:970964 | Niveau 00 - 01 | 1.43m x 2.04m | 2
Mur de base:@_Générique - Int. 200 mm:169355 | Niveau 00 - 03 | @_Générique - Int. 200 mm | 2
21 x Mur de base:Ext. Mur 250+enduit Rouge:971290 | Niveau 1 | Type 1 | 2
Fenêtre type 1:48 x 240 cm:1528821:1 | Niveau 00 - 02
@_Int. Simple:@_PP (0.83m x 2.04m):1522945:1 | Niveau 00 - 01
21 x Mur de base:Ext. Mur 250+enduit Rouge:971291 | Niveau 1 | Type 1 | 2
@_Int. Simple:@_PP (0.83m x 2.04m):1518072:1 | Niveau 2
Mur de base:Ext. Mur 250+enduit Rouge:971291 | Niveau 1 | Type 2 | 2
Mur de base:Ext. Voile BA 200:971293 | Niveau 1 | Ext. Voile BA 200 | 2
2 x Mur de base:Ext. Voile BA 200:745683 | Niveau 1 | Ext. Voile BA 200 | 2
2 x Mur de base:Ext. Voile BA 150:971298 | Niveau 1 | 1.43m x 2.04m | 2
Mur de base:Ext. Voile BA 150:971302 | Niveau 1 | 1.43m x 2.04m | 2
@_Int. Simple:@_PP (0.83m x 2.04m):1487658:1 | Niveau 00 - 01
Mur de base:Ext. Voile BA 150:971306 | Niveau 1 | @_PP (0.83m x 2.04m) | 2
Mur de base:@_Générique - Int. 200 mm:971315 | Niveau 1 | @_PP (0.93m x 2.04m) | 2
Mur de base:Ext. Voile BA 200 Brique:971323 | Niveau 1 | 1.10m x 2.04m | 2
 | Niveau 1 - 01
Sol:Dalle béton 200mm:971375:2 | Niveau 1 - 01 | Dalle béton 200mm | 2
Sol:Dalle béton 200mm:971375:3 | Niveau 1 - 01 | Dalle béton 200mm | 2
Mur de base:Ext. Mur 250+enduit Rouge:971386:1 | Niveau 2 | Ext. Mur 250+enduit Rouge | 2
19 x Mur de base:Ext. Mur 250+enduit Rouge:971386 | Niveau 2 | Type 2 | 2
@_Int. Simple:@_PP (1.03m x 2.30m):1419078:1 | Niveau 00 - 01
21 x Mur de base:Ext. Mur 250+enduit Rouge:971387 | Niveau 2 | Type 2 | 2
@_Int. Simple:@_PP (0.93m x 2.25):1416117:1 | Niveau 00 - 01
21 x Mur de base:Ext. Mur 250+enduit Rouge:971388 | Niveau 2 | Type 2 | 2
PRT-plaard coulissant:PRT_COL_207*100:1523199:1 | Niveau 00 - 01
Double (R):200m x 2.10m:1411594:1 | Niveau 00 - 01
Mur de base:Ext. Mur 250+enduit Rouge:971389:1 | Niveau 2 | Ext. Mur 250+enduit Rouge | 2
18 x Mur de base:Ext. Mur 250+enduit Rouge:971389 | Niveau 2 | Type 2 | 2
PRT-plaard coulissant:PRT_COL_207*100:1527764:1 | Niveau 00 - 01
Mur de base:Ext. Mur 250+enduit Rouge:971389 | Niveau 2 | Type 3 | 2
2 x Mur de base:Ext. Voile BA 200:971414 | Niveau 2 | Ouverture100x200 | 2
Sol:Dalle béton 330mm:971443:2 | Niveau 3 | Dalle béton 330mm | 2
Sol:Dalle béton 330mm:971443:3 | Niveau 3 | Dalle béton 330mm | 2
Sol:Dalle béton 330mm:971443:4 | Niveau 3 | Dalle béton 330mm | 2
Sol:Dalle béton 330mm:971443:5 | Niveau 3 | Dalle béton 330mm | 2
Sol:Dalle béton 330mm:971443:6 | Niveau 3 | Dalle béton 330mm | 2
Sol:Dalle béton 330mm:971443:7 | Niveau 3 | Dalle béton 330mm | 2
Sol:Dalle béton 330mm:971443:8 | Niveau 3 | Dalle béton 330mm | 2
Sol:Dalle béton 330mm:971443:9 | Niveau 3 | Dalle béton 330mm | 2
Sol:Dalle béton 200mm:971450:2 | Niveau 1 - 03 | Dalle béton 200mm | 2
Sol:Dalle béton 200mm:971450:3 | Niveau 1 - 03 | Dalle béton 200mm | 2
Sol:Dalle béton 200mm:971450:4 | Niveau 1 - 03 | Dalle béton 200mm | 2
Sol:Dalle béton 200mm:971450:5 | Niveau 1 - 03 | Dalle béton 200mm | 2
Mur de base:Ext. Voile BA 200:971462 | Niveau 3 - 01 | Ext. Voile BA 200 | 2
Mur de base:Ext. Voile BA 200:971462 | Niveau 3 - 01 | 1000 x 820 mm | 2
PRT-plaard coulissant:PRT_COL_207*100:1527814:1 | Niveau 00 - 01
Mur de base:Ext. Voile BA 200:971463 | Niveau 3 - 01 | Type A | 2
 | Niveau 4
Mur de base:Mur EXE 200- Hach:971480 | Niveau 1 - 03 | 32 x 105 cm | 2
Mur de base:Mur EXE 200- Hach:971481 | Niveau 1 - 03 | Type 1 | 2
Mur de base:Ext. Voile BA 200:971558 | Niveau 2 | 1.10m x 2.04m | 2
Mur de base:@_Générique - Int. 150 mm:971574 | Niveau 2 | @_PP (0.83m x 2.04m) | 2
Mur de base:@_Générique - Int. 200 mm:971578 | Niveau 2 | @_PP (0.63m x 2.04m) | 2
Mur de base:Ext. Voile BA 150:971579 | Niveau 2 | @_PP (0.63m x 2.04m) | 2
Mur de base:@_Générique - Int. 70 mm:971944 | Niveau 00 - 01 | @_PP (0.63m x 2.04m) | 2
Mur de base:@_Générique - Int. 100 mm:169329 | SOUS SOL | @_Générique - Int. 100 mm | 2
Sol:Dalle béton 200mm:977241:2 | Niveau 3 - 02 | Dalle béton 200mm | 2
 | Niveau 3 - 02
Mur de base:Ext. Voile BA 200 bleu:1004639:1 | Niveau 00 - 02 | Ext. Voile BA 200 bleu | 2
2 x Mur de base:Ext. Voile BA 220:1006713 | Niveau 00 - 03 | 2m x 2.20m | 2
2 x Mur de base:Ext. Voile BA 220:1007003 | Niveau 00 - 03 | 2m x 2.20m | 2
Mur de base:Ext. Voile BA 220:1007004 | Niveau 00 - 03 | 2m x 2.20m | 2
Mur de base:Mur EXE 200- Hach:940290 | Niveau 00 - 03 | Mur EXE 200- Hach | 2
Mur de base:@_Générique - Int. 50 mm:1046158 | Niveau 00 - 03 | @_Générique - Int. 50 mm | 2
5 x Mur de base:Mur EXE 40- Hach:923019 | Niveau 00 - 01 | Mur EXE 40- Hach | 2
@_Int. Simple:@_PP (0.83m x 2.04m):1410527:1 | Niveau 00 - 01
Double (R):1.43m x 2.04m:1409179:1 | Niveau 00 - 01
@_Int. Simple:@_PP (0.73m x 2.04m):1406095:1 | Niveau 00 - 01
Mur de base:Ext. Voile BA 300:1087579 | Niveau 00 - 02 | Pset_DoorCommon - IsExternal: no; Reference: 1.43m x 2.20m; ThermalTransmittance: 3.6886 kg/K/s3; Pset_QuantityTakeOff - Reference: 1.43m x 2.20m
Mur de base:Ext. Voile BA 300:1087579 | Niveau 00 - 02 | 48 x 240 cm | 2
19 x Mur de base:Ext. Mur 250+enduit Rouge:1106182 | Niveau 1 | Type 1 | 2
Double (R):1.73m x 2.10m:1405736:1 | Niveau 00 - 01
Mur de base:Ext. Voile BA 200:1107314:1 | Niveau 00 - 02 | Ext. Voile BA 200 | 2
Mur de base:Ext. Voile BA 200:1107314 | Niveau 00 - 02 | SANS Calpinage | 2
Sol:Dalle béton 200mm:1111592:2 | Niveau 1 - 01 | Dalle béton 200mm | 2
Sol:Dalle béton 200mm:1111592:3 | Niveau 1 - 01 | Dalle béton 200mm | 2
Sol:Dalle béton 200mm:1111592:4 | Niveau 1 - 01 | Dalle béton 200mm | 2
Sol:Dalle béton 200mm:1111592:5 | Niveau 1 - 01 | Dalle béton 200mm | 2
Sol:Dalle béton 200mm:1111592:6 | Niveau 1 - 01 | Dalle béton 200mm | 2
Sol:Dalle béton 200mm:1111592:7 | Niveau 1 - 01 | Dalle béton 200mm | 2
Sol:Dalle béton 200mm:1111592:8 | Niveau 1 - 01 | Dalle béton 200mm | 2
Sol:Dalle béton 200mm:1111592:9 | Niveau 1 - 01 | Dalle béton 200mm | 2
Sol:Dalle béton 200mm:1111592:10 | Niveau 1 - 01 | Dalle béton 200mm | 2
Sol:Dalle béton 200mm:1111592:11 | Niveau 1 - 01 | Dalle béton 200mm | 2
Sol:Dalle béton 200mm:1111592:12 | Niveau 1 - 01 | Dalle béton 200mm | 2
Sol:Dalle béton 200mm:1111592:13 | Niveau 1 - 01 | Dalle béton 200mm | 2
Sol:Dalle béton 200mm:1111592:14 | Niveau 1 - 01 | Dalle béton 200mm | 2
Sol:Dalle béton 200mm:1111592:15 | Niveau 1 - 01 | Dalle béton 200mm | 2
Sol:Dalle béton 200mm:1111592:16 | Niveau 1 - 01 | Dalle béton 200mm | 2
Sol:Dalle béton 200mm:1111592:17 | Niveau 1 - 01 | Dalle béton 200mm | 2
Sol:Dalle béton 200mm:1111592:18 | Niveau 1 - 01 | Dalle béton 200mm | 2
Sol:Dalle béton 200mm:1111592:19 | Niveau 1 - 01 | Dalle béton 200mm | 2
Sol:Dalle béton 200mm:1111592:20 | Niveau 1 - 01 | Dalle béton 200mm | 2
Sol:Dalle béton 200mm:1111592:21 | Niveau 1 - 01 | Dalle béton 200mm | 2
Sol:Dalle béton 200mm:1111592:22 | Niveau 1 - 01 | Dalle béton 200mm | 2
Sol:Dalle béton 200mm:1111592:23 | Niveau 1 - 01 | Dalle béton 200mm | 2
Sol:Dalle béton 200mm:1111592:24 | Niveau 1 - 01 | Dalle béton 200mm | 2
Sol:Dalle béton 200mm:1111592:25 | Niveau 1 - 01 | Dalle béton 200mm | 2
Sol:Dalle béton 200mm:1111592:26 | Niveau 1 - 01 | Dalle béton 200mm | 2
Sol:Dalle béton 200mm:1111592:27 | Niveau 1 - 01 | Dalle béton 200mm | 2
Sol:Dalle béton 200mm:1111592:28 | Niveau 1 - 01 | Dalle béton 200mm | 2
Sol:Dalle béton 200mm:1111592:29 | Niveau 1 - 01 | Dalle béton 200mm | 2
Sol:Dalle béton 200mm:1111592:30 | Niveau 1 - 01 | Dalle béton 200mm | 2
Sol:Dalle béton 200mm:1111592:31 | Niveau 1 - 01 | Dalle béton 200mm | 2
Sol:Dalle béton 200mm:1111592:32 | Niveau 1 - 01 | Dalle béton 200mm | 2
Sol:Dalle béton 200mm:1111592:33 | Niveau 1 - 01 | Dalle béton 200mm | 2
Sol:Dalle béton 200mm:1111592:34 | Niveau 1 - 01 | Dalle béton 200mm | 2
Sol:Dalle béton 200mm:1111592:35 | Niveau 1 - 01 | Dalle béton 200mm | 2
Sol:Dalle béton 200mm:1111592:36 | Niveau 1 - 01 | Dalle béton 200mm | 2
Sol:Dalle béton 200mm:1111592:37 | Niveau 1 - 01 | Dalle béton 200mm | 2
Sol:Dalle béton 200mm:1111592:38 | Niveau 1 - 01 | Dalle béton 200mm | 2
Sol:Dalle béton 200mm:1111592:39 | Niveau 1 - 01 | Dalle béton 200mm | 2
Sol:Dalle béton 200mm:1111592:40 | Niveau 1 - 01 | Dalle béton 200mm | 2
Sol:Dalle béton 200mm:1111592:41 | Niveau 1 - 01 | Dalle béton 200mm | 2
Sol:Dalle béton 200mm:1111592:42 | Niveau 1 - 01 | Dalle béton 200mm | 2
Sol:Dalle béton 200mm:1111592:43 | Niveau 1 - 01 | Dalle béton 200mm | 2
Sol:Dalle béton 200mm:1111592:44 | Niveau 1 - 01 | Dalle béton 200mm | 2
Sol:Dalle béton 200mm:1111592:45 | Niveau 1 - 01 | Dalle béton 200mm | 2
Sol:Dalle béton 200mm:1111592:46 | Niveau 1 - 01 | Dalle béton 200mm | 2
Sol:Dalle béton 200mm:1111592:47 | Niveau 1 - 01 | Dalle béton 200mm | 2
Sol:Dalle béton 200mm:1111592:48 | Niveau 1 - 01 | Dalle béton 200mm | 2
Sol:Dalle béton 200mm:1111592:49 | Niveau 1 - 01 | Dalle béton 200mm | 2
Sol:Dalle béton 200mm:1111592:50 | Niveau 1 - 01 | Dalle béton 200mm | 2
Sol:Dalle béton 200mm:1111592:51 | Niveau 1 - 01 | Dalle béton 200mm | 2
Sol:Dalle béton 200mm:1111592:52 | Niveau 1 - 01 | Dalle béton 200mm | 2
Sol:Dalle béton 200mm:1111592:53 | Niveau 1 - 01 | Dalle béton 200mm | 2
Sol:Dalle béton 200mm:1111592:54 | Niveau 1 - 01 | Dalle béton 200mm | 2
Sol:Dalle béton 200mm:1111592:55 | Niveau 1 - 01 | Dalle béton 200mm | 2
Sol:Dalle béton 200mm:1111592:56 | Niveau 1 - 01 | Dalle béton 200mm | 2
Sol:Dalle béton 200mm:1111592:57 | Niveau 1 - 01 | Dalle béton 200mm | 2
Sol:Dalle béton 200mm:1111592:58 | Niveau 1 - 01 | Dalle béton 200mm | 2
Sol:Dalle béton 200mm:1111592:59 | Niveau 1 - 01 | Dalle béton 200mm | 2
Sol:Dalle béton 200mm:1111592:60 | Niveau 1 - 01 | Dalle béton 200mm | 2
Sol:Dalle béton 200mm:1111592:61 | Niveau 1 - 01 | Dalle béton 200mm | 2
Sol:Dalle béton 200mm:1111592:62 | Niveau 1 - 01 | Dalle béton 200mm | 2
Sol:Dalle béton 200mm:1111592:63 | Niveau 1 - 01 | Dalle béton 200mm | 2
Sol:Dalle béton 200mm:1111592:64 | Niveau 1 - 01 | Dalle béton 200mm | 2
Sol:Dalle béton 200mm:1111592:65 | Niveau 1 - 01 | Dalle béton 200mm | 2
Sol:Dalle béton 200mm:1111592:66 | Niveau 1 - 01 | Dalle béton 200mm | 2
Sol:Dalle béton 200mm:1111592:67 | Niveau 1 - 01 | Dalle béton 200mm | 2
Sol:Dalle béton 200mm:1111592:68 | Niveau 1 - 01 | Dalle béton 200mm | 2
Sol:Dalle béton 200mm:1111592:69 | Niveau 1 - 01 | Dalle béton 200mm | 2
Sol:Dalle béton 200mm:1111592:70 | Niveau 1 - 01 | Dalle béton 200mm | 2
Sol:Dalle béton 200mm:1111592:71 | Niveau 1 - 01 | Dalle béton 200mm | 2
Sol:Dalle béton 200mm:1111592:72 | Niveau 1 - 01 | Dalle béton 200mm | 2
Sol:Dalle béton 200mm:1111592:73 | Niveau 1 - 01 | Dalle béton 200mm | 2
Sol:Dalle béton 200mm:1111592:74 | Niveau 1 - 01 | Dalle béton 200mm | 2
Sol:Dalle béton 200mm:1111592:75 | Niveau 1 - 01 | Dalle béton 200mm | 2
Sol:Dalle béton 200mm:1111592:76 | Niveau 1 - 01 | Dalle béton 200mm | 2
Sol:Dalle béton 200mm:1111592:77 | Niveau 1 - 01 | Dalle béton 200mm | 2
Sol:Dalle béton 200mm:1111592:78 | Niveau 1 - 01 | Dalle béton 200mm | 2
Sol:Dalle béton 200mm:1111592:79 | Niveau 1 - 01 | Dalle béton 200mm | 2
Sol:Dalle béton 200mm:1111592:80 | Niveau 1 - 01 | Dalle béton 200mm | 2
Sol:Dalle béton 200mm:1111592:81 | Niveau 1 - 01 | Dalle béton 200mm | 2
Sol:Dalle béton 200mm:1111592:82 | Niveau 1 - 01 | Dalle béton 200mm | 2
Sol:Dalle béton 200mm:1111592:83 | Niveau 1 - 01 | Dalle béton 200mm | 2
Sol:Dalle béton 200mm:1111592:84 | Niveau 1 - 01 | Dalle béton 200mm | 2
Sol:Dalle béton 200mm:1111592:85 | Niveau 1 - 01 | Dalle béton 200mm | 2
Sol:Dalle béton 200mm:1111592:86 | Niveau 1 - 01 | Dalle béton 200mm | 2
Sol:Dalle béton 200mm:1111592:87 | Niveau 1 - 01 | Dalle béton 200mm | 2
Sol:Dalle béton 200mm:1111592:88 | Niveau 1 - 01 | Dalle béton 200mm | 2
Sol:Dalle béton 200mm:1111592:89 | Niveau 1 - 01 | Dalle béton 200mm | 2
Sol:Dalle béton 200mm:1111592:90 | Niveau 1 - 01 | Dalle béton 200mm | 2
Sol:Dalle béton 200mm:1111592:91 | Niveau 1 - 01 | Dalle béton 200mm | 2
Sol:Dalle béton 200mm:1111592:92 | Niveau 1 - 01 | Dalle béton 200mm | 2
Sol:Dalle béton 200mm:1111592:93 | Niveau 1 - 01 | Dalle béton 200mm | 2
Sol:Dalle béton 200mm:1111592:94 | Niveau 1 - 01 | Dalle béton 200mm | 2
Sol:Dalle béton 200mm:1111592:95 | Niveau 1 - 01 | Dalle béton 200mm | 2
Sol:Dalle béton 200mm:1111592:96 | Niveau 1 - 01 | Dalle béton 200mm | 2
Sol:Dalle béton 200mm:1111592:97 | Niveau 1 - 01 | Dalle béton 200mm | 2
Sol:Dalle béton 200mm:1111592:98 | Niveau 1 - 01 | Dalle béton 200mm | 2
Sol:Dalle béton 200mm:1111592:99 | Niveau 1 - 01 | Dalle béton 200mm | 2
Sol:Dalle béton 200mm:1111592:100 | Niveau 1 - 01 | Dalle béton 200mm | 2
Sol:Dalle béton 200mm:1111592:101 | Niveau 1 - 01 | Dalle béton 200mm | 2
Sol:Dalle béton 200mm:1111592:102 | Niveau 1 - 01 | Dalle béton 200mm | 2
Sol:Dalle béton 200mm:1111592:103 | Niveau 1 - 01 | Dalle béton 200mm | 2
Sol:Dalle béton 200mm:1111592:104 | Niveau 1 - 01 | Dalle béton 200mm | 2
Sol:Dalle béton 200mm:1111592:105 | Niveau 1 - 01 | Dalle béton 200mm | 2
Sol:Dalle béton 200mm:1111592:106 | Niveau 1 - 01 | Dalle béton 200mm | 2
Sol:Dalle béton 200mm:1111592:107 | Niveau 1 - 01 | Dalle béton 200mm | 2
Sol:Dalle béton 200mm:1111592:108 | Niveau 1 - 01 | Dalle béton 200mm | 2
Sol:Dalle béton 200mm:1111592:109 | Niveau 1 - 01 | Dalle béton 200mm | 2
Sol:Dalle béton 200mm:1111592:110 | Niveau 1 - 01 | Dalle béton 200mm | 2
Sol:Dalle béton 200mm:1111592:111 | Niveau 1 - 01 | Dalle béton 200mm | 2
Sol:Dalle béton 200mm:1111592:112 | Niveau 1 - 01 | Dalle béton 200mm | 2
Sol:Dalle béton 200mm:1111592:113 | Niveau 1 - 01 | Dalle béton 200mm | 2
Sol:Dalle béton 200mm:1111592:114 | Niveau 1 - 01 | Dalle béton 200mm | 2
Sol:Dalle béton 200mm:1111592:115 | Niveau 1 - 01 | Dalle béton 200mm | 2
Sol:Dalle béton 200mm:1111592:116 | Niveau 1 - 01 | Dalle béton 200mm | 2
Sol:Dalle béton 200mm:1111592:117 | Niveau 1 - 01 | Dalle béton 200mm | 2
Sol:Dalle béton 200mm:1111592:118 | Niveau 1 - 01 | Dalle béton 200mm | 2
Sol:Dalle béton 200mm:1111592:119 | Niveau 1 - 01 | Dalle béton 200mm | 2
Sol:Dalle béton 200mm:1111592:120 | Niveau 1 - 01 | Dalle béton 200mm | 2
Sol:gazon 50:1120371:2 | Niveau 00 - 02 | gazon 50 | 2
@_Int. Simple:@_PP (0.63m x 2.04m):1405199:1 | Niveau 00 - 01
@_Int. Simple:@_PP (0.63m x 2.04m):1405150:1 | Niveau 00 - 01
@_Int. Simple:@_PP (0.63m x 2.04m):1405116:1 | Niveau 00 - 01
@_Int. Simple:@_PP (0.63m x 2.04m):1405068:1 | Niveau 00 - 01
@_Int. Simple:@_PP (0.63m x 2.04m):1404965:1 | Niveau 00 - 01
@_Int. Simple:@_PP (0.83m x 2.04m):1397800:1 | Niveau 00 - 02
Double (R):1.43m x 2.04m:1397711:1 | Niveau 00 - 02
Fenêtre type 1:48 x 240 cm:1396670:1 | Niveau 00 - 02
Fenêtre type 1:48 x 240 cm:1396241:1 | Niveau 00 - 02
@_Int. Simple:@_PP (0.93m x 2.04m):1490559:1 | Niveau 00 - 02
@_Int. Simple:@_PP (0.93m x 2.04m):1400321:1 | Niveau 00 - 02
@_Int. Simple:@_PP (0.63m x 2.04m):1404919:1 | Niveau 00 - 01
Sol:@_Sol-Générique - 200 mm:1139481:2 | Niveau 3 | @_Sol-Générique - 200 mm | 2
@_Int. Simple:@_PP (0.63m x 2.04m):1404851:1 | Niveau 00 - 01
@_Int. Simple:@_PP (0.63m x 2.04m):1404769:1 | Niveau 00 - 01
Mur de base:@_Générique - Int. 150 mm:1231314 | Niveau 2 | Pset_DoorCommon - IsExternal: no; Reference: 1.43m x 2.04m; ThermalTransmittance: 3.7021 kg/K/s3; Pset_QuantityTakeOff - Reference: 1.43m x 2.04m
2 x Mur de base:@_Générique - Int. 120 mm:1250367 | Niveau 1 | @_PP (0.73m x 2.04m) | 2
Mur de base:@_Générique - Int. 150 mm:1260660 | Niveau 00 - 01 | 1.43m x 2.04m | 2
@_Int. Simple:@_PP (0.73m x 2.04m):1401716:1 | Niveau 00 - 01
Mur de base:Ext. Voile BA 150:1309028 | Niveau 00 - 01 | 0.93m x 2.10m | 2
3 x  | Niveau 1 - 03
Mur de base:Mur EXE 40- Hach:1334769 | Niveau 00 - 01 | Type A | 2
Mur de base:Mur EXE 40- Hach:1335925:1 | Niveau 00 | Mur EXE 40- Hach | 2
@_Int. Simple:@_PP (0.73m x 2.04m):1401739:1 | Niveau 00 - 01
2 x Mur de base:Mur EXE 40- Hach:1335925 | Niveau 00 | 120 x 125cm | 2
Mur de base:Mur EXE 40- Hach:1335925 | Niveau 00 | 200 x 220cm | 2
3 x Mur de base:Mur EXE 40- Hach:923019 | Niveau 00 | Mur EXE 40- Hach | 2
Mur de base:Ext. Voile BA 200:1336990 | Niveau 00 - 02 | @_PP (0.83m x 2.04m) | 2
Mur de base:Mur EXE 40- Hach:1338256 | Niveau 00 - 02 | Pset_DoorCommon - IsExternal: no; Reference: 1.43m x 2.20m; ThermalTransmittance: 3.6886 kg/K/s3; Pset_QuantityTakeOff - Reference: 1.43m x 2.20m
2 x Mur de base:Mur EXE 40- Hach:1338256 | Niveau 00 - 02 | 120 x 240 cm | 2
Mur de base:Mur EXE 40- Hach:1338256 | Niveau 00 - 02 | 80 x 240 cm | 2
4 x Mur de base:Mur EXE 40- Hach:1338256 | Niveau 00 - 02 | 48 x 240 cm | 2
3 x Mur de base:Mur EXE 40- Hach:1338328 | Niveau 00 | 48 x 240 cm | 2
Mur de base:Ext. Voile BA 200:745683 | Niveau 00 - 01 | Ext. Voile BA 200 | 2
Double (R):1.23m x 2.04m:1406318:1 | Niveau 00 - 01
Mur de base:Mur EXE 530- Hach 2 faces:1349059 | Niveau 00 - 02 | 200 x 220cm | 2
Mur de base:Mur EXE 530- Hach 2 faces:1349258 | Niveau 00 - 02 | 200 x 220cm | 2
Mur de base:Mur EXE 5350- Hach 2 faces:1349456 | Niveau 00 - 02 | 200 x 220cm | 2
Mur de base:@_Générique - Int. 70 mm:1358108 | Niveau 00 - 02 | 156 x 50cm | 2
Fenêtre type 1:156 x 50cm:1358811:1 | Niveau 00 - 02
@_Int. Simple:@_PP (0.73m x 2.04m):1358109:1 | Niveau 00 - 02
Fenêtre type 1:75 x 180cm:1357522:1 | Niveau 00 - 02
Fenêtre type 1:280 x 245 cm:1357347:1 | Niveau 00 - 02
Fenêtre type 1:200 x 220cm:1352954:1 | Niveau 00 - 02
Mur de base:@_Générique - Int. 150 mm:1369730 | Niveau 1 - 03 | SANS Calpinage | 2
@_Int. Simple:@_PP (0.73m x 2.04m):1350262:1 | Niveau 00 - 02
Placard pliante:Placard pliante 100:1350602:1 | Niveau 00 - 02
Placard pliante:Placard pliante 110:1351901:1 | Niveau 00 - 02
Fenêtre type 1:120 x 125cm:1348994:1 | Niveau 00 - 02
Fenêtre type 1:120 x 125cm:1348661:1 | Niveau 00 - 02
Fenêtre type 1:48 x 240 cm:1347128:1 | Niveau 00 - 02
Fenêtre type 1:48 x 240 cm:1344158:1 | Niveau 00 - 02
Mur de base:Mur EXE 40- Hach:1390417 | Niveau 00 - 01 | Pset_QuantityTakeOff - Reference: 200 x 160; Pset_WindowCommon - IsExternal: yes; Reference: 200 x 160
Mur de base:Mur EXE 40- Hach:1392263 | Niveau 00 - 01 | Pset_QuantityTakeOff - Reference: 90 x 60cm; Pset_WindowCommon - IsExternal: yes; Reference: 90 x 60cm
2 x Mur de base:Ext. Voile BA 150:1394032 | Niveau 00 - 01 | @_PP (0.73m x 2.04m) | 2
Mur de base:Ext. Voile BA 300:1395855 | Niveau 00 - 02 | Pset_DoorCommon - IsExternal: no; Reference: 1.43m x 2.20m; ThermalTransmittance: 3.6886 kg/K/s3; Pset_QuantityTakeOff - Reference: 1.43m x 2.20m
Mur de base:Ext. Voile BA 300:1395855 | Niveau 00 - 02 | 48 x 240 cm | 2
Mur de base:Ext. Voile BA 300:1395938 | Niveau 00 - 02 | Pset_DoorCommon - IsExternal: no; Reference: 1.43m x 2.20m; ThermalTransmittance: 3.6886 kg/K/s3; Pset_QuantityTakeOff - Reference: 1.43m x 2.20m
Mur de base:Ext. Voile BA 300:1395938 | Niveau 00 - 02 | 48 x 240 cm | 2
Mur de base:Ext. Voile BA 300:1396078 | Niveau 00 - 02 | Pset_DoorCommon - IsExternal: no; Reference: 1.43m x 2.20m; ThermalTransmittance: 3.6886 kg/K/s3; Pset_QuantityTakeOff - Reference: 1.43m x 2.20m
Fenêtre type 1:48 x 240 cm:1344157:1 | Niveau 00 - 02
Mur de base:Ext. Voile BA 300:1396078 | Niveau 00 - 02 | 48 x 240 cm | 2
Mur de base:Ext. Voile BA 300:1396392 | Niveau 00 - 02 | Pset_DoorCommon - IsExternal: no; Reference: 1.43m x 2.20m; ThermalTransmittance: 3.6886 kg/K/s3; Pset_QuantityTakeOff - Reference: 1.43m x 2.20m
Mur de base:Ext. Voile BA 300:1396392 | Niveau 00 - 02 | 48 x 240 cm | 2
Mur de base:Ext. Voile BA 300:1396593:1 | Niveau 00 - 02 | Ext. Voile BA 300 | 2
Mur de base:@_Générique - Int. 70 mm:1410790 | Niveau 00 - 01 | PRT_COL_207*100 | 2
Mur de base:@_Générique - Int. 150 mm:169310 | Niveau 00 - 01 | @_Générique - Int. 150 mm | 2
Fenêtre type 1:550 x 245 cm:1344159:1 | Niveau 00 - 02
Mur de base:Ext. Voile BA 350:1492740 | Niveau 00 - 02 | 156 x 50cm | 2
Mur de base:Mur EXE 5350- Hach 2 faces:1494390 | Niveau 00 - 02 | 200 x 220cm | 2
Mur de base:@_Générique - Int. 100 mm:1496479 | Niveau 00 - 02 | 156 x 50cm | 2
Mur de base:Ext. Voile BA 220:1496675 | Niveau 00 - 02 | 156 x 50cm | 2
Mur de base:@_Générique - Int. 150 mm:1512167 | Niveau 2 | Pset_DoorCommon - IsExternal: no; Reference: 1.63m x 2.04m; ThermalTransmittance: 3.7021 kg/K/s3; Pset_QuantityTakeOff - Reference: 1.63m x 2.04m
Sol:Dalle béton 250mm:1518835:2 | Niveau 3 - 01 | Dalle béton 250mm | 2
Fenêtre type 1:48 x 240 cm:1341198:1 | Niveau 00 - 02
Fenêtre type 1:120 x 240 cm:1340778:1 | Niveau 00 - 02
Fenêtre type 1:120 x 240 cm:1340367:1 | Niveau 00 - 02
@_Int. Simple:@_PP (0.73m x 2.04m):1418454:1 | Niveau 00 - 02
Mur de base:Ext. Voile BA 300:1528822:1 | Niveau 00 - 02 | Ext. Voile BA 300 | 2
Mur de base:@_Générique - Int. 200 mm:1531084 | Niveau 00 - 01 | Pset_DoorCommon - IsExternal: no; Reference: @_PP (0.93m x 2.25); Pset_QuantityTakeOff - Reference: @_PP (0.93m x 2.25)
Placard pliante:Placard pliante 42:1493985:1 | Niveau 00 - 02
3 x Mur de base:Ext. Voile BA 250:970849 | Niveau 00 - 01
3 x Mur de base:Ext. Voile BA 250:970850 | Niveau 00 - 01
3 x Mur de base:Ext. Voile BA 250:970852 | Niveau 00 - 01
6 x Mur de base:Ext. Voile BA 250:970853 | Niveau 00 - 01
5 x Mur de base:Ext. Voile BA 250:970854 | Niveau 00 - 01
Fenêtre type 1:70 x 160cm:1386518:1 | Niveau 00 - 01
Fenêtre type 1:70 x 160cm:1386597:1 | Niveau 00 - 01
Mur de base:Ext. Voile BA 250:970855 | Niveau 00 - 01
Mur de base:Ext. Voile BA 250:970856 | Niveau 00 - 01
Fenêtre type 1:90 x 60cm:1386851:1 | Niveau 00 - 01
2 x Mur de base:Ext. Voile BA 250:970858 | Niveau 00 - 01
Mur de base:Mur Blanc 150- isolation 50:970859 | Niveau 00 - 01
@_Int. Simple:@_PP (0.93m x 2.25):1373748:1 | Niveau 00 - 01
Double (R):1.73m x 2.9m:1372745:1 | Niveau 00 - 01
2 x Mur de base:Ext. Voile BA 250:970873 | Niveau 00 - 01
Fenêtre type 1:1.9000 x 145cm:1372431:1 | Niveau 00 - 01
Mur de base:@_Générique - Int. 200 mm:970874 | Niveau 00 - 01
Mur de base:Ext. Voile BA 250:970876 | Niveau 00 - 01
Fenêtre type 1:282 x 125 cm:1361839:1 | Niveau 00 - 01
@_Int. Simple:@_PP (0.93m x 2.25):1409657:1 | Niveau 00 - 01
@_Int. Simple:@_PP (0.93m x 2.25):1409742:1 | Niveau 00 - 01
@_Int. Simple:@_PP (0.93m x 2.25):1409800:1 | Niveau 00 - 01
@_Int. Simple:@_PP (0.93m x 2.25):1409892:1 | Niveau 00 - 01
@_Int. Simple:@_PP (0.93m x 2.25):1409947:1 | Niveau 00 - 01
@_Int. Simple:@_PP (0.93m x 2.25):1410001:1 | Niveau 00 - 01
@_Int. Simple:@_PP (0.93m x 2.25):1410127:1 | Niveau 00 - 01
@_Int. Simple:@_PP (0.93m x 2.25):1410189:1 | Niveau 00 - 01
@_Int. Simple:@_PP (0.93m x 2.04m):1410215:1 | Niveau 00 - 01
Ouverture en rectangle:Ouverture110x210:1408471:1 | Niveau 00 - 01
Double (R):1.63m x 2.04m:1408130:1 | Niveau 00 - 01
Double (R):1.63m x 2.04m:1408237:1 | Niveau 00 - 01
Double (R):1.63m x 2.04m:1408029:1 | Niveau 00 - 01
Double (R):1.63m x 2.04m:1408282:1 | Niveau 00 - 01
@_Int. Simple:@_PP (0.93m x 2.25):1411926:1 | Niveau 00 - 01
@_Int. Simple:@_PP (0.83m x 2.04m):1408859:1 | Niveau 00 - 01
@_Int. Simple:@_PP (0.83m x 2.04m):1409023:1 | Niveau 00 - 01
Double (R):1.63m x 2.04m:1414296:1 | Niveau 00 - 01
Double (R):1.63m x 2.04m:1408812:1 | Niveau 00 - 01
@_Int. Simple:@_PP (0.83m x 2.04m):1406522:1 | Niveau 00 - 01
Double (R):1.73m x 2.10m:1406223:1 | Niveau 00 - 01
@_Int. Simple:@_PP (0.73m x 2.04m):1407017:1 | Niveau 00 - 01
Double (R):1.63m x 2.04m:1397896:1 | Niveau 00 - 02
@_Int. Simple:@_PP (0.93m x 2.25):1411562:1 | Niveau 00 - 01
@_Int. Simple:@_PP (0.93m x 2.25):1411536:1 | Niveau 00 - 01
@_Int. Simple:@_PP (0.83m x 2.04m):1411509:1 | Niveau 00 - 01
@_Int. Simple:@_PP (0.93m x 2.25):1415418:1 | Niveau 00 - 01
@_Int. Simple:@_PP (0.83m x 2.04m):1414616:1 | Niveau 00 - 01
@_Int. Simple:@_PP (0.83m x 2.04m):1414568:1 | Niveau 00 - 01
@_Int. Simple:@_PP (0.73m x 2.04m):1407285:1 | Niveau 00 - 01
@_Int. Simple:@_PP (0.73m x 2.04m):1407251:1 | Niveau 00 - 01
Double (R):1.63m x 2.04m:1397982:1 | Niveau 00 - 02
@_Int. Simple:@_PP (0.83m x 2.04m):1400419:1 | Niveau 00 - 02
@_Int. Simple:@_PP (0.83m x 2.04m):1401519:1 | Niveau 00 - 01
Fenêtre type 1:115 x 155 cm:1135905:1 | Niveau 1
Fenêtre type 1:115 x 155 cm:1136241:1 | Niveau 1
Fenêtre type 1:115 x 155 cm:1136257:1 | Niveau 1
Fenêtre type 1:115 x 155 cm:1136273:1 | Niveau 1
Fenêtre type 1:115 x 155 cm:1136295:1 | Niveau 1
Fenêtre type 1:115 x 155 cm:1136311:1 | Niveau 1
Fenêtre type 1:115 x 155 cm:1136327:1 | Niveau 1
Fenêtre type 1:115 x 155 cm:1136344:1 | Niveau 1
Fenêtre type 1:115 x 155 cm:1136476:1 | Niveau 1
Fenêtre type 1:115 x 155 cm:1136478:1 | Niveau 1
Fenêtre type 1:115 x 155 cm:1136495:1 | Niveau 1
Fenêtre type 1:115 x 155 cm:1136497:1 | Niveau 1
Fenêtre type 1:115 x 155 cm:1130225:1 | Niveau 1
Fenêtre type 1:115 x 155 cm:1130165:1 | Niveau 1
Fenêtre type 1:115 x 155 cm:1131023:1 | Niveau 1
Fenêtre type 1:115 x 155 cm:1131024:1 | Niveau 1
Fenêtre type 1:115 x 155 cm:1131044:1 | Niveau 1
Fenêtre type 1:115 x 155 cm:1131045:1 | Niveau 1
Fenêtre type 1:115 x 155 cm:1131065:1 | Niveau 1
Fenêtre type 1:115 x 155 cm:1131066:1 | Niveau 1
Fenêtre type 1:115 x 155 cm:1131086:1 | Niveau 1
Fenêtre type 1:115 x 155 cm:1131087:1 | Niveau 1
Fenêtre type 1:115 x 155 cm:1131107:1 | Niveau 1
Fenêtre type 1:115 x 155 cm:1131108:1 | Niveau 1
Fenêtre type 1:115 x 155 cm:1131130:1 | Niveau 1
Fenêtre type 1:115 x 155 cm:1131131:1 | Niveau 1
@_Int. Simple:@_PP (0.93m x 2.04m):1291137:1 | Niveau 1
@_Int. Simple:@_PP (0.83m x 2.04m):1273015:1 | Niveau 1
@_Int. Simple:@_PP (0.83m x 2.04m):1272451:1 | Niveau 1
@_Int. Simple:@_PP (0.73m x 2.04m):1447539:1 | Niveau 1
@_Int. Simple:@_PP (0.73m x 2.04m):1268579:1 | Niveau 1
@_Int. Simple:@_PP (0.73m x 2.04m):1268599:1 | Niveau 1
@_Int. Simple:@_PP (0.73m x 2.04m):1272618:1 | Niveau 1
Double (R):1.43m x 2.04m:1269104:1 | Niveau 1
@_Int. Simple:@_PP (0.73m x 2.04m):1269008:1 | Niveau 1
@_Int. Simple:@_PP (0.83m x 2.04m):1290945:1 | Niveau 1
Double (R):1.43m x 2.04m:1269138:1 | Niveau 1
Fenêtre type 1:115 x 155 cm:1135097:1 | Niveau 2
Fenêtre type 1:115 x 155 cm:1135551:1 | Niveau 2
Fenêtre type 1:115 x 155 cm:1135632:1 | Niveau 2
Fenêtre type 1:115 x 155 cm:1135634:1 | Niveau 2
Fenêtre type 1:115 x 155 cm:1135655:1 | Niveau 2
Fenêtre type 1:115 x 155 cm:1135657:1 | Niveau 2
Fenêtre type 1:115 x 155 cm:1135677:1 | Niveau 2
Fenêtre type 1:115 x 155 cm:1135679:1 | Niveau 2
Fenêtre type 1:115 x 155 cm:1135696:1 | Niveau 2
Fenêtre type 1:115 x 155 cm:1135698:1 | Niveau 2
Fenêtre type 1:115 x 155 cm:1135967:1 | Niveau 2
Fenêtre type 1:115 x 155 cm:1136242:1 | Niveau 2
Fenêtre type 1:115 x 155 cm:1136258:1 | Niveau 2
Fenêtre type 1:115 x 155 cm:1136274:1 | Niveau 2
Fenêtre type 1:115 x 155 cm:1136296:1 | Niveau 2
Fenêtre type 1:115 x 155 cm:1136312:1 | Niveau 2
Fenêtre type 1:115 x 155 cm:1136328:1 | Niveau 2
Fenêtre type 1:115 x 155 cm:1136345:1 | Niveau 2
Fenêtre type 1:115 x 155 cm:1136477:1 | Niveau 2
Fenêtre type 1:115 x 155 cm:1136479:1 | Niveau 2
Fenêtre type 1:115 x 155 cm:1136496:1 | Niveau 2
Fenêtre type 1:115 x 155 cm:1136498:1 | Niveau 2
Fenêtre type 1:115 x 155 cm:1130411:1 | Niveau 2
Fenêtre type 1:115 x 155 cm:1130313:1 | Niveau 2
Fenêtre type 1:115 x 155 cm:1131025:1 | Niveau 2
Fenêtre type 1:115 x 155 cm:1131026:1 | Niveau 2
Fenêtre type 1:115 x 155 cm:1131046:1 | Niveau 2
Fenêtre type 1:115 x 155 cm:1131047:1 | Niveau 2
Fenêtre type 1:115 x 155 cm:1131067:1 | Niveau 2
Fenêtre type 1:115 x 155 cm:1131068:1 | Niveau 2
Fenêtre type 1:115 x 155 cm:1131088:1 | Niveau 2
Fenêtre type 1:115 x 155 cm:1131089:1 | Niveau 2
Fenêtre type 1:115 x 155 cm:1131109:1 | Niveau 2
Fenêtre type 1:115 x 155 cm:1131110:1 | Niveau 2
Fenêtre type 1:115 x 155 cm:1131132:1 | Niveau 2
Fenêtre type 1:115 x 155 cm:1131133:1 | Niveau 2
Fenêtre type 1:115 x 155 cm:1079149:1 | Niveau 2
Fenêtre type 1:115 x 155 cm:1081262:1 | Niveau 2
Fenêtre type 1:115 x 155 cm:1081296:1 | Niveau 2
Fenêtre type 1:115 x 155 cm:1081312:1 | Niveau 2
Fenêtre type 1:115 x 155 cm:1081330:1 | Niveau 2
Fenêtre type 1:115 x 155 cm:1081363:1 | Niveau 2
Fenêtre type 1:115 x 155 cm:1081399:1 | Niveau 2
Fenêtre type 1:115 x 155 cm:1081416:1 | Niveau 2
Fenêtre type 1:115 x 155 cm:1081448:1 | Niveau 2
Fenêtre type 1:115 x 155 cm:1081480:1 | Niveau 2
Tierce 160:1.10m x 2.04m:1233400:1 | Niveau 2
Tierce 160:1.10m x 2.04m:1233445:1 | Niveau 2
@_Int. Simple:@_PP (0.83m x 2.04m):1535016:1 | Niveau 2
Double (R):1.43m x 2.04m:1231099:1 | Niveau 2
Double (R):1.43m x 2.04m:1231157:1 | Niveau 2
Porte métal:@_PP (1.03m x 1.8m):1200092:1 | Niveau 3 - 01
Fenêtre type 1:32 x 105 cm:1101789:1 | Niveau 1 - 03
Fenêtre type 1:32 x 105 cm:1101346:1 | Niveau 1 - 03
Fenêtre type 1:32 x 105 cm:1101503:1 | Niveau 1 - 03
Tierce 160:1.10m x 2.04m:1226052:1 | Niveau 2
Double (R):1.63m x 2.04m:1226216:1 | Niveau 2
Ouverture en rectangle:Ouverture100x200:1228006:1 | Niveau 2
Ouverture en rectangle:Ouverture100x200:1228117:1 | Niveau 2
Tierce 160:1.10m x 2.04m:1227734:1 | Niveau 2
Ouverture en rectangle:Ouverture100x200:1230979:1 | Niveau 2
Ouverture en rectangle:Ouverture100x200:1230978:1 | Niveau 2
Tierce 160:1.10m x 2.04m:1232357:1 | Niveau 2
Tierce 160:1.10m x 2.04m:1232378:1 | Niveau 2
Tierce 160:1.10m x 2.04m:1232238:1 | Niveau 2
Double (R):1.63m x 2.04m:1232284:1 | Niveau 2
Double (R):1.63m x 2.04m:1213401:1 | Niveau 2
Tierce 160:1.10m x 2.04m:1213566:1 | Niveau 2
Tierce 160:1.10m x 2.04m:1232191:1 | Niveau 2
Tierce 160:1.10m x 2.04m:1232216:1 | Niveau 2
Tierce 160:1.10m x 2.04m:1232153:1 | Niveau 2
Tierce 160:1.10m x 2.04m:1232174:1 | Niveau 2
@_Int. Simple:@_PP (0.83m x 2.04m):1292449:1 | Niveau 2
Double (R):1.73m x 2.9m:1415340:1 | Niveau 00 - 01
@_Int. Simple:@_PP (1.03m x 1.8m):1408319:1 | Niveau 00 - 01
Double (R):1.73m x 2.10m:1406038:1 | Niveau 00 - 01
Ouverture en rectangle:Ouverture 90x210:1523056:1 | Niveau 00 - 01
@_Int. Simple:@_PP (0.63m x 2.04m):1412120:1 | Niveau 00 - 01
@_Int. Simple:@_PP (0.63m x 2.04m):1412204:1 | Niveau 00 - 01
@_Int. Simple:@_PP (0.63m x 2.04m):1412158:1 | Niveau 00 - 01
@_Int. Simple:@_PP (0.63m x 2.04m):1415135:1 | Niveau 00 - 01
@_Int. Simple:@_PP (0.63m x 2.04m):1415207:1 | Niveau 00 - 01
Double (R):1.23m x 2.04m:1094072:1 | Niveau 00 - 02
Double (R):1.63m x 2.04m:1398069:1 | Niveau 00 - 02
Double (R):1.73m x 2.10m:1398163:1 | Niveau 00 - 02
Mur de base:@_Générique - Int. 200 mm:976022 | SOUS SOL
Mur de base:@_Générique - Int. 200 mm:976023 | SOUS SOL
@_Int. Simple:@_PP (0.93m x 2.04m):1100691:1 | SOUS SOL
Mur de base:@_Générique - Int. 150 mm:1007285 | Niveau 00 - 03
Mur de base:@_Générique - Int. 50 mm:1008247 | Niveau 00 - 03
Mur de base:@_Générique - Int. 50 mm:1008272 | Niveau 00 - 03
Fenêtre type 1:115 x 155 cm:1078586:1 | Niveau 1
Fenêtre type 1:115 x 155 cm:1081261:1 | Niveau 1
Fenêtre type 1:115 x 155 cm:1081279:1 | Niveau 1
Fenêtre type 1:115 x 155 cm:1081295:1 | Niveau 1
Fenêtre type 1:115 x 155 cm:1081311:1 | Niveau 1
Fenêtre type 1:115 x 155 cm:1081329:1 | Niveau 1
Fenêtre type 1:115 x 155 cm:1081362:1 | Niveau 1
Fenêtre type 1:115 x 155 cm:1081398:1 | Niveau 1
Fenêtre type 1:115 x 155 cm:1081415:1 | Niveau 1
Fenêtre type 1:115 x 155 cm:1081447:1 | Niveau 1
Fenêtre type 1:115 x 155 cm:1081479:1 | Niveau 1
Fenêtre type 1:80 x 240 cm:1340913:1 | Niveau 00 - 02
Double (R):1.23m x 2.04m:1094404:1 | SOUS SOL
@_Int. Simple:@_PP (0.73m x 2.04m):1095932:1 | SOUS SOL
@_Int. Simple:@_PP (0.93m x 2.04m):1100895:1 | SOUS SOL
Fenêtre type 1:32 x 105 cm:1101788:1 | Niveau 00 - 01
Fenêtre type 1:115 x 155 cm:1135189:1 | Niveau 1
Fenêtre type 1:115 x 155 cm:1135552:1 | Niveau 1
Fenêtre type 1:115 x 155 cm:1135633:1 | Niveau 1
Fenêtre type 1:115 x 155 cm:1135635:1 | Niveau 1
Fenêtre type 1:115 x 155 cm:1135656:1 | Niveau 1
Fenêtre type 1:115 x 155 cm:1135658:1 | Niveau 1
Fenêtre type 1:115 x 155 cm:1135678:1 | Niveau 1
Fenêtre type 1:115 x 155 cm:1135680:1 | Niveau 1
Fenêtre type 1:115 x 155 cm:1135697:1 | Niveau 1
Fenêtre type 1:115 x 155 cm:1135699:1 | Niveau 1
@_Int. Simple:@_PP (0.83m x 2.04m):1225978:1 | Niveau 2
Tierce 160:1.10m x 2.04m:1232337:1 | Niveau 2
Double Vitrée :1.63m x 2.04m:1223007:1 | Niveau 2
@_Int. Simple:@_PP (0.93m x 2.04m):1211804:1 | Niveau 3 - 01
Ouverture en rectangle:Ouverture100x200:1215167:1 | Niveau 2
Ouverture en rectangle:Ouverture100x200:1221558:1 | Niveau 2
@_Int. Simple:@_PP (0.83m x 2.04m):1225907:1 | Niveau 2
@_Int. Simple:@_PP (0.83m x 2.04m):1228291:1 | Niveau 2
Ouverture en rectangle:Ouverture100x200:1231056:1 | Niveau 2
Ouverture en rectangle:Ouverture100x200:1231057:1 | Niveau 2
Tierce 160:1.10m x 2.04m:1231607:1 | Niveau 2
Tierce 160:1.10m x 2.04m:1231657:1 | Niveau 2
@_Int. Simple:@_PP (0.93m x 2.04m):1232404:1 | Niveau 2
Double (R):1.63m x 2.04m:1232490:1 | Niveau 2
@_Int. Simple:@_PP (0.93m x 2.04m):1272880:1 | Niveau 1
Tierce 160:1.10m x 2.04m:1268904:1 | Niveau 1
@_Int. Simple:@_PP (0.93m x 2.04m):1265986:1 | Niveau 1
@_Int. Simple:@_PP (0.93m x 2.04m):1266033:1 | Niveau 1
@_Int. Simple:@_PP (0.93m x 2.04m):1291917:1 | Niveau 1
Tierce 160:1.10m x 2.04m:1275286:1 | Niveau 1
@_Int. Simple:@_PP (0.73m x 2.04m):1285083:1 | Niveau 1
@_Int. Simple:@_PP (0.63m x 2.04m):1282573:1 | Niveau 1
@_Int. Simple:@_PP (0.63m x 2.04m):1282698:1 | Niveau 1
@_Int. Simple:@_PP (0.63m x 2.04m):1282734:1 | Niveau 1
@_Int. Simple:@_PP (0.63m x 2.04m):1293949:1 | Niveau 1
@_Int. Simple:@_PP (0.63m x 2.04m):1294012:1 | Niveau 1
@_Int. Simple:@_PP (0.63m x 2.04m):1294067:1 | Niveau 1
@_Int. Simple:@_PP (0.63m x 2.04m):1294088:1 | Niveau 1
Tierce 160:1.10m x 2.04m:1264427:1 | Niveau 1
Double (R):1.63m x 2.04m:1273372:1 | Niveau 1
@_Int. Simple:@_PP (0.83m x 2.04m):1272736:1 | Niveau 1
Double (R):1.63m x 2.04m:1265850:1 | Niveau 1
Double (R):1.43m x 2.04m:1265112:1 | Niveau 1
Tierce 160:1.10m x 2.04m:1265248:1 | Niveau 1
@_Int. Simple:@_PP (0.73m x 2.04m):1265753:1 | Niveau 1
@_Int. Simple:@_PP (0.73m x 2.04m):1406932:1 | Niveau 00 - 01
Tierce 160:1.10m x 2.04m:1269261:1 | Niveau 1
Tierce 160:1.10m x 2.04m:1269283:1 | Niveau 1
Ouverture en rectangle:Ouverture 85x210:1272475:1 | Niveau 1
@_Int. Simple:@_PP (0.73m x 2.04m):1272663:1 | Niveau 1
@_Int. Simple:@_PP (0.73m x 2.04m):1272706:1 | Niveau 1
Tierce 160:1.10m x 2.04m:1273140:1 | Niveau 1
Tierce 160:1.10m x 2.04m:1273312:1 | Niveau 1
@_Int. Simple:@_PP (0.73m x 2.04m):1273967:1 | Niveau 1
@_Int. Simple:@_PP (0.73m x 2.04m):1274033:1 | Niveau 1
Double (R):1.63m x 2.04m:1275222:1 | Niveau 1
Tierce 160:1.10m x 2.04m:1275268:1 | Niveau 1
Double (R):1.63m x 2.04m:1281705:1 | Niveau 1
@_Int. Simple:@_PP (0.63m x 2.04m):1293008:1 | Niveau 2
@_Int. Simple:@_PP (0.63m x 2.04m):1293082:1 | Niveau 2
@_Int. Simple:@_PP (0.63m x 2.04m):1293188:1 | Niveau 2
@_Int. Simple:@_PP (0.63m x 2.04m):1294376:1 | Niveau 2
@_Int. Simple:@_PP (0.63m x 2.04m):1294378:1 | Niveau 2
@_Int. Simple:@_PP (0.63m x 2.04m):1294380:1 | Niveau 2
@_Int. Simple:@_PP (0.63m x 2.04m):1294382:1 | Niveau 2
5 x Mur de base:Ext. Voile BA 200:1298526 | Niveau 1 - 01
5 x Mur de base:Ext. Voile BA 200:1300879 | Niveau 1 - 01
3 x Mur de base:Ext. Voile BA 200:1308132 | Niveau 1 - 01
Double (R):1.73m x 2.9m:1414511:1 | Niveau 00 - 01
@_Int. Simple:@_PP (0.83m x 2.04m):1499070:1 | Niveau 00 - 01
2 x Mur de base:Ext. Voile BA 250:1333235 | Niveau 00 - 01
@_Int. Simple:@_PP (0.73m x 2.04m):1350398:1 | Niveau 00 - 02
@_Int. Simple:@_PP (0.63m x 2.04m):1350456:1 | Niveau 00 - 02
@_Int. Simple:@_PP (0.73m x 2.04m):1350312:1 | Niveau 00 - 02
@_Int. Simple:@_PP (0.73m x 2.04m):1350556:1 | Niveau 00 - 02
@_Int. Simple:@_PP (0.73m x 2.04m):1350508:1 | Niveau 00 - 02
@_Int. Simple:@_PP (0.73m x 2.04m):1350536:1 | Niveau 00 - 02

# IfcPlate: Panneau système:Vitré (22)
Type - PredefinedType: CURTAIN_PANEL; Material: Verre
Type - Pset_PlateCommon - IsExternal: no; Reference: Vitré; ThermalTransmittance: 6.7069 kg/K/s3
Type - Pset_QuantityTakeOff - Reference: Vitré
Name (Panneau système:Vitré:...) | In
1121816 | Niveau 00 - 02
1122024 | Niveau 00 - 02
1122089 | Niveau 00 - 02
1122091 | Niveau 00 - 02
1361502 | Niveau 00 - 02
1361513 | Niveau 00 - 02
1361518 | Niveau 00 - 02
1361520 | Niveau 00 - 02
1368377 | Niveau 00 - 01
1368715 | Niveau 00 - 01
1374203 | Niveau 00 - 01
1374213 | Niveau 00 - 01
1377141 | Niveau 00 - 01
1376380 | Niveau 00 - 01
1376498 | Niveau 00 - 01
1376574 | Niveau 00 - 01
1528181 | Niveau 00 - 01
1528190 | Niveau 00 - 01
1528246 | Niveau 00 - 01
1528209 | Niveau 00 - 01
1528220 | Niveau 00 - 01
1528234 | Niveau 00 - 01

# IfcRailing: Garde-corps:Au Mur (18)
Material: Métal - Peinture Grise
Pset_QuantityTakeOff - Reference: Au Mur
Pset_RailingCommon - IsExternal: no; Reference: Au Mur; Height: 1.2192 m
Name (Garde-corps:Au Mur:...) | In
971797 | Niveau 00 - 01
971801 | Niveau 00 - 01
971884 | Niveau 00 - 02
971888 | Niveau 00 - 02
973459 | Niveau 00 - 02
973463 | Niveau 00 - 02
973960 | SOUS SOL
973964 | SOUS SOL
990251 | Niveau 00 - 03
990255 | Niveau 00 - 03
994644 | Niveau 1
994648 | Niveau 1
1236250 | Niveau 1
1236254 | Niveau 1
1259440 | Niveau 00 - 02
1259444 | Niveau 00 - 02
1532024 | Niveau 00 - 01
1532028 | Niveau 00 - 01

# IfcRailing: Garde-corps:Tuyau 100 cm, Garde-corps:Tuyau 100 cm:1210839
In: Niveau 3 - 01
Pset_QuantityTakeOff - Reference: Tuyau 100 cm
Pset_RailingCommon - IsExternal: no; Reference: Tuyau 100 cm; Height: 1.02 m

# IfcSlab: Sol:@_Sol-Générique - 200 mm (2)
Type - PredefinedType: FLOOR; Material: Sol par défaut 0.2 m
Type - Pset_QuantityTakeOff - Reference: @_Sol-Générique - 200 mm
Type - Pset_ReinforcementBarPitchOfSlab - Reference: @_Sol-Générique - 200 mm
Type - Pset_SlabCommon - IsExternal: no; Reference: @_Sol-Générique - 200 mm
Pset_QuantityTakeOff - sets with these values: 2
Pset_SlabCommon - LoadBearing: no; PitchAngle: 0 deg
Name (Sol:@_Sol-Générique - 200 mm:...) | In
1108071 | Niveau 00 - 02
1139481 | Niveau 3

# IfcSlab: Sol:Béton sur place 100mm, Sol:Béton sur place 100mm:1271569
In: Niveau 2
Type - PredefinedType: FLOOR; Material: Béton, coulé sur place 0.1 m
Type - Pset_QuantityTakeOff - Reference: Béton sur place 100mm
Type - Pset_ReinforcementBarPitchOfSlab - Reference: Béton sur place 100mm
Type - Pset_SlabCommon - IsExternal: no; Reference: Béton sur place 100mm; ThermalTransmittance: 10.46 kg/K/s3
Pset_QuantityTakeOff - sets with these values: 2
Pset_SlabCommon - LoadBearing: no; PitchAngle: 0 deg

# IfcSlab: Sol:Béton sur place 150mm (7)
Type - PredefinedType: FLOOR; Material: Béton, coulé sur place 0.15 m
Type - Pset_QuantityTakeOff - Reference: Béton sur place 150mm
Type - Pset_ReinforcementBarPitchOfSlab - Reference: Béton sur place 150mm
Type - Pset_SlabCommon - IsExternal: no; Reference: Béton sur place 150mm; ThermalTransmittance: 6.97333 kg/K/s3
Pset_QuantityTakeOff - sets with these values: 2
Pset_SlabCommon - LoadBearing: no
Name (Sol:Béton sur place 150mm:...) | In | PitchAngle (deg)
1096311 | SOUS SOL | 38
1100433 | SOUS SOL | 38
1115185 | Niveau 00 - 02 | 0
1244660 | Niveau 1 - 02 | 0
1244807 | Niveau 1 - 03 | 0
1301554 | Niveau 1 - 01 | 22
1301562 | Niveau 1 - 01 | 22

# IfcSlab: Sol:Béton sur place 150mm, Sol:Béton sur place 150mm:1308167
In: Niveau 1 - 01
Type - PredefinedType: FLOOR
Type - Pset_QuantityTakeOff - Reference: Béton sur place 150mm
Type - Pset_ReinforcementBarPitchOfSlab - Reference: Béton sur place 150mm
Type - Pset_SlabCommon - IsExternal: no; Reference: Béton sur place 150mm; ThermalTransmittance: 6.97333 kg/K/s3
Pset_QuantityTakeOff - sets with these values: 2
Pset_SlabCommon - LoadBearing: no; PitchAngle: 22 deg

# IfcSlab: Sol:Dalle béton 200mm (9)
Type - PredefinedType: FLOOR; Material: Béton, coulé sur place 0.2 m
Type - Pset_QuantityTakeOff - Reference: Dalle béton 200mm
Type - Pset_ReinforcementBarPitchOfSlab - Reference: Dalle béton 200mm
Type - Pset_SlabCommon - IsExternal: no; Reference: Dalle béton 200mm; ThermalTransmittance: 5.23 kg/K/s3
Pset_QuantityTakeOff - sets with these values: 2
Pset_SlabCommon - LoadBearing: no; PitchAngle: 0 deg
Name (Sol:Dalle béton 200mm:...) | In
971351 | Niveau 2
971375 | Niveau 1 - 01
971450 | Niveau 1 - 03
971470 | Niveau 4
971705 | SOUS SOL
977241 | Niveau 3 - 02
1036980 | Niveau 00 - 03
1111592 | Niveau 1 - 01
1281167:4 | Niveau 1

# IfcSlab: Sol:Dalle béton 200mm (5)
Type - PredefinedType: FLOOR
Type - Pset_QuantityTakeOff - Reference: Dalle béton 200mm
Type - Pset_ReinforcementBarPitchOfSlab - Reference: Dalle béton 200mm
Type - Pset_SlabCommon - IsExternal: no; Reference: Dalle béton 200mm; ThermalTransmittance: 5.23 kg/K/s3
Pset_QuantityTakeOff - sets with these values: 2
Pset_SlabCommon - LoadBearing: no
Name (Sol:Dalle béton 200mm:...) | In | PitchAngle (deg) | Material
971667 | Niveau 00 - 02 | 0
1281167 | Niveau 1 | 0 | Béton, coulé sur place 0.2 m
1281167:2 | Niveau 1 | 0 | Béton, coulé sur place 0.2 m
1281167:3 | Niveau 1 | 0 | Béton, coulé sur place 0.2 m
1315219 | Niveau 1 - 03 | 3

# IfcSlab: Sol:Dalle béton 250mm (5)
Type - PredefinedType: FLOOR; Material: Béton, coulé sur place 0.25 m
Type - Pset_QuantityTakeOff - Reference: Dalle béton 250mm
Type - Pset_ReinforcementBarPitchOfSlab - Reference: Dalle béton 250mm
Type - Pset_SlabCommon - IsExternal: no; Reference: Dalle béton 250mm; ThermalTransmittance: 4.184 kg/K/s3
Pset_QuantityTakeOff - sets with these values: 2
Pset_SlabCommon - LoadBearing: no; PitchAngle: 0 deg
Name (Sol:Dalle béton 250mm:...) | In
971358 | Niveau 00 - 01
1272038 | Niveau 2
1499907 | Niveau 00 - 01
1500039 | Niveau 00 - 01
1518835 | Niveau 3 - 01

# IfcSlab: Sol:Dalle béton 250mm (2)
Type - PredefinedType: FLOOR
Type - Pset_QuantityTakeOff - Reference: Dalle béton 250mm
Type - Pset_ReinforcementBarPitchOfSlab - Reference: Dalle béton 250mm
Type - Pset_SlabCommon - IsExternal: no; Reference: Dalle béton 250mm; ThermalTransmittance: 4.184 kg/K/s3
Pset_QuantityTakeOff - sets with these values: 2
Pset_SlabCommon - LoadBearing: no; PitchAngle: 0 deg
Name (Sol:Dalle béton 250mm:...) | In
971627 | Niveau 1 - 01
1424022 | Niveau 1

# IfcSlab: Sol:Dalle béton 330mm, Sol:Dalle béton 330mm:971443
In: Niveau 3
Type - PredefinedType: FLOOR; Material: Béton, coulé sur place 0.33 m
Type - Pset_QuantityTakeOff - Reference: Dalle béton 330mm
Type - Pset_ReinforcementBarPitchOfSlab - Reference: Dalle béton 330mm
Type - Pset_SlabCommon - IsExternal: no; Reference: Dalle béton 330mm; ThermalTransmittance: 3.1697 kg/K/s3
Pset_QuantityTakeOff - sets with these values: 2
Pset_SlabCommon - LoadBearing: no; PitchAngle: 0 deg

# IfcSlab: Sol:Générique 100 mm - Plein, Sol:Générique 100 mm - Plein:1048102
In: Niveau 00
Pset_QuantityTakeOff - Reference: Générique 100 mm - Plein; sets with these values: 2
Pset_SlabCommon - IsExternal: no; LoadBearing: no; Reference: Générique 100 mm - Plein; PitchAngle: 0 deg; ThermalTransmittance: 11.5 kg/K/s3

# IfcSlab: Sol:Générique 100 mm - Plein (3)
Type - PredefinedType: FLOOR; Material: Asphalte, bitume 0.1 m
Type - Pset_QuantityTakeOff - Reference: Générique 100 mm - Plein
Type - Pset_ReinforcementBarPitchOfSlab - Reference: Générique 100 mm - Plein
Type - Pset_SlabCommon - IsExternal: no; Reference: Générique 100 mm - Plein; ThermalTransmittance: 11.5 kg/K/s3
Pset_QuantityTakeOff - sets with these values: 2
Pset_SlabCommon - LoadBearing: no; PitchAngle: 0 deg
Name (Sol:Générique 100 mm - Plein:...) | In
972016 | Niveau 00 - 03
975533 | Niveau 00 - 03
1038443 | Niveau 1

# IfcSlab: Sol:Générique 100 mm - Plein, Sol:Générique 100 mm - Plein:971096
In: Niveau 00 - 03
Type - PredefinedType: FLOOR
Type - Pset_QuantityTakeOff - Reference: Générique 100 mm - Plein
Type - Pset_ReinforcementBarPitchOfSlab - Reference: Générique 100 mm - Plein
Type - Pset_SlabCommon - IsExternal: no; Reference: Générique 100 mm - Plein; ThermalTransmittance: 11.5 kg/K/s3
Material: Asphalte, bitume
Pset_QuantityTakeOff - sets with these values: 2
Pset_SlabCommon - LoadBearing: no; PitchAngle: 1.5 deg

# IfcSlab: Sol:Générique 100 mm - Plein (8)
In: Niveau 00
Type - PredefinedType: ROOF
Type - Pset_QuantityTakeOff - Reference: Générique 100 mm - Plein
Type - Pset_ReinforcementBarPitchOfSlab - Reference: Générique 100 mm - Plein
Type - Pset_SlabCommon - IsExternal: no; Reference: Générique 100 mm - Plein; ThermalTransmittance: 11.5 kg/K/s3
Material: Asphalte, bitume
Pset_QuantityTakeOff - sets with these values: 2
Pset_SlabCommon - LoadBearing: no
Name (Sol:Générique 100 mm - Plein:...) | PitchAngle (deg)
1048102 | 4.5931
1048102 | 7.59464
1048102 | 2.04358
1048102 | 3.04809
1048102 | 1.22687
1048102 | 1.58642
1048102 | 3.55871
1048102 | 0

# IfcSlab: Sol:carrelage terrasse 200mm (2)
In: Niveau 00
Type - PredefinedType: FLOOR; Material: Fcarrelage 60x 60 vertical 0.2 m
Type - Pset_QuantityTakeOff - Reference: carrelage terrasse 200mm
Type - Pset_ReinforcementBarPitchOfSlab - Reference: carrelage terrasse 200mm
Type - Pset_SlabCommon - IsExternal: no; Reference: carrelage terrasse 200mm
Pset_QuantityTakeOff - sets with these values: 2
Pset_SlabCommon - LoadBearing: no; PitchAngle: 0 deg
Name (Sol:carrelage terrasse 200mm:...)
1003135:2
1370736

# IfcSlab: Sol:carrelage terrasse 200mm, Sol:carrelage terrasse 200mm:1003135
In: Niveau 00
Type - PredefinedType: FLOOR
Type - Pset_QuantityTakeOff - Reference: carrelage terrasse 200mm
Type - Pset_ReinforcementBarPitchOfSlab - Reference: carrelage terrasse 200mm
Type - Pset_SlabCommon - IsExternal: no; Reference: carrelage terrasse 200mm
Material: Fcarrelage 60x 60 vertical 0.2 m
Pset_QuantityTakeOff - sets with these values: 2
Pset_SlabCommon - LoadBearing: no; PitchAngle: 0 deg

# IfcSlab: Sol:gazon 200 (3)
Type - PredefinedType: FLOOR; Material: ESPACE VERRT 0.2 m
Type - Pset_QuantityTakeOff - Reference: gazon 200
Type - Pset_ReinforcementBarPitchOfSlab - Reference: gazon 200
Type - Pset_SlabCommon - IsExternal: no; Reference: gazon 200; ThermalTransmittance: 5.23 kg/K/s3
Pset_QuantityTakeOff - sets with these values: 2
Pset_SlabCommon - LoadBearing: no
Name (Sol:gazon 200:...) | In | PitchAngle (deg)
1058006 | Niveau 00 - 02 | 1.40247
1363214:3 | Niveau 00 - 02 | 0
1370635 | Niveau 00 | 0

# IfcSlab: Sol:gazon 200 (6)
Type - PredefinedType: FLOOR
Type - Pset_QuantityTakeOff - Reference: gazon 200
Type - Pset_ReinforcementBarPitchOfSlab - Reference: gazon 200
Type - Pset_SlabCommon - IsExternal: no; Reference: gazon 200; ThermalTransmittance: 5.23 kg/K/s3
Pset_QuantityTakeOff - sets with these values: 2
Pset_SlabCommon - LoadBearing: no
Name (Sol:gazon 200:...) | In | PitchAngle (deg)
1001997 | Niveau 00 - 03 | 0 | Material: ESPACE VERRT
1003757 | Niveau 00 - 02 | 0.22624
1048438 | Niveau 00 - 03 | 10.2262
1105576 | Niveau 00 - 02 | 5.60245
1363214 | Niveau 00 - 02 | 0 | Material: ESPACE VERRT 0.2 m
1363214:2 | Niveau 00 - 02 | 0 | Material: ESPACE VERRT 0.2 m

# IfcSlab: Sol:gazon 50, Sol:gazon 50:1120371:2
In: Niveau 00 - 02
Type - PredefinedType: FLOOR; Material: ESPACE VERRT 0.05 m
Type - Pset_QuantityTakeOff - Reference: gazon 50
Type - Pset_ReinforcementBarPitchOfSlab - Reference: gazon 50
Type - Pset_SlabCommon - IsExternal: no; Reference: gazon 50; ThermalTransmittance: 20.92 kg/K/s3
Pset_QuantityTakeOff - sets with these values: 2
Pset_SlabCommon - LoadBearing: no; PitchAngle: 0 deg

# IfcSlab: Sol:gazon 50, Sol:gazon 50:1120371
In: Niveau 00 - 02
Type - PredefinedType: FLOOR
Type - Pset_QuantityTakeOff - Reference: gazon 50
Type - Pset_ReinforcementBarPitchOfSlab - Reference: gazon 50
Type - Pset_SlabCommon - IsExternal: no; Reference: gazon 50; ThermalTransmittance: 20.92 kg/K/s3
Material: ESPACE VERRT 0.05 m
Pset_QuantityTakeOff - sets with these values: 2
Pset_SlabCommon - LoadBearing: no; PitchAngle: 0 deg

# IfcSlab: Sol:gravier terrasse 100mm, Sol:gravier terrasse 100mm:971586
In: Niveau 3
Type - PredefinedType: FLOOR; Material: @_Toit Gravillons 0.1 m
Type - Pset_QuantityTakeOff - Reference: gravier terrasse 100mm
Type - Pset_ReinforcementBarPitchOfSlab - Reference: gravier terrasse 100mm
Type - Pset_SlabCommon - IsExternal: no; Reference: gravier terrasse 100mm
Pset_QuantityTakeOff - sets with these values: 2
Pset_SlabCommon - LoadBearing: no; PitchAngle: 0 deg

# IfcSlab: Sol:gravier terrasse 150mm, Sol:gravier terrasse 150mm:1207917
In: Niveau 4
Type - PredefinedType: FLOOR; Material: @_Toit Gravillons 0.15 m
Type - Pset_QuantityTakeOff - Reference: gravier terrasse 150mm
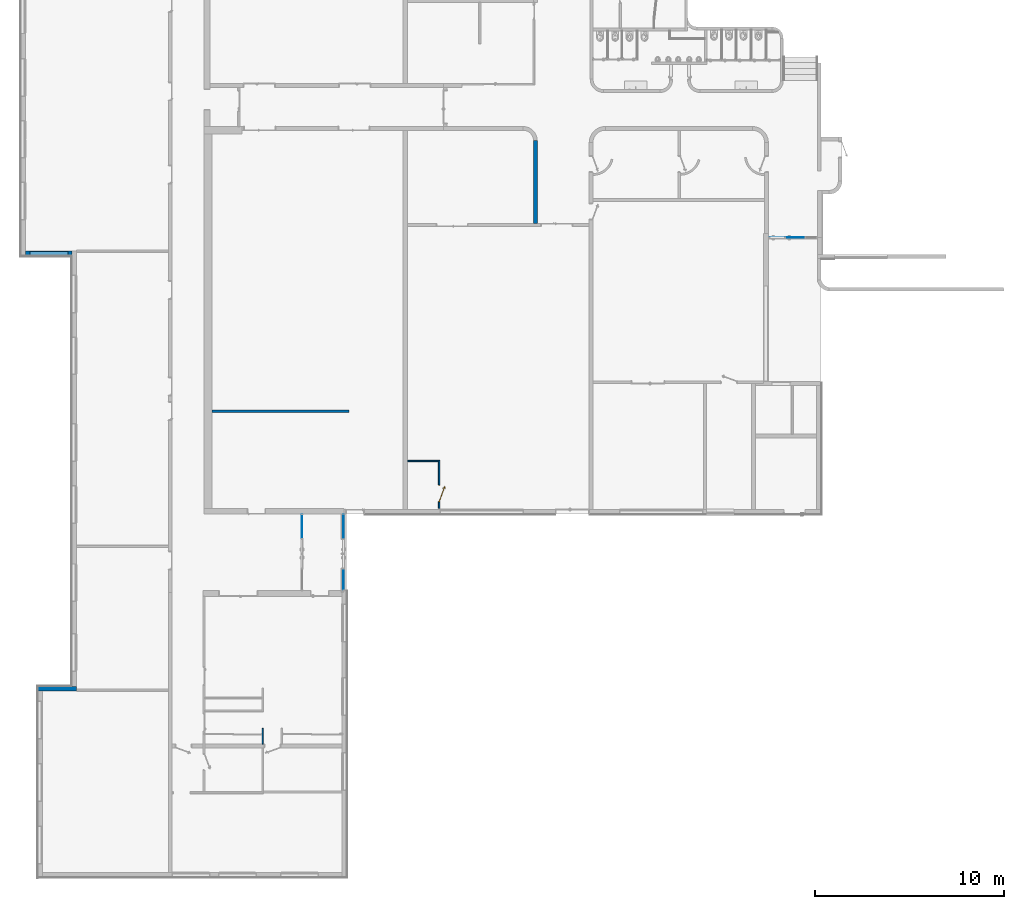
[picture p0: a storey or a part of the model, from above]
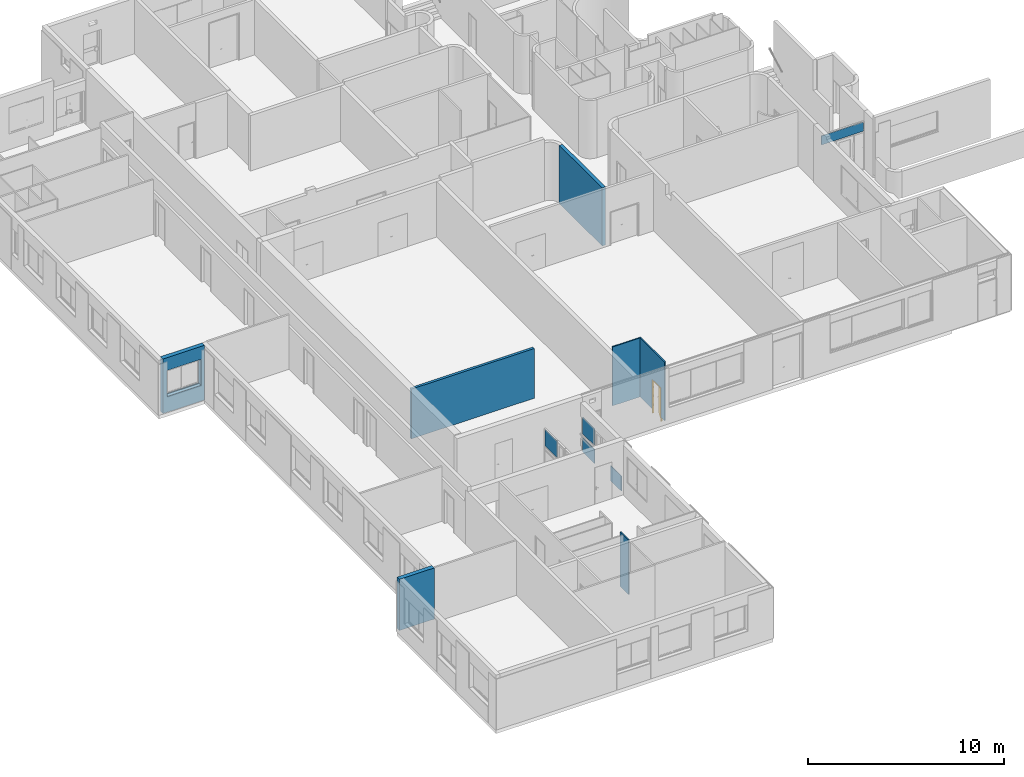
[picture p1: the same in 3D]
Properties of the parts of a building model (IFC2X3), part 3 of 4

# IfcSlab: Sol:gravier terrasse 150mm, Sol:gravier terrasse 150mm:1207917
Type - Pset_ReinforcementBarPitchOfSlab - Reference: gravier terrasse 150mm
Type - Pset_SlabCommon - IsExternal: no; Reference: gravier terrasse 150mm
Pset_QuantityTakeOff - sets with these values: 2
Pset_SlabCommon - LoadBearing: no; PitchAngle: 0 deg

# IfcSlab: Sol:gravier terrasse 50mm, Sol:gravier terrasse 50mm:990429
In: Niveau 3 - 02
Type - PredefinedType: FLOOR; Material: @_Toit Gravillons 0.05 m
Type - Pset_QuantityTakeOff - Reference: gravier terrasse 50mm
Type - Pset_ReinforcementBarPitchOfSlab - Reference: gravier terrasse 50mm
Type - Pset_SlabCommon - IsExternal: no; Reference: gravier terrasse 50mm
Pset_QuantityTakeOff - sets with these values: 2
Pset_SlabCommon - LoadBearing: no; PitchAngle: 0 deg

# IfcSlab: Sol:étanchéité terrasse 100mm (7)
Type - PredefinedType: FLOOR; Material: étanchéité Isolation 0.1 m
Type - Pset_QuantityTakeOff - Reference: étanchéité terrasse 100mm
Type - Pset_ReinforcementBarPitchOfSlab - Reference: étanchéité terrasse 100mm
Type - Pset_SlabCommon - IsExternal: no; Reference: étanchéité terrasse 100mm
Pset_QuantityTakeOff - sets with these values: 2
Pset_SlabCommon - LoadBearing: no
Name (Sol:étanchéité terrasse 100mm:...) | In | PitchAngle (deg)
1110559 | Niveau 00 - 02 | 0
1299825 | Niveau 1 | 22
1299957 | Niveau 1 - 03 | 0
1300883 | Niveau 1 | 22
1300891 | Niveau 1 - 03 | 0
1308135 | Niveau 1 | 22
1308143 | Niveau 1 - 03 | 0

# IfcSlab: Sol:étanchéité terrasse 100mm, Sol:étanchéité terrasse 100mm:1067465
In: Niveau 1 - 01
Type - PredefinedType: FLOOR
Type - Pset_QuantityTakeOff - Reference: étanchéité terrasse 100mm
Type - Pset_ReinforcementBarPitchOfSlab - Reference: étanchéité terrasse 100mm
Type - Pset_SlabCommon - IsExternal: no; Reference: étanchéité terrasse 100mm
Material: étanchéité Isolation
Pset_QuantityTakeOff - sets with these values: 2
Pset_SlabCommon - LoadBearing: no; PitchAngle: 0 deg

# IfcSlab: Sol:étanchéité terrasse 250mm, Sol:étanchéité terrasse 250mm:990783
In: Niveau 3
Type - PredefinedType: FLOOR
Type - Pset_QuantityTakeOff - Reference: étanchéité terrasse 250mm
Type - Pset_ReinforcementBarPitchOfSlab - Reference: étanchéité terrasse 250mm
Type - Pset_SlabCommon - IsExternal: no; Reference: étanchéité terrasse 250mm
Material: étanchéité Isolation
Pset_QuantityTakeOff - sets with these values: 2
Pset_SlabCommon - LoadBearing: no; PitchAngle: 1 deg

# IfcSlab: Sol:étanchéité terrasse 25mm, Sol:étanchéité terrasse 25mm:1315242
In: Niveau 1 - 03
Type - PredefinedType: FLOOR; Material: étanchéité Isolation 0.025 m
Type - Pset_QuantityTakeOff - Reference: étanchéité terrasse 25mm
Type - Pset_ReinforcementBarPitchOfSlab - Reference: étanchéité terrasse 25mm
Type - Pset_SlabCommon - IsExternal: no; Reference: étanchéité terrasse 25mm
Pset_QuantityTakeOff - sets with these values: 2
Pset_SlabCommon - LoadBearing: no; PitchAngle: 3 deg

# IfcSlab: Sol:étanchéité terrasse 50mm, Sol:étanchéité terrasse 50mm:1118400
In: Niveau 00 - 02
Type - PredefinedType: FLOOR; Material: étanchéité Isolation 0.05 m
Type - Pset_QuantityTakeOff - Reference: étanchéité terrasse 50mm
Type - Pset_ReinforcementBarPitchOfSlab - Reference: étanchéité terrasse 50mm
Type - Pset_SlabCommon - IsExternal: no; Reference: étanchéité terrasse 50mm
Pset_QuantityTakeOff - sets with these values: 2
Pset_SlabCommon - LoadBearing: no; PitchAngle: 0 deg

# IfcStair: Escalier coulé sur place:Escalier monobloc (11)
Pset_QuantityTakeOff - Reference: Escalier monobloc
Pset_StairCommon - IsExternal: no; Reference: Escalier monobloc; TreadLength: 0.28 m
Name (Escalier coulé sur place:Escalier:...) | In | ShapeType | NumberOfRiser | NumberOfTreads | RiserHeight (m)
971785 | Niveau 00 - 01 | STRAIGHT_RUN_STAIR | 5 | 4 | 0.16
971872 | Niveau 00 - 02 | STRAIGHT_RUN_STAIR | 21 | 20 | 0.161455
973448 | Niveau 00 - 02 | STRAIGHT_RUN_STAIR | 9 | 8 | 0.183153
973949 | SOUS SOL | STRAIGHT_RUN_STAIR | 8 | 7 | 0.15125
990240 | Niveau 00 - 03 | STRAIGHT_RUN_STAIR | 12 | 11 | 0.164415
994633 | Niveau 1 |  | 21 | 20 | 0.162272
1057760 | Niveau 00 | STRAIGHT_RUN_STAIR | 4 | 3 | 0.17857
1209046 | Niveau 3 - 01 | STRAIGHT_RUN_STAIR | 7 | 6 | 0.153333
1234658 | Niveau 1 |  | 21 | 20 | 0.162272
1259408 | Niveau 00 - 02 |  | 21 | 20 | 0.152391
1532012 | Niveau 00 - 01 | STRAIGHT_RUN_STAIR | 5 | 4 | 0.16

# IfcStairFlight: Volée monobloc:Profondeur de structure 200 mm (9)
Type - Pset_QuantityTakeOff - Reference: Profondeur de structure 200 mm
Type - Pset_StairFlightCommon - Reference: Profondeur de structure 200 mm
TreadLength: 0.918635 m; Material: Béton, coulé sur place
Pset_StairFlightCommon - TreadLength: 0.28 m; NosingLength: 0 m; TreadLengthAtOffset: 0.28 m; TreadLengthAtInnerSide: 0.28 m
Name (Escalier coulé sur place:Escalier:...) | In | NumberOfRiser = Pset_StairFlightCommon, NumberOfRiser | NumberOfTreads = Pset_StairFlightCommon, NumberOfTreads | RiserHeight (m) | Pset_StairFlightCommon, RiserHeight (m)
971785 Run 1 | Niveau 00 - 01 | 5 | 4 | 0.524934 | 0.16
971872 Run 1 | Niveau 00 - 02 | 21 | 20 | 0.529709 | 0.161455
973448 Run 1 | Niveau 00 - 02 | 9 | 8 | 0.600896 | 0.183153
973949 Run 1 | SOUS SOL | 8 | 7 | 0.496227 | 0.15125
990240 Run 1 | Niveau 00 - 03 | 12 | 11 | 0.539419 | 0.164415
994633 Run 1 | Niveau 1 | 21 | 20 | 0.532388 | 0.162272
1234658 Run 1 | Niveau 1 | 21 | 20 | 0.532388 | 0.162272
1259408 Run 1 | Niveau 00 - 02 | 21 | 20 | 0.49997 | 0.152391
1532012 Run 1 | Niveau 00 - 01 | 5 | 4 | 0.524934 | 0.16

# IfcWall: Mur de base:@_Générique - Int. 100 mm (4)
Type - PredefinedType: STANDARD; Material: Mur par défaut 0.1 m
Type - Pset_QuantityTakeOff - Reference: @_Générique - Int. 100 mm
Type - Pset_ReinforcementBarPitchOfWall - Reference: @_Générique - Int. 100 mm
Type - Pset_WallCommon - IsExternal: no; Reference: @_Générique - Int. 100 mm
Pset_QuantityTakeOff - sets with these values: 2
Pset_WallCommon - LoadBearing: no
Name (Mur de base:@_Générique - Int. 100 mm:...) | In | ExtendToStructure
971535 | Niveau 2 | yes
971935 | Niveau 00 - 01 | no
1203947 | Niveau 2 | yes
1261008 | Niveau 00 - 01 | yes

# IfcWall: Mur de base:@_Générique - Int. 120 mm, Mur de base:@_Générique - Int. 120 mm:1336379
In: Niveau 00 - 02
Type - PredefinedType: STANDARD; Material: Mur par défaut 0.12 m
Type - Pset_QuantityTakeOff - Reference: @_Générique - Int. 120 mm
Type - Pset_ReinforcementBarPitchOfWall - Reference: @_Générique - Int. 120 mm
Type - Pset_WallCommon - IsExternal: no; Reference: @_Générique - Int. 120 mm
Pset_QuantityTakeOff - sets with these values: 2
Pset_WallCommon - LoadBearing: no; ExtendToStructure: yes

# IfcWall: Mur de base:@_Générique - Int. 150 mm (4)
Type - PredefinedType: STANDARD; Material: Mur par défaut 0.15 m
Type - Pset_QuantityTakeOff - Reference: @_Générique - Int. 150 mm
Type - Pset_ReinforcementBarPitchOfWall - Reference: @_Générique - Int. 150 mm
Type - Pset_WallCommon - IsExternal: no; Reference: @_Générique - Int. 150 mm
Pset_QuantityTakeOff - sets with these values: 2
Pset_WallCommon - LoadBearing: no
Name (Mur de base:@_Générique - Int. 150 mm:...) | In | ExtendToStructure
970929 | Niveau 00 - 02 | no
971311 | Niveau 1 | yes
971395 | Niveau 2 | no
1202678 | Niveau 2 | yes

# IfcWall: Mur de base:@_Générique - Int. 200 mm (2)
Type - PredefinedType: STANDARD; Material: Mur par défaut 0.2 m
Type - Pset_QuantityTakeOff - Reference: @_Générique - Int. 200 mm
Type - Pset_ReinforcementBarPitchOfWall - Reference: @_Générique - Int. 200 mm
Type - Pset_WallCommon - IsExternal: no; Reference: @_Générique - Int. 200 mm
Pset_QuantityTakeOff - sets with these values: 2
Pset_WallCommon - LoadBearing: no
Name (Mur de base:@_Générique - Int. 200 mm:...) | In | ExtendToStructure
971344 | Niveau 1 | yes
971408 | Niveau 2 | no

# IfcWall: Mur de base:@_Générique - Int. 60 mm, Mur de base:@_Générique - Int. 60 mm:1110657
In: Niveau 00 - 02
Type - PredefinedType: STANDARD; Material: FP - Peinture bleu 0.06 m
Type - Pset_QuantityTakeOff - Reference: @_Générique - Int. 60 mm
Type - Pset_ReinforcementBarPitchOfWall - Reference: @_Générique - Int. 60 mm
Type - Pset_WallCommon - IsExternal: no; Reference: @_Générique - Int. 60 mm
Pset_QuantityTakeOff - sets with these values: 2
Pset_WallCommon - ExtendToStructure: no; LoadBearing: no

# IfcWall: Mur de base:@_Générique - Int. 70 mm (5)
Type - PredefinedType: STANDARD; Material: Mur par défaut 0.07 m
Type - Pset_QuantityTakeOff - Reference: @_Générique - Int. 70 mm
Type - Pset_ReinforcementBarPitchOfWall - Reference: @_Générique - Int. 70 mm
Type - Pset_WallCommon - IsExternal: no; Reference: @_Générique - Int. 70 mm
Pset_QuantityTakeOff - sets with these values: 2
Pset_WallCommon - LoadBearing: no
Name (Mur de base:@_Générique - Int. 70 mm:...) | In | ExtendToStructure
1246613 | Niveau 1 | yes
1249735 | Niveau 1 | yes
1262111 | Niveau 00 - 02 | no
1293453 | Niveau 2 | yes
1337231 | Niveau 00 - 02 | yes

# IfcWall: Mur de base:Ext. Mur 250+enduit Rouge, Mur de base:Ext. Mur 250+enduit Rouge:971292
In: Niveau 1
Type - PredefinedType: STANDARD; Material: Maçonnerie - Voile BA rouge 0.24 m, @_Enduit Pierre 0.01 m
Type - Pset_QuantityTakeOff - Reference: Ext. Mur 250+enduit Rouge
Type - Pset_ReinforcementBarPitchOfWall - Reference: Ext. Mur 250+enduit Rouge
Type - Pset_WallCommon - IsExternal: no; Reference: Ext. Mur 250+enduit Rouge
Pset_QuantityTakeOff - sets with these values: 2
Pset_WallCommon - IsExternal: yes; ExtendToStructure: no; LoadBearing: no

# IfcWall: Mur de base:Ext. Voile BA 150 (6)
Type - PredefinedType: STANDARD; Material: Maçonnerie - Voile BA 0.15 m
Type - Pset_QuantityTakeOff - Reference: Ext. Voile BA 150
Type - Pset_ReinforcementBarPitchOfWall - Reference: Ext. Voile BA 150
Type - Pset_WallCommon - IsExternal: no; Reference: Ext. Voile BA 150
Pset_QuantityTakeOff - sets with these values: 2
Pset_WallCommon - IsExternal: yes; LoadBearing: no
Name (Mur de base:Ext. Voile BA 150:...) | In | ExtendToStructure
970926 | Niveau 00 - 02 | yes
970930 | Niveau 00 - 02 | yes
971309 | Niveau 1 | yes
971401 | Niveau 2 | no
971407 | Niveau 2 | yes
1273570 | Niveau 1 | yes

# IfcWall: Mur de base:Ext. Voile BA 180 (3)
In: SOUS SOL
Type - PredefinedType: STANDARD; Material: Maçonnerie - Voile BA 0.18 m
Type - Pset_QuantityTakeOff - Reference: Ext. Voile BA 180
Type - Pset_ReinforcementBarPitchOfWall - Reference: Ext. Voile BA 180
Type - Pset_WallCommon - IsExternal: no; Reference: Ext. Voile BA 180
Pset_QuantityTakeOff - sets with these values: 2
Pset_WallCommon - IsExternal: yes; ExtendToStructure: no; LoadBearing: no
Name (Mur de base:Ext. Voile BA 180:...)
1096114
1096248
1100430

# IfcWall: Mur de base:Ext. Voile BA 200 (16)
Type - PredefinedType: STANDARD; Material: Maçonnerie - Voile BA 0.2 m
Type - Pset_QuantityTakeOff - Reference: Ext. Voile BA 200
Type - Pset_ReinforcementBarPitchOfWall - Reference: Ext. Voile BA 200
Type - Pset_WallCommon - IsExternal: no; Reference: Ext. Voile BA 200
Pset_QuantityTakeOff - sets with these values: 2
Pset_WallCommon - IsExternal: yes; LoadBearing: no
Name (Mur de base:Ext. Voile BA 200:...) | In | ExtendToStructure
970863 | Niveau 00 - 02 | no | Material: Maçonnerie - Voile BA
970951 | Niveau 00 - 01 | yes
971317 | Niveau 1 | yes
971318 | Niveau 1 | yes
971391 | Niveau 2 | yes
971411 | Niveau 2 | yes
971415 | Niveau 2 | yes
971419 | Niveau 2 | yes
971461 | Niveau 3 - 01 | no
971523 | Niveau 2 | yes
971555 | Niveau 2 | yes
971560 | Niveau 2 | yes
971565 | Niveau 2 | yes
971566 | Niveau 2 | yes
1228511 | Niveau 3 - 02 | no
1229001 | Niveau 3 - 02 | no

# IfcWall: Mur de base:Ext. Voile BA 210, Mur de base:Ext. Voile BA 210:1347475
In: Niveau 00 - 02
Type - PredefinedType: STANDARD; Material: Maçonnerie - Voile BA 0.21 m
Type - Pset_QuantityTakeOff - Reference: Ext. Voile BA 210
Type - Pset_ReinforcementBarPitchOfWall - Reference: Ext. Voile BA 210
Type - Pset_WallCommon - IsExternal: no; Reference: Ext. Voile BA 210
Material: Maçonnerie - Voile BA
Pset_QuantityTakeOff - sets with these values: 2
Pset_WallCommon - IsExternal: yes; ExtendToStructure: no; LoadBearing: no

# IfcWall: Mur de base:Ext. Voile BA 300, Mur de base:Ext. Voile BA 300:970904
In: Niveau 00 - 01
Type - PredefinedType: STANDARD; Material: Maçonnerie - Voile BA 0.3 m
Type - Pset_QuantityTakeOff - Reference: Ext. Voile BA 300
Type - Pset_ReinforcementBarPitchOfWall - Reference: Ext. Voile BA 300
Type - Pset_WallCommon - IsExternal: no; Reference: Ext. Voile BA 300
Pset_QuantityTakeOff - sets with these values: 2
Pset_WallCommon - IsExternal: yes; ExtendToStructure: no; LoadBearing: no

# IfcWall: Mur de base:Mur 100- isolation 100 - enduit, Mur de base:Mur 100- isolation 100 - enduit:970880
In: Niveau 00
Type - PredefinedType: STANDARD; Material: @_Enduit Pierre 0.01 m, Maçonnerie - Isolant 0.09 m, Maçonnerie - Voile BA 0.1 m
Type - Pset_QuantityTakeOff - Reference: Mur 100- isolation 100 - enduit
Type - Pset_ReinforcementBarPitchOfWall - Reference: Mur 100- isolation 100 - enduit
Type - Pset_WallCommon - IsExternal: no; Reference: Mur 100- isolation 100 - enduit
Material: @_Enduit Pierre, Maçonnerie - Isolant, Maçonnerie - Voile BA
Pset_QuantityTakeOff - sets with these values: 2
Pset_WallCommon - IsExternal: yes; LoadBearing: no; ExtendToStructure: yes

# IfcWall: Mur de base:Mur Blanc 150- isolation 50, Mur de base:Mur Blanc 150- isolation 50:970860
In: Niveau 00 - 01
Type - PredefinedType: STANDARD; Material: Maçonnerie - Isolant 0.05 m, béton gris 0.15 m
Type - Pset_QuantityTakeOff - Reference: Mur Blanc 150- isolation 50
Type - Pset_ReinforcementBarPitchOfWall - Reference: Mur Blanc 150- isolation 50
Type - Pset_WallCommon - IsExternal: no; Reference: Mur Blanc 150- isolation 50
Pset_QuantityTakeOff - sets with these values: 2
Pset_WallCommon - IsExternal: yes; ExtendToStructure: no; LoadBearing: no

# IfcWall: Mur de base:Mur EXE 200- Hach (3)
In: Niveau 00 - 01
Type - PredefinedType: STANDARD; Material: Finition vertical béton 0.03 m, Maçonnerie - Voile BA 0.17 m
Type - Pset_QuantityTakeOff - Reference: Mur EXE 200- Hach
Type - Pset_ReinforcementBarPitchOfWall - Reference: Mur EXE 200- Hach
Type - Pset_WallCommon - IsExternal: no; Reference: Mur EXE 200- Hach
Pset_QuantityTakeOff - sets with these values: 2
Pset_WallCommon - IsExternal: yes; ExtendToStructure: no; LoadBearing: no
Name (Mur de base:Mur EXE 200- Hach:...)
970861 | Material: Finition vertical béton, Maçonnerie - Voile BA
970862
1035829

# IfcWall: Mur de base:Mur EXE 200- Hach 2 faces, Mur de base:Mur EXE 200- Hach 2 faces:1357346
In: Niveau 00 - 02
Type - PredefinedType: STANDARD; Material: Finition vertical béton 0.025 m, Maçonnerie - Voile BA 0.15 m, Finition vertical béton 0.025 m
Type - Pset_QuantityTakeOff - Reference: Mur EXE 200- Hach 2 faces
Type - Pset_ReinforcementBarPitchOfWall - Reference: Mur EXE 200- Hach 2 faces
Type - Pset_WallCommon - IsExternal: no; Reference: Mur EXE 200- Hach 2 faces
Material: Finition vertical béton (2), Maçonnerie - Voile BA
Pset_QuantityTakeOff - sets with these values: 2
Pset_WallCommon - IsExternal: yes; LoadBearing: no; ExtendToStructure: yes

# IfcWall: Mur de base:Mur EXE 40- Hach (9)
Type - PredefinedType: STANDARD; Material: Finition vertical béton 0.04 m
Type - Pset_QuantityTakeOff - Reference: Mur EXE 40- Hach
Type - Pset_ReinforcementBarPitchOfWall - Reference: Mur EXE 40- Hach
Type - Pset_WallCommon - IsExternal: no; Reference: Mur EXE 40- Hach
Pset_QuantityTakeOff - sets with these values: 2
Pset_WallCommon - IsExternal: yes; ExtendToStructure: no; LoadBearing: no
Name (Mur de base:Mur EXE 40- Hach:...) | In
1335926 | Niveau 00
1381339 | Niveau 00 - 01
1384883 | Niveau 00 - 01
1389203 | Niveau 00 - 01
1389592 | Niveau 00 - 01
1390316 | Niveau 00 - 01
1391697 | Niveau 00 - 01
1392037 | Niveau 00 - 01
1419077 | Niveau 00 - 01

# IfcWall: Mur de base:Mur en verre 70, Mur de base:Mur en verre 70:1008322
In: Niveau 00 - 03
Type - PredefinedType: STANDARD; Material: Verre 0.07 m
Type - Pset_QuantityTakeOff - Reference: Mur en verre 70
Type - Pset_ReinforcementBarPitchOfWall - Reference: Mur en verre 70
Type - Pset_WallCommon - IsExternal: no; Reference: Mur en verre 70; ThermalTransmittance: 15.7143 kg/K/s3
Pset_QuantityTakeOff - sets with these values: 2
Pset_WallCommon - IsExternal: yes; ExtendToStructure: no; LoadBearing: no

# IfcWall: Murs 1:Murs 1, Murs 1:Murs 1:1492261
In: Niveau 00 - 02
Type - Material: Mur par défaut
Type - Pset_QuantityTakeOff - Reference: Murs 1
Type - Pset_ReinforcementBarPitchOfWall - Reference: Murs 1
Type - Pset_WallCommon - IsExternal: no; Reference: Murs 1
Pset_QuantityTakeOff - sets with these values: 2

# IfcWallStandardCase: Mur de base:@_Générique - Int. 100 mm (70)
Type - PredefinedType: STANDARD; Material: Mur par défaut 0.1 m
Type - Pset_QuantityTakeOff - Reference: @_Générique - Int. 100 mm
Type - Pset_ReinforcementBarPitchOfWall - Reference: @_Générique - Int. 100 mm
Type - Pset_WallCommon - IsExternal: no; Reference: @_Générique - Int. 100 mm
Pset_QuantityTakeOff - sets with these values: 2
Pset_WallCommon - LoadBearing: no
Name (Mur de base:@_Générique - Int. 100 mm:...) | In | ExtendToStructure
970902 | Niveau 00 - 01 | yes
970903 | Niveau 00 - 01 | yes
970949 | Niveau 00 - 01 | yes
970950 | Niveau 00 - 01 | yes
970991 | Niveau 00 - 02 | yes
971276 | Niveau 00 - 03 | no
971277 | Niveau 00 - 03 | no
971278 | Niveau 00 - 03 | no
971282 | Niveau 00 - 03 | no
971283 | Niveau 00 - 02 | no
971341 | Niveau 1 | yes
971342 | Niveau 1 | yes
971346 | Niveau 1 | yes
971347 | Niveau 1 | yes
971430 | Niveau 2 | yes
971433 | Niveau 2 | no
971438 | Niveau 2 | yes
971439 | Niveau 2 | yes
971526 | Niveau 2 | yes
971527 | Niveau 2 | yes
971529 | Niveau 2 | yes
971530 | Niveau 2 | yes
971531 | Niveau 2 | yes
971534 | Niveau 2 | yes
971536 | Niveau 2 | yes
971540 | Niveau 2 | yes
971556 | Niveau 2 | yes
971557 | Niveau 2 | yes
971559 | Niveau 2 | yes
971581 | Niveau 2 | no
971933 | Niveau 00 - 01 | yes
971934 | Niveau 00 - 01 | yes
971938 | Niveau 00 - 01 | yes
971940 | Niveau 00 - 01 | yes
971941 | Niveau 00 - 01 | yes
971951 | SOUS SOL | no
971955 | Niveau 00 - 02 | no
981816 | Niveau 00 - 03 | no
981818 | Niveau 00 - 03 | no
999455 | Niveau 00 - 03 | no
999606 | Niveau 00 - 03 | no
1094357 | SOUS SOL | no
1095862 | SOUS SOL | no
1100851 | SOUS SOL | no
1187000 | Niveau 00 - 03 | no
1187106 | SOUS SOL | no
1203948 | Niveau 2 | yes
1203949 | Niveau 2 | yes
1232446 | Niveau 2 | yes
1246276 | Niveau 1 | yes
1246914 | Niveau 1 | yes
1247070 | Niveau 1 | yes
1248243 | Niveau 1 | yes
1248326 | Niveau 1 | yes
1248790 | Niveau 1 | yes
1250486 | Niveau 1 | yes
1250516 | Niveau 1 | yes
1255123 | Niveau 1 | yes
1255728 | Niveau 1 | yes
1257650 | Niveau 1 | yes
1266844 | Niveau 00 - 01 | no
1294193 | Niveau 2 | no
1309182 | Niveau 00 - 01 | yes
1393826 | Niveau 00 - 01 | yes
1400946 | Niveau 00 - 01 | no
1400951 | Niveau 00 - 01 | no
1401142 | Niveau 00 - 01 | no
1406730 | Niveau 00 - 01 | no
1494085 | Niveau 00 - 02 | yes
1496479 | Niveau 00 - 02 | no

# IfcWallStandardCase: Mur de base:@_Générique - Int. 120 mm (12)
Type - PredefinedType: STANDARD; Material: Mur par défaut 0.12 m
Type - Pset_QuantityTakeOff - Reference: @_Générique - Int. 120 mm
Type - Pset_ReinforcementBarPitchOfWall - Reference: @_Générique - Int. 120 mm
Type - Pset_WallCommon - IsExternal: no; Reference: @_Générique - Int. 120 mm
Pset_QuantityTakeOff - sets with these values: 2
Pset_WallCommon - LoadBearing: no
Name (Mur de base:@_Générique - Int. 120 mm:...) | In | ExtendToStructure
970952 | Niveau 00 - 01 | yes
970997 | Niveau 00 - 02 | yes
971413 | Niveau 2 | yes
1207491 | Niveau 3 - 01 | yes
1207515 | Niveau 3 - 01 | yes
1207548 | Niveau 3 - 01 | yes
1238898 | Niveau 1 | yes
1240358 | Niveau 1 | yes
1250367 | Niveau 1 | yes
1253892 | Niveau 1 | yes
1394313 | Niveau 00 - 01 | yes
1498010 | Niveau 00 - 02 | no

# IfcWallStandardCase: Mur de base:@_Générique - Int. 150 mm (45)
Type - PredefinedType: STANDARD; Material: Mur par défaut 0.15 m
Type - Pset_QuantityTakeOff - Reference: @_Générique - Int. 150 mm
Type - Pset_ReinforcementBarPitchOfWall - Reference: @_Générique - Int. 150 mm
Type - Pset_WallCommon - IsExternal: no; Reference: @_Générique - Int. 150 mm
Pset_QuantityTakeOff - sets with these values: 2
Pset_WallCommon - LoadBearing: no
Name (Mur de base:@_Générique - Int. 150 mm:...) | In | ExtendToStructure
970924 | Niveau 00 - 02 | no
970927 | Niveau 00 - 02 | no
970934 | Niveau 00 - 01 | yes
971299 | Niveau 1 | yes
971301 | Niveau 1 | yes
971396 | Niveau 2 | yes
971397 | Niveau 2 | yes
971398 | Niveau 2 | yes
971420 | Niveau 2 | yes
971424 | Niveau 2 | yes
971425 | Niveau 2 | yes
971574 | Niveau 2 | yes
971576 | Niveau 2 | yes
971583 | Niveau 2 | no
971936 | Niveau 00 - 01 | no
971937 | Niveau 00 - 01 | yes
979318 | Niveau 1 - 03 | no
979596 | Niveau 1 - 03 | no
979602 | Niveau 1 - 03 | no
979607 | Niveau 1 - 03 | no
979612 | Niveau 1 - 03 | no
979659 | Niveau 1 - 03 | no
979664 | Niveau 1 - 03 | no
979670 | Niveau 1 - 03 | no
979675 | Niveau 1 - 03 | no
979922 | Niveau 1 - 03 | no
1007285 | Niveau 00 - 03 | no
1202749 | Niveau 2 | yes
1206682 | Niveau 2 | yes
1207463 | Niveau 3 - 01 | yes
1230431 | Niveau 3 - 02 | no
1230519 | Niveau 3 - 02 | no
1231314 | Niveau 2 | no
1237170 | Niveau 1 | no
1243090 | Niveau 1 | yes
1252157 | Niveau 1 | yes
1252931 | Niveau 1 | yes
1260660 | Niveau 00 - 01 | no
1369730 | Niveau 1 - 03 | no
1488642 | Niveau 00 - 01 | no
1512044 | Niveau 2 | no
1512167 | Niveau 2 | no
1532888 | Niveau 1 | yes
1533060 | Niveau 1 | yes
1533356 | Niveau 1 | yes

# IfcWallStandardCase: Mur de base:@_Générique - Int. 180 mm (5)
Type - PredefinedType: STANDARD; Material: Mur par défaut 0.18 m
Type - Pset_QuantityTakeOff - Reference: @_Générique - Int. 180 mm
Type - Pset_ReinforcementBarPitchOfWall - Reference: @_Générique - Int. 180 mm
Type - Pset_WallCommon - IsExternal: no; Reference: @_Générique - Int. 180 mm
Pset_QuantityTakeOff - sets with these values: 2
Pset_WallCommon - LoadBearing: no
Name (Mur de base:@_Générique - Int. 180 mm:...) | In | ExtendToStructure
971284 | Niveau 00 | no
971307 | Niveau 1 | yes
971312 | Niveau 1 | yes
1244840 | Niveau 1 | yes
1255462 | Niveau 1 | no

# IfcWallStandardCase: Mur de base:@_Générique - Int. 200 mm (30)
Type - PredefinedType: STANDARD; Material: Mur par défaut 0.2 m
Type - Pset_QuantityTakeOff - Reference: @_Générique - Int. 200 mm
Type - Pset_ReinforcementBarPitchOfWall - Reference: @_Générique - Int. 200 mm
Type - Pset_WallCommon - IsExternal: no; Reference: @_Générique - Int. 200 mm
Pset_QuantityTakeOff - sets with these values: 2
Pset_WallCommon - LoadBearing: no
Name (Mur de base:@_Générique - Int. 200 mm:...) | In | ExtendToStructure
970874 | Niveau 00 - 01 | no
970989 | Niveau 00 - 02 | no
971285 | Niveau 00 - 03 | no
971314 | Niveau 1 | yes
971315 | Niveau 1 | yes
971316 | Niveau 1 | yes
971319 | Niveau 1 | yes
971334 | Niveau 1 | yes
971335 | Niveau 1 | yes
971573 | Niveau 2 | yes
971578 | Niveau 2 | yes
976021 | SOUS SOL | no
976022 | SOUS SOL | no
976023 | SOUS SOL | no
976024 | SOUS SOL | no
976025 | SOUS SOL | no
976026 | SOUS SOL | no
976027 | SOUS SOL | no
976029 | SOUS SOL | no
1034346 | SOUS SOL | no
1238956 | Niveau 1 | yes
1249353 | Niveau 1 | yes
1253705 | Niveau 1 - 03 | yes
1254208 | Niveau 1 | yes
1268434 | Niveau 1 - 03 | yes
1308947 | Niveau 00 - 01 | yes
1309145 | Niveau 00 - 01 | yes
1405557 | Niveau 00 - 01 | no
1509098 | Niveau 1 | yes
1531084 | Niveau 00 - 01 | yes

# IfcWallStandardCase: Mur de base:@_Générique - Int. 220 mm, Mur de base:@_Générique - Int. 220 mm:1488830
In: Niveau 00 - 01
Type - PredefinedType: STANDARD; Material: Mur par défaut 0.22 m
Type - Pset_QuantityTakeOff - Reference: @_Générique - Int. 220 mm
Type - Pset_ReinforcementBarPitchOfWall - Reference: @_Générique - Int. 220 mm
Type - Pset_WallCommon - IsExternal: no; Reference: @_Générique - Int. 220 mm
Pset_QuantityTakeOff - sets with these values: 2
Pset_WallCommon - LoadBearing: no; ExtendToStructure: yes

# IfcWallStandardCase: Mur de base:@_Générique - Int. 350 mm, Mur de base:@_Générique - Int. 350 mm:1296656
In: Niveau 2
Type - PredefinedType: STANDARD; Material: Mur par défaut 0.35 m
Type - Pset_QuantityTakeOff - Reference: @_Générique - Int. 350 mm
Type - Pset_ReinforcementBarPitchOfWall - Reference: @_Générique - Int. 350 mm
Type - Pset_WallCommon - IsExternal: no; Reference: @_Générique - Int. 350 mm
Pset_QuantityTakeOff - sets with these values: 2
Pset_WallCommon - LoadBearing: no; ExtendToStructure: yes

# IfcWallStandardCase: Mur de base:@_Générique - Int. 50 mm (29)
Type - PredefinedType: STANDARD; Material: Mur par défaut 0.05 m
Type - Pset_QuantityTakeOff - Reference: @_Générique - Int. 50 mm
Type - Pset_ReinforcementBarPitchOfWall - Reference: @_Générique - Int. 50 mm
Type - Pset_WallCommon - IsExternal: no; Reference: @_Générique - Int. 50 mm
Pset_QuantityTakeOff - sets with these values: 2
Pset_WallCommon - LoadBearing: no
Name (Mur de base:@_Générique - Int. 50 mm:...) | In | ExtendToStructure
1007950 | Niveau 00 - 03 | no
1008045 | Niveau 00 - 03 | no
1008114 | Niveau 00 - 03 | no
1008247 | Niveau 00 - 03 | no
1008272 | Niveau 00 - 03 | no
1046115 | Niveau 00 - 03 | no
1046158 | Niveau 00 - 03 | no
1089079 | Niveau 00 - 03 | no
1267054 | Niveau 00 - 01 | yes
1267235 | Niveau 00 - 01 | yes
1283127 | Niveau 1 | yes
1283493 | Niveau 1 | yes
1294213 | Niveau 2 | no
1394448 | Niveau 00 - 01 | yes
1394449 | Niveau 00 - 01 | yes
1394502 | Niveau 00 - 01 | yes
1394647 | Niveau 00 - 01 | yes
1394706 | Niveau 00 - 01 | yes
1394777 | Niveau 00 - 01 | yes
1394849 | Niveau 00 - 01 | yes
1394877 | Niveau 00 - 01 | no
1395006 | Niveau 00 - 01 | yes
1395084 | Niveau 00 - 01 | yes
1395185 | Niveau 00 - 02 | yes
1397267 | Niveau 00 - 01 | yes
1397284 | Niveau 00 - 01 | yes
1397551 | Niveau 00 - 01 | yes
1404576 | Niveau 00 - 01 | no
1498388 | Niveau 00 - 01 | no

# IfcWallStandardCase: Mur de base:@_Générique - Int. 60 mm (3)
In: Niveau 00 - 02
Type - PredefinedType: STANDARD; Material: FP - Peinture bleu 0.06 m
Type - Pset_QuantityTakeOff - Reference: @_Générique - Int. 60 mm
Type - Pset_ReinforcementBarPitchOfWall - Reference: @_Générique - Int. 60 mm
Type - Pset_WallCommon - IsExternal: no; Reference: @_Générique - Int. 60 mm
Pset_QuantityTakeOff - sets with these values: 2
Pset_WallCommon - ExtendToStructure: no; LoadBearing: no
Name (Mur de base:@_Générique - Int. 60 mm:...)
1109007
1109496
1109536

# IfcWallStandardCase: Mur de base:@_Générique - Int. 70 mm (68)
Type - PredefinedType: STANDARD; Material: Mur par défaut 0.07 m
Type - Pset_QuantityTakeOff - Reference: @_Générique - Int. 70 mm
Type - Pset_ReinforcementBarPitchOfWall - Reference: @_Générique - Int. 70 mm
Type - Pset_WallCommon - IsExternal: no; Reference: @_Générique - Int. 70 mm
Pset_QuantityTakeOff - sets with these values: 2
Pset_WallCommon - LoadBearing: no
Name (Mur de base:@_Générique - Int. 70 mm:...) | In | ExtendToStructure
971539 | Niveau 2 | yes
971553 | Niveau 2 | yes
971567 | Niveau 2 | yes
971568 | Niveau 2 | yes
971569 | Niveau 2 | yes
971571 | Niveau 2 | yes
971942 | Niveau 00 - 01 | yes
971943 | Niveau 00 - 01 | yes
971944 | Niveau 00 - 01 | yes
971945 | Niveau 00 - 01 | yes
971946 | Niveau 00 - 01 | yes
971947 | Niveau 00 - 01 | yes
971948 | Niveau 00 - 01 | yes
971949 | Niveau 00 - 01 | yes
976032 | SOUS SOL | no
976033 | SOUS SOL | no
1204233 | Niveau 2 | yes
1248605 | Niveau 1 | yes
1248979 | Niveau 1 | yes
1249080 | Niveau 1 | yes
1250054 | Niveau 1 | yes
1250146 | Niveau 1 | yes
1250430 | Niveau 1 | yes
1250787 | Niveau 1 | yes
1250838 | Niveau 1 | yes
1250965 | Niveau 1 | yes
1251168 | Niveau 1 | yes
1251589 | Niveau 1 | yes
1251915 | Niveau 1 | yes
1252003 | Niveau 1 | yes
1255202 | Niveau 1 | yes
1255236 | Niveau 1 | yes
1281607 | Niveau 1 | yes
1291528 | Niveau 1 | yes
1292544 | Niveau 2 | yes
1292678 | Niveau 2 | yes
1292730 | Niveau 2 | yes
1294201 | Niveau 2 | no
1294203 | Niveau 2 | no
1294204 | Niveau 2 | no
1294368 | Niveau 2 | no
1294369 | Niveau 2 | no
1294370 | Niveau 2 | no
1337056 | Niveau 00 - 02 | no
1337400 | Niveau 00 - 02 | no
1337497 | Niveau 00 - 02 | yes
1337752 | Niveau 00 - 02 | no
1337968 | Niveau 00 - 02 | yes
1349628 | Niveau 00 - 02 | no
1349723 | Niveau 00 - 02 | no
1358108 | Niveau 00 - 02 | no
1358164 | Niveau 00 - 02 | no
1395364 | Niveau 00 - 02 | yes
1399809 | Niveau 00 | yes
1410719 | Niveau 00 - 01 | yes
1410790 | Niveau 00 - 01 | yes
1410960 | Niveau 00 - 01 | yes
1411078 | Niveau 00 - 01 | yes
1411308 | Niveau 00 - 01 | yes
1411421 | Niveau 00 - 01 | yes
1411673 | Niveau 00 - 01 | yes
1413371 | Niveau 00 - 01 | yes
1413485 | Niveau 00 - 01 | yes
1448223 | Niveau 1 | yes
1487482 | Niveau 00 - 01 | no
1487578 | Niveau 00 - 01 | no
1534273 | Niveau 2 | no
1534372 | Niveau 2 | no

# IfcWallStandardCase: Mur de base:@_Générique - Int. 80 mm (3)
In: Niveau 00 - 02
Type - PredefinedType: STANDARD; Material: Mur par défaut 0.08 m
Type - Pset_QuantityTakeOff - Reference: @_Générique - Int. 80 mm
Type - Pset_ReinforcementBarPitchOfWall - Reference: @_Générique - Int. 80 mm
Type - Pset_WallCommon - IsExternal: no; Reference: @_Générique - Int. 80 mm
Pset_QuantityTakeOff - sets with these values: 2
Pset_WallCommon - LoadBearing: no
Name (Mur de base:@_Générique - Int. 80 mm:...) | ExtendToStructure
1336500 | yes
1337826 | no
1338034 | yes

# IfcWallStandardCase: Mur de base:Ext. Mur 250+enduit Rouge (7)
Type - PredefinedType: STANDARD; Material: Maçonnerie - Voile BA rouge 0.24 m, @_Enduit Pierre 0.01 m
Type - Pset_QuantityTakeOff - Reference: Ext. Mur 250+enduit Rouge
Type - Pset_ReinforcementBarPitchOfWall - Reference: Ext. Mur 250+enduit Rouge
Type - Pset_WallCommon - IsExternal: no; Reference: Ext. Mur 250+enduit Rouge
Pset_QuantityTakeOff - sets with these values: 2
Pset_WallCommon - IsExternal: yes; ExtendToStructure: no; LoadBearing: no
Name (Mur de base:Ext. Mur 250+enduit Rouge:...) | In
971290 | Niveau 1
971291 | Niveau 1
971386 | Niveau 2
971387 | Niveau 2
971388 | Niveau 2
971389 | Niveau 2
1106182 | Niveau 1

# IfcWallStandardCase: Mur de base:Ext. Voile BA 150 (86)
Type - PredefinedType: STANDARD; Material: Maçonnerie - Voile BA 0.15 m
Type - Pset_QuantityTakeOff - Reference: Ext. Voile BA 150
Type - Pset_ReinforcementBarPitchOfWall - Reference: Ext. Voile BA 150
Type - Pset_WallCommon - IsExternal: no; Reference: Ext. Voile BA 150
Pset_QuantityTakeOff - sets with these values: 2
Pset_WallCommon - IsExternal: yes; LoadBearing: no
Name (Mur de base:Ext. Voile BA 150:...) | In | ExtendToStructure
970906 | Niveau 00 - 01 | yes
970916 | Niveau 00 - 02 | no
970917 | Niveau 00 - 02 | no
970918 | Niveau 00 - 02 | yes
970919 | Niveau 00 - 01 | yes
970920 | Niveau 00 - 02 | no
970921 | Niveau 00 - 02 | yes
970922 | Niveau 00 - 01 | yes
970923 | Niveau 00 - 01 | yes
970928 | Niveau 00 - 02 | yes
970931 | Niveau 00 - 01 | yes
970935 | Niveau 00 - 01 | no
970938 | Niveau 00 - 01 | yes
970939 | Niveau 00 - 01 | yes
970940 | Niveau 00 - 01 | yes
970941 | Niveau 00 - 01 | yes
970942 | Niveau 00 - 01 | yes
970955 | Niveau 00 - 01 | yes
970956 | Niveau 00 - 01 | yes
970957 | Niveau 00 - 01 | yes
970958 | Niveau 00 - 01 | yes
970959 | Niveau 00 - 01 | yes
970960 | Niveau 00 - 01 | yes
970961 | Niveau 00 - 01 | yes
970962 | Niveau 00 - 01 | yes
970963 | Niveau 00 - 01 | yes
970964 | Niveau 00 - 01 | no
970965 | Niveau 00 - 01 | yes
970966 | Niveau 00 - 01 | yes
970967 | Niveau 00 - 01 | yes
970990 | Niveau 00 - 02 | yes
971297 | Niveau 1 | yes
971298 | Niveau 1 | no
971300 | Niveau 1 | yes
971302 | Niveau 1 | yes
971303 | Niveau 1 | yes
971304 | Niveau 1 | no
971305 | Niveau 1 | yes
971306 | Niveau 1 | yes
971308 | Niveau 1 | yes
971310 | Niveau 1 | yes
971320 | Niveau 1 | yes
971326 | Niveau 1 | yes
971327 | Niveau 1 | yes
971328 | Niveau 1 | yes
971330 | Niveau 1 | yes
971331 | Niveau 1 | yes
971332 | Niveau 1 | yes
971336 | Niveau 1 | yes
971337 | Niveau 1 | yes
971339 | Niveau 1 | yes
971345 | Niveau 1 | yes
971394 | Niveau 2 | yes
971399 | Niveau 2 | no
971400 | Niveau 2 | yes
971402 | Niveau 2 | yes
971404 | Niveau 2 | yes
971406 | Niveau 2 | yes
971422 | Niveau 2 | yes
971423 | Niveau 2 | yes
971428 | Niveau 2 | yes
971429 | Niveau 2 | no
971437 | Niveau 2 | yes
971549 | Niveau 2 | yes
971579 | Niveau 2 | yes
971580 | Niveau 2 | yes
971960 | Niveau 00 - 02 | no
1204680 | Niveau 2 | yes
1206294 | Niveau 2 | yes
1242212 | Niveau 1 | yes
1242367 | Niveau 1 | yes
1253209 | Niveau 1 | yes
1259714 | Niveau 00 - 01 | no
1262292 | Niveau 00 - 02 | yes
1262798 | Niveau 00 | yes
1262911 | Niveau 00 | no
1267839 | Niveau 00 - 01 | no
1273604 | Niveau 1 | yes
1308860 | Niveau 00 - 01 | yes
1309028 | Niveau 00 - 01 | yes
1393862 | Niveau 00 - 01 | no
1394032 | Niveau 00 - 01 | yes
1394190 | Niveau 00 - 01 | yes
1394236 | Niveau 00 - 01 | yes
1395145 | Niveau 00 - 01 | yes
1492436 | Niveau 00 - 02 | yes

# IfcWallStandardCase: Mur de base:Ext. Voile BA 160 (4)
Type - PredefinedType: STANDARD; Material: Maçonnerie - Voile BA 0.16 m
Type - Pset_QuantityTakeOff - Reference: Ext. Voile BA 160
Type - Pset_ReinforcementBarPitchOfWall - Reference: Ext. Voile BA 160
Type - Pset_WallCommon - IsExternal: no; Reference: Ext. Voile BA 160
Pset_QuantityTakeOff - sets with these values: 2
Pset_WallCommon - IsExternal: yes; LoadBearing: no; ExtendToStructure: yes
Name (Mur de base:Ext. Voile BA 160:...) | In
970932 | Niveau 00 - 02
1045564 | Niveau 00 - 03
1045565 | Niveau 00 - 03
1094875 | Niveau 00 - 03

# IfcWallStandardCase: Mur de base:Ext. Voile BA 180 (3)
In: SOUS SOL
Type - PredefinedType: STANDARD; Material: Maçonnerie - Voile BA 0.18 m
Type - Pset_QuantityTakeOff - Reference: Ext. Voile BA 180
Type - Pset_ReinforcementBarPitchOfWall - Reference: Ext. Voile BA 180
Type - Pset_WallCommon - IsExternal: no; Reference: Ext. Voile BA 180
Pset_QuantityTakeOff - sets with these values: 2
Pset_WallCommon - IsExternal: yes; ExtendToStructure: no; LoadBearing: no
Name (Mur de base:Ext. Voile BA 180:...)
971961
1096028
1100429

# IfcWallStandardCase: Mur de base:Ext. Voile BA 200 (101)
Type - PredefinedType: STANDARD; Material: Maçonnerie - Voile BA 0.2 m
Type - Pset_QuantityTakeOff - Reference: Ext. Voile BA 200
Type - Pset_ReinforcementBarPitchOfWall - Reference: Ext. Voile BA 200
Type - Pset_WallCommon - IsExternal: no; Reference: Ext. Voile BA 200
Pset_QuantityTakeOff - sets with these values: 2
Pset_WallCommon - IsExternal: yes; LoadBearing: no
Name (Mur de base:Ext. Voile BA 200:...) | In | ExtendToStructure
970884 | Niveau 00 - 02 | no
970889 | Niveau 00 - 01 | no
970895 | Niveau 00 - 01 | yes
970896 | Niveau 00 - 01 | yes
970898 | Niveau 00 - 01 | yes
970905 | Niveau 00 - 01 | yes
970907 | Niveau 00 - 01 | yes
970908 | Niveau 00 - 01 | yes
970909 | Niveau 00 - 01 | yes
970910 | Niveau 00 - 01 | yes
970911 | Niveau 00 - 01 | yes
970912 | Niveau 00 - 01 | yes
970913 | Niveau 00 - 01 | yes
970914 | Niveau 00 - 01 | yes
970915 | Niveau 00 - 01 | yes
970943 | Niveau 00 - 01 | yes
970944 | Niveau 00 - 01 | yes
970953 | Niveau 00 - 01 | yes
970954 | Niveau 00 - 01 | yes
970968 | Niveau 00 - 01 | yes
970993 | Niveau 00 - 01 | yes
970995 | Niveau 00 - 01 | yes
970996 | Niveau 00 - 01 | yes
971293 | Niveau 1 | yes
971333 | Niveau 1 | yes
971414 | Niveau 2 | yes
971418 | Niveau 2 | yes
971462 | Niveau 3 - 01 | no
971463 | Niveau 3 - 01 | no
971464 | Niveau 3 - 01 | no
971465 | Niveau 3 - 01 | no
971466 | Niveau 3 - 01 | no
971467 | Niveau 3 - 01 | no
971468 | Niveau 3 - 01 | no
971524 | Niveau 2 | yes
971525 | Niveau 2 | yes
971528 | Niveau 2 | yes
971532 | Niveau 2 | yes
971533 | Niveau 2 | yes
971537 | Niveau 2 | yes
971538 | Niveau 2 | yes
971541 | Niveau 2 | yes
971542 | Niveau 2 | yes
971546 | Niveau 2 | yes
971552 | Niveau 2 | yes
971554 | Niveau 2 | yes
971558 | Niveau 2 | yes
971561 | Niveau 2 | yes
971563 | Niveau 2 | yes
971570 | Niveau 2 | yes
971572 | Niveau 2 | yes
971939 | Niveau 00 - 01 | no
971952 | SOUS SOL | no
971956 | SOUS SOL | yes
971957 | SOUS SOL | yes
975517 | SOUS SOL | no
1035117 | SOUS SOL | no
1107314 | Niveau 00 - 02 | no
1204471 | Niveau 2 | yes
1229053 | Niveau 3 - 02 | no
1242808 | Niveau 1 | yes
1244373 | Niveau 00 - 02 | no
1260366 | Niveau 00 - 01 | no
1270086 | Niveau 3 - 01 | no
1294856 | Niveau 2 | yes
1296514 | Niveau 2 | yes
1296572 | Niveau 2 | yes
1298526 | Niveau 1 - 01 | no
1299822 | Niveau 1 - 01 | no
1299823 | Niveau 1 - 01 | no
1300879 | Niveau 1 - 01 | no
1300880 | Niveau 1 - 01 | no
1300881 | Niveau 1 - 01 | no
1308132 | Niveau 1 - 01 | no
1308133 | Niveau 1 - 01 | no
1308174 | Niveau 1 - 01 | no
1328108 | Niveau 00 - 01 | yes
1329886 | Niveau 1 - 01 | no
1330116 | Niveau 1 - 01 | no
1330285 | Niveau 1 - 01 | no
1330430 | Niveau 1 - 01 | no
1330438 | Niveau 1 - 01 | no
1330537 | Niveau 1 - 01 | no
1330621 | Niveau 1 - 01 | no
1330655 | Niveau 1 - 01 | no
1330847 | Niveau 1 - 01 | no
1331064 | Niveau 1 - 01 | no
1331345 | Niveau 1 - 01 | no
1331405 | Niveau 1 - 01 | no
1331448 | Niveau 1 - 01 | no
1332334 | Niveau 1 - 01 | no
1332954 | Niveau 1 - 01 | no
1335005 | Niveau 1 - 01 | no
1336547 | Niveau 00 - 01 | yes
1336990 | Niveau 00 - 02 | yes
1337648 | Niveau 00 - 02 | yes
1338730 | Niveau 00 - 01 | yes
1360280 | Niveau 00 - 02 | no
1407800 | Niveau 00 - 01 | no
1407846 | Niveau 00 - 01 | yes
1532148 | Niveau 00 - 02 | no

# IfcWallStandardCase: Mur de base:Ext. Voile BA 200 Brique (15)
Type - PredefinedType: STANDARD; Material: Brique 55x220 0.01 m, Maçonnerie - Voile BA 0.2 m, Brique 55x220 0.01 m
Type - Pset_QuantityTakeOff - Reference: Ext. Voile BA 200 Brique
Type - Pset_ReinforcementBarPitchOfWall - Reference: Ext. Voile BA 200 Brique
Type - Pset_WallCommon - IsExternal: no; Reference: Ext. Voile BA 200 Brique
Pset_QuantityTakeOff - sets with these values: 2
Pset_WallCommon - IsExternal: yes; LoadBearing: no; ExtendToStructure: yes
Name (Mur de base:Ext. Voile BA 200 Brique:...) | In
970892 | Niveau 00 - 01
970893 | Niveau 00 - 01
971295 | Niveau 1
971296 | Niveau 1
971321 | Niveau 1
971323 | Niveau 1
971324 | Niveau 1
971325 | Niveau 1
971392 | Niveau 2
971393 | Niveau 2
971412 | Niveau 2
971545 | Niveau 2
971551 | Niveau 2
1238574 | Niveau 1
1248162 | Niveau 1

# IfcWallStandardCase: Mur de base:Ext. Voile BA 200 bleu (7)
In: Niveau 00 - 02
Type - PredefinedType: STANDARD; Material: FP - Peinture bleu 0.2 m
Type - Pset_QuantityTakeOff - Reference: Ext. Voile BA 200 bleu
Type - Pset_ReinforcementBarPitchOfWall - Reference: Ext. Voile BA 200 bleu
Type - Pset_WallCommon - IsExternal: no; Reference: Ext. Voile BA 200 bleu
Pset_QuantityTakeOff - sets with these values: 2
Pset_WallCommon - IsExternal: yes; ExtendToStructure: no; LoadBearing: no
Name (Mur de base:Ext. Voile BA 200 bleu:...)
971260
1004638
1004639
1104431
1107487
1107944
1110015

# IfcWallStandardCase: Mur de base:Ext. Voile BA 220 (11)
Type - PredefinedType: STANDARD; Material: Maçonnerie - Voile BA 0.22 m
Type - Pset_QuantityTakeOff - Reference: Ext. Voile BA 220
Type - Pset_ReinforcementBarPitchOfWall - Reference: Ext. Voile BA 220
Type - Pset_WallCommon - IsExternal: no; Reference: Ext. Voile BA 220
Pset_QuantityTakeOff - sets with these values: 2
Pset_WallCommon - IsExternal: yes; LoadBearing: no
Name (Mur de base:Ext. Voile BA 220:...) | In | ExtendToStructure
1006674 | Niveau 00 - 03 | no
1006675 | Niveau 00 | no
1006713 | Niveau 00 - 03 | no
1006832 | Niveau 00 - 03 | no
1006833 | Niveau 00 | no
1007001 | Niveau 00 - 03 | no
1007002 | Niveau 00 | no
1007003 | Niveau 00 - 03 | no
1007004 | Niveau 00 - 03 | no
1007005 | Niveau 00 | no
1496675 | Niveau 00 - 02 | yes

# IfcWallStandardCase: Mur de base:Ext. Voile BA 250 (21)
Type - PredefinedType: STANDARD; Material: Maçonnerie - Voile BA 0.25 m
Type - Pset_QuantityTakeOff - Reference: Ext. Voile BA 250
Type - Pset_ReinforcementBarPitchOfWall - Reference: Ext. Voile BA 250
Type - Pset_WallCommon - Reference: Ext. Voile BA 250; IsExternal: no
Pset_QuantityTakeOff - sets with these values: 2
Pset_WallCommon - IsExternal: yes; LoadBearing: no
Name (Mur de base:Ext. Voile BA 250:...) | In | ExtendToStructure
970849 | Niveau 00 - 01 | no
970850 | Niveau 00 - 01 | no
970851 | Niveau 00 - 01 | no
970852 | Niveau 00 - 01 | no
970853 | Niveau 00 - 01 | no
970854 | Niveau 00 - 01 | no
970855 | Niveau 00 - 01 | no
970856 | Niveau 00 - 01 | no
970857 | Niveau 00 - 01 | no
970858 | Niveau 00 - 01 | no
970873 | Niveau 00 - 01 | yes
970876 | Niveau 00 - 01 | yes
970878 | Niveau 00 - 01 | yes
970894 | Niveau 00 - 01 | yes
970897 | Niveau 00 - 01 | yes
970899 | Niveau 00 - 01 | no
970985 | Niveau 00 - 02 | yes
970986 | Niveau 00 - 02 | no
970988 | Niveau 00 - 02 | yes
970994 | Niveau 00 - 01 | yes
1333235 | Niveau 00 - 01 | no

# IfcWallStandardCase: Mur de base:Ext. Voile BA 300 (12)
Type - PredefinedType: STANDARD; Material: Maçonnerie - Voile BA 0.3 m
Type - Pset_QuantityTakeOff - Reference: Ext. Voile BA 300
Type - Pset_ReinforcementBarPitchOfWall - Reference: Ext. Voile BA 300
Type - Pset_WallCommon - IsExternal: no; Reference: Ext. Voile BA 300
Pset_QuantityTakeOff - sets with these values: 2
Pset_WallCommon - IsExternal: yes; LoadBearing: no
Name (Mur de base:Ext. Voile BA 300:...) | In | ExtendToStructure
970890 | Niveau 00 - 01 | no
970900 | Niveau 00 - 01 | yes
970945 | Niveau 00 - 01 | yes
1087579 | Niveau 00 - 02 | no
1395855 | Niveau 00 - 02 | no
1395938 | Niveau 00 - 02 | no
1396078 | Niveau 00 - 02 | no
1396392 | Niveau 00 - 02 | yes
1396593 | Niveau 00 - 02 | yes
1528822 | Niveau 00 - 02 | no
1529051 | Niveau 00 - 02 | no
1529255 | Niveau 00 - 02 | no

# IfcWallStandardCase: Mur de base:Ext. Voile BA 350, Mur de base:Ext. Voile BA 350:1492740
In: Niveau 00 - 02
Type - PredefinedType: STANDARD; Material: Maçonnerie - Voile BA 0.35 m
Type - Pset_QuantityTakeOff - Reference: Ext. Voile BA 350
Type - Pset_ReinforcementBarPitchOfWall - Reference: Ext. Voile BA 350
Type - Pset_WallCommon - IsExternal: no; Reference: Ext. Voile BA 350
Pset_QuantityTakeOff - sets with these values: 2
Pset_WallCommon - IsExternal: yes; LoadBearing: no; ExtendToStructure: yes

# IfcWallStandardCase: Mur de base:Ext. Voile BA 400 (3)
Type - PredefinedType: STANDARD; Material: Maçonnerie - Voile BA 0.4 m
Type - Pset_QuantityTakeOff - Reference: Ext. Voile BA 400
Type - Pset_ReinforcementBarPitchOfWall - Reference: Ext. Voile BA 400
Type - Pset_WallCommon - IsExternal: no; Reference: Ext. Voile BA 400
Pset_QuantityTakeOff - sets with these values: 2
Pset_WallCommon - IsExternal: yes; LoadBearing: no
Name (Mur de base:Ext. Voile BA 400:...) | In | ExtendToStructure
970891 | Niveau 00 - 01 | yes
970901 | Niveau 00 - 01 | no
1112307 | Niveau 00 - 02 | yes

# IfcWallStandardCase: Mur de base:Mur 100- isolation 100 - enduit (2)
Type - PredefinedType: STANDARD; Material: @_Enduit Pierre 0.01 m, Maçonnerie - Isolant 0.09 m, Maçonnerie - Voile BA 0.1 m
Type - Pset_QuantityTakeOff - Reference: Mur 100- isolation 100 - enduit
Type - Pset_ReinforcementBarPitchOfWall - Reference: Mur 100- isolation 100 - enduit
Type - Pset_WallCommon - IsExternal: no; Reference: Mur 100- isolation 100 - enduit
Pset_QuantityTakeOff - sets with these values: 2
Pset_WallCommon - IsExternal: yes; LoadBearing: no; ExtendToStructure: yes
Name (Mur de base:Mur 100- isolation 100 - enduit:...) | In
970883 | Niveau 00 - 02
1104036 | Niveau 00

# IfcWallStandardCase: Mur de base:Mur Blanc 150- isolation 50 (2)
In: Niveau 00 - 01
Type - PredefinedType: STANDARD; Material: Maçonnerie - Isolant 0.05 m, béton gris 0.15 m
Type - Pset_QuantityTakeOff - Reference: Mur Blanc 150- isolation 50
Type - Pset_ReinforcementBarPitchOfWall - Reference: Mur Blanc 150- isolation 50
Type - Pset_WallCommon - IsExternal: no; Reference: Mur Blanc 150- isolation 50
Pset_QuantityTakeOff - sets with these values: 2
Pset_WallCommon - IsExternal: yes; ExtendToStructure: no; LoadBearing: no
Name (Mur de base:Mur Blanc 150- isolation 50:...)
970859
970879

# IfcWallStandardCase: Mur de base:Mur EXE 150- Hach, Mur de base:Mur EXE 150- Hach:971272
In: Niveau 00 - 03
Type - PredefinedType: STANDARD; Material: Finition vertical béton 0.02 m, Maçonnerie - Voile BA 0.15 m
Type - Pset_QuantityTakeOff - Reference: Mur EXE 150- Hach
Type - Pset_ReinforcementBarPitchOfWall - Reference: Mur EXE 150- Hach
Type - Pset_WallCommon - IsExternal: no; Reference: Mur EXE 150- Hach
Pset_QuantityTakeOff - sets with these values: 2
Pset_WallCommon - IsExternal: yes; ExtendToStructure: no; LoadBearing: no

# IfcWallStandardCase: Mur de base:Mur EXE 200- Hach (20)
Type - PredefinedType: STANDARD; Material: Finition vertical béton 0.03 m, Maçonnerie - Voile BA 0.17 m
Type - Pset_QuantityTakeOff - Reference: Mur EXE 200- Hach
Type - Pset_ReinforcementBarPitchOfWall - Reference: Mur EXE 200- Hach
Type - Pset_WallCommon - IsExternal: no; Reference: Mur EXE 200- Hach
Pset_QuantityTakeOff - sets with these values: 2
Pset_WallCommon - IsExternal: yes; ExtendToStructure: no; LoadBearing: no
Name (Mur de base:Mur EXE 200- Hach:...) | In
971255 | Niveau 00
971256 | Niveau 00
971262 | Niveau 00
971268 | Niveau 00 - 03
971270 | SOUS SOL
971271 | Niveau 00 - 03
971480 | Niveau 1 - 03
971481 | Niveau 1 - 03
978647 | Niveau 1 - 03
1004163 | SOUS SOL
1004967 | Niveau 00 - 02
1005205 | Niveau 00 - 02
1035636 | Niveau 00 - 03
1102091 | Niveau 00 - 01
1103696 | Niveau 00 - 01
1103922 | Niveau 00
1104243 | Niveau 00 - 02
1105061 | Niveau 00 - 02
1105121 | Niveau 00 - 02
1244000 | Niveau 00 - 01

# IfcWallStandardCase: Mur de base:Mur EXE 250- Hach, Mur de base:Mur EXE 250- Hach:970984
In: Niveau 00 - 02
Type - PredefinedType: STANDARD; Material: Finition vertical béton 0.03 m, Maçonnerie - Voile BA 0.22 m
Type - Pset_QuantityTakeOff - Reference: Mur EXE 250- Hach
Type - Pset_ReinforcementBarPitchOfWall - Reference: Mur EXE 250- Hach
Type - Pset_WallCommon - IsExternal: no; Reference: Mur EXE 250- Hach
Pset_QuantityTakeOff - sets with these values: 2
Pset_WallCommon - IsExternal: yes; LoadBearing: no; ExtendToStructure: yes

# IfcWallStandardCase: Mur de base:Mur EXE 250- Hach 2 faces, Mur de base:Mur EXE 250- Hach 2 faces:1418915
In: Niveau 00 - 01
Type - PredefinedType: STANDARD; Material: Finition vertical béton 0.25 m
Type - Pset_QuantityTakeOff - Reference: Mur EXE 250- Hach 2 faces
Type - Pset_ReinforcementBarPitchOfWall - Reference: Mur EXE 250- Hach 2 faces
Type - Pset_WallCommon - IsExternal: no; Reference: Mur EXE 250- Hach 2 faces
Pset_QuantityTakeOff - sets with these values: 2
Pset_WallCommon - IsExternal: yes; ExtendToStructure: no; LoadBearing: no

# IfcWallStandardCase: Mur de base:Mur EXE 300- Hach 2 faces (3)
In: Niveau 00 - 02
Type - PredefinedType: STANDARD; Material: Finition vertical béton 0.3 m
Type - Pset_QuantityTakeOff - Reference: Mur EXE 300- Hach 2 faces
Type - Pset_ReinforcementBarPitchOfWall - Reference: Mur EXE 300- Hach 2 faces
Type - Pset_WallCommon - IsExternal: no; Reference: Mur EXE 300- Hach 2 faces
Pset_QuantityTakeOff - sets with these values: 2
Pset_WallCommon - IsExternal: yes; LoadBearing: no; ExtendToStructure: yes
Name (Mur de base:Mur EXE 300- Hach 2 faces:...)
1345445
1346014
1347167

# IfcWallStandardCase: Mur de base:Mur EXE 40- Hach (15)
Type - PredefinedType: STANDARD; Material: Finition vertical béton 0.04 m
Type - Pset_QuantityTakeOff - Reference: Mur EXE 40- Hach
Type - Pset_ReinforcementBarPitchOfWall - Reference: Mur EXE 40- Hach
Type - Pset_WallCommon - IsExternal: no; Reference: Mur EXE 40- Hach
Pset_QuantityTakeOff - sets with these values: 2
Pset_WallCommon - IsExternal: yes; ExtendToStructure: no; LoadBearing: no
Name (Mur de base:Mur EXE 40- Hach:...) | In
1058453 | Niveau 00
1059138 | Niveau 00 - 01
1059190 | Niveau 00
1059237 | Niveau 00
1059466 | Niveau 00 - 01
1059565 | Niveau 00
1059566 | Niveau 00
1334769 | Niveau 00 - 01
1335925 | Niveau 00
1336023 | Niveau 00 - 01
1338256 | Niveau 00 - 02
1338328 | Niveau 00
1389060 | Niveau 00 - 01
1390417 | Niveau 00 - 01
1392263 | Niveau 00 - 01

# IfcWallStandardCase: Mur de base:Mur EXE 530- Hach 2 faces (2)
In: Niveau 00 - 02
Type - PredefinedType: STANDARD; Material: Finition vertical béton 0.53 m
Type - Pset_QuantityTakeOff - Reference: Mur EXE 530- Hach 2 faces
Type - Pset_ReinforcementBarPitchOfWall - Reference: Mur EXE 530- Hach 2 faces
Type - Pset_WallCommon - IsExternal: no; Reference: Mur EXE 530- Hach 2 faces
Pset_QuantityTakeOff - sets with these values: 2
Pset_WallCommon - IsExternal: yes; ExtendToStructure: no; LoadBearing: no
Name (Mur de base:Mur EXE 530- Hach 2 faces:...)
1349059
1349258

# IfcWallStandardCase: Mur de base:Mur EXE 5350- Hach 2 faces (2)
In: Niveau 00 - 02
Type - PredefinedType: STANDARD; Material: Finition vertical béton 0.535 m
Type - Pset_QuantityTakeOff - Reference: Mur EXE 5350- Hach 2 faces
Type - Pset_ReinforcementBarPitchOfWall - Reference: Mur EXE 5350- Hach 2 faces
Type - Pset_WallCommon - IsExternal: no; Reference: Mur EXE 5350- Hach 2 faces
Pset_QuantityTakeOff - sets with these values: 2
Pset_WallCommon - IsExternal: yes; ExtendToStructure: no; LoadBearing: no
Name (Mur de base:Mur EXE 5350- Hach 2 faces:...)
1349456
1494390

# IfcWallStandardCase: Mur de base:Mur EXE 800- Hach 2 faces, Mur de base:Mur EXE 800- Hach 2 faces:1344156
In: Niveau 00 - 02
Type - PredefinedType: STANDARD; Material: Finition vertical béton 0.8 m
Type - Pset_QuantityTakeOff - Reference: Mur EXE 800- Hach 2 faces
Type - Pset_ReinforcementBarPitchOfWall - Reference: Mur EXE 800- Hach 2 faces
Type - Pset_WallCommon - IsExternal: no; Reference: Mur EXE 800- Hach 2 faces
Pset_QuantityTakeOff - sets with these values: 2
Pset_WallCommon - IsExternal: yes; LoadBearing: no; ExtendToStructure: yes

# IfcWallStandardCase: Mur de base:Mur en verre 70 (24)
Type - PredefinedType: STANDARD; Material: Verre 0.07 m
Type - Pset_QuantityTakeOff - Reference: Mur en verre 70
Type - Pset_ReinforcementBarPitchOfWall - Reference: Mur en verre 70
Type - Pset_WallCommon - IsExternal: no; Reference: Mur en verre 70; ThermalTransmittance: 15.7143 kg/K/s3
Pset_QuantityTakeOff - sets with these values: 2
Pset_WallCommon - IsExternal: yes; LoadBearing: no
Name (Mur de base:Mur en verre 70:...) | In | ExtendToStructure
970864 | Niveau 00 - 03 | no
970969 | Niveau 00 - 01 | yes
970970 | Niveau 00 - 01 | yes
1039164 | Niveau 00 - 03 | no
1039199 | Niveau 00 - 03 | no
1039605 | Niveau 00 - 03 | no
1039891 | Niveau 00 - 03 | no
1040016 | Niveau 00 - 03 | no
1040267 | Niveau 00 - 03 | no
1040268 | Niveau 00 - 03 | no
1046246 | Niveau 00 - 03 | no
1239716 | Niveau 1 | yes
1239878 | Niveau 1 | yes
1239909 | Niveau 1 | yes
1239959 | Niveau 1 | yes
1246836 | Niveau 1 | yes
1247103 | Niveau 1 | yes
1248886 | Niveau 1 | yes
1250257 | Niveau 1 | no
1264388 | Niveau 1 | yes
1265348 | Niveau 1 | no
1290608 | Niveau 1 | no
1291453 | Niveau 1 | no
1291892 | Niveau 1 | yes

# IfcWindow: 2 Vantaux:200 x 160 (6)
In: Niveau 00 - 01
Type - ParameterTakesPrecedence: no; Sizeable: no; Material: Bois - Mélèze d'Amérique (2), Métal - Aluminium anodisé, Métal - Laiton satiné, Bois - Pin
Type - Pset_QuantityTakeOff - Reference: 200 x 160
Type - Pset_WindowCommon - IsExternal: no; Reference: 200 x 160
OverallHeight: 1.645 m; OverallWidth: 2.02135 m; Material: Métal - Laiton satiné, Bois - Mélèze d'Amérique, Verre, Bois - Pin
Pset_WindowCommon - IsExternal: yes
Name (2 Vantaux:200 x 160:...)
1386262
1386346
1386380
1386462
1387109
1387151

# IfcWindow: 2 Vantaux:200 x 160 (16)
In: Niveau 00 - 01
Type - ParameterTakesPrecedence: no; Sizeable: no; Material: Métal - Aluminium anodisé, Métal - Laiton satiné, Bois - Pin, Bois - Mélèze d'Amérique (2)
Type - Pset_QuantityTakeOff - Reference: 200 x 160
Type - Pset_WindowCommon - IsExternal: no; Reference: 200 x 160
OverallHeight: 1.645 m; OverallWidth: 2.02135 m; Material: Métal - Laiton satiné, Bois - Mélèze d'Amérique, Verre, Bois - Pin
Pset_WindowCommon - IsExternal: yes
Name (2 Vantaux:200 x 160:...)
1380594
1381062
1381072
1383924
1383963
1384549
1385381
1385416
1385444
1385607
1385705
1385757
1385869
1385909
1385995
1386029

# IfcWindow: 2 Vantaux:280 x 220h, 2 Vantaux:280 x 220h:1392582
In: Niveau 00 - 01
Type - ParameterTakesPrecedence: no; Sizeable: no; Material: Métal - Aluminium anodisé, Bois - Mélèze d'Amérique (2), Bois - Pin, Métal - Laiton satiné
Type - Pset_QuantityTakeOff - Reference: 280 x 220h
Type - Pset_WindowCommon - IsExternal: no; Reference: 280 x 220h
OverallHeight: 2.245 m; OverallWidth: 2.82135 m; Material: Métal - Laiton satiné, Bois - Mélèze d'Amérique, Verre, Bois - Pin
Pset_WindowCommon - IsExternal: yes

# IfcWindow: 3 Vantaux:180 x500, 3 Vantaux:180 x500:1367154
In: Niveau 00 - 01
Type - ParameterTakesPrecedence: no; Sizeable: no; Material: Bois - Pin, Métal - Aluminium anodisé, Bois - Mélèze d'Amérique (2), Métal - Laiton satiné
Type - Pset_QuantityTakeOff - Reference: 180 x500
Type - Pset_WindowCommon - IsExternal: no; Reference: 180 x500
OverallHeight: 1.845 m; OverallWidth: 5.02135 m; Material: Métal - Laiton satiné, Bois - Mélèze d'Amérique, Verre, Bois - Pin
Pset_WindowCommon - IsExternal: yes

# IfcWindow: 3 Vantaux:190x440 (2)
In: Niveau 00 - 01
Type - ParameterTakesPrecedence: no; Sizeable: no; Material: Bois - Pin, Métal - Aluminium anodisé, Métal - Laiton satiné, Bois - Mélèze d'Amérique (2)
Type - Pset_QuantityTakeOff - Reference: 190x440
Type - Pset_WindowCommon - IsExternal: no; Reference: 190x440
OverallHeight: 1.945 m; OverallWidth: 4.42135 m; Material: Métal - Laiton satiné, Bois - Mélèze d'Amérique, Verre, Bois - Pin
Pset_OpeningElementCommon - Reference: 190x440; sets with these values: 2
Name (3 Vantaux:190x440:...)
1371893
1373091

# IfcWindow: Fenêtre 2 Vantaux:1750 x 75 (13)
In: Niveau 1
Type - ParameterTakesPrecedence: no; Sizeable: no; Material: Métal - Laiton satiné, Bois - Mélèze d'Amérique (2), Bois - Pin, Métal - Aluminium anodisé
Type - Pset_QuantityTakeOff - Reference: 1750 x 75
Type - Pset_WindowCommon - IsExternal: no; Reference: 1750 x 75
OverallHeight: 0.795 m; OverallWidth: 1.77135 m; Material: Métal - Laiton satiné, Bois - Mélèze d'Amérique, Verre, Bois - Pin
Pset_WindowCommon - IsExternal: yes
Name (Fenêtre 2 Vantaux:1750 x 75:...)
1300279
1300594
1300605
1300616
1300629
1300933
1300934
1300935
1300936
1300937
1308163
1308164
1308165

# IfcWindow: Fenêtre 2 Vantaux:280 x 100 cm (2)
In: SOUS SOL
Type - ParameterTakesPrecedence: no; Sizeable: no; Material: Bois - Pin, Bois - Mélèze d'Amérique (2), Métal - Aluminium anodisé, Métal - Laiton satiné
Type - Pset_QuantityTakeOff - Reference: 280 x 100 cm
Type - Pset_WindowCommon - IsExternal: no; Reference: 280 x 100 cm
OverallHeight: 1.045 m; OverallWidth: 2.82135 m; Material: Métal - Laiton satiné, Bois - Mélèze d'Amérique, Verre, Bois - Pin
Name (Fenêtre 2 Vantaux:280 x 100 cm:...)
1100107
1100486

# IfcWindow: Fenêtre type 1:1.9000 x 145cm, Fenêtre type 1:1.9000 x 145cm:1372431
In: Niveau 00 - 01
Type - ParameterTakesPrecedence: no; Sizeable: no; Material: Aluminium laqué - Blanc (3), Bois - Pin
Type - Pset_QuantityTakeOff - Reference: 1.9000 x 145cm
Type - Pset_WindowCommon - IsExternal: no; Reference: 1.9000 x 145cm
OverallHeight: 1.9 m; OverallWidth: 1.45 m; Material: Aluminium laqué - Blanc, Verre, Bois - Pin
Pset_WindowCommon - IsExternal: yes

# IfcWindow: Fenêtre type 1:115 x 155 cm (93)
Type - ParameterTakesPrecedence: no; Sizeable: no; Material: Aluminium laqué - Blanc (3), Bois - Pin
Type - Pset_QuantityTakeOff - Reference: 115 x 155 cm
Type - Pset_WindowCommon - IsExternal: no; Reference: 115 x 155 cm
OverallHeight: 1.55 m; OverallWidth: 1.15 m; Material: Aluminium laqué - Blanc, Verre, Bois - Pin
Pset_WindowCommon - IsExternal: yes
Name (Fenêtre type 1:115 x 155 cm:...) | In
1078586 | Niveau 1
1079149 | Niveau 2
1081261 | Niveau 1
1081262 | Niveau 2
1081279 | Niveau 1
1081295 | Niveau 1
1081296 | Niveau 2
1081311 | Niveau 1
1081312 | Niveau 2
1081329 | Niveau 1
1081330 | Niveau 2
1081362 | Niveau 1
1081363 | Niveau 2
1081398 | Niveau 1
1081399 | Niveau 2
1081415 | Niveau 1
1081416 | Niveau 2
1081447 | Niveau 1
1081448 | Niveau 2
1081479 | Niveau 1
1081480 | Niveau 2
1130165 | Niveau 1
1130225 | Niveau 1
1130313 | Niveau 2
1130411 | Niveau 2
1131023 | Niveau 1
1131024 | Niveau 1
1131025 | Niveau 2
1131026 | Niveau 2
1131044 | Niveau 1
1131045 | Niveau 1
1131046 | Niveau 2
1131047 | Niveau 2
1131065 | Niveau 1
1131066 | Niveau 1
1131067 | Niveau 2
1131068 | Niveau 2
1131086 | Niveau 1
1131087 | Niveau 1
1131088 | Niveau 2
1131089 | Niveau 2
1131107 | Niveau 1
1131108 | Niveau 1
1131109 | Niveau 2
1131110 | Niveau 2
1131130 | Niveau 1
1131131 | Niveau 1
1131132 | Niveau 2
1131133 | Niveau 2
1135097 | Niveau 2
1135189 | Niveau 1
1135551 | Niveau 2
1135552 | Niveau 1
1135632 | Niveau 2
1135633 | Niveau 1
1135634 | Niveau 2
1135635 | Niveau 1
1135655 | Niveau 2
1135656 | Niveau 1
1135657 | Niveau 2
1135658 | Niveau 1
1135677 | Niveau 2
1135678 | Niveau 1
1135679 | Niveau 2
1135680 | Niveau 1
1135696 | Niveau 2
1135697 | Niveau 1
1135698 | Niveau 2
1135699 | Niveau 1
1135905 | Niveau 1
1135967 | Niveau 2
1136241 | Niveau 1
1136242 | Niveau 2
1136257 | Niveau 1
1136258 | Niveau 2
1136273 | Niveau 1
1136274 | Niveau 2
1136295 | Niveau 1
1136296 | Niveau 2
1136311 | Niveau 1
1136312 | Niveau 2
1136327 | Niveau 1
1136328 | Niveau 2
1136344 | Niveau 1
1136345 | Niveau 2
1136476 | Niveau 1
1136477 | Niveau 2
1136478 | Niveau 1
1136479 | Niveau 2
1136495 | Niveau 1
1136496 | Niveau 2
1136497 | Niveau 1
1136498 | Niveau 2

# IfcWindow: Fenêtre type 1:116x 240 cm, Fenêtre type 1:116x 240 cm:1529254
In: Niveau 00 - 02
Type - ParameterTakesPrecedence: no; Sizeable: no; Material: Aluminium laqué - Blanc (3), Bois - Pin
Type - Pset_QuantityTakeOff - Reference: 116x 240 cm
Type - Pset_WindowCommon - IsExternal: no; Reference: 116x 240 cm
OverallHeight: 2.4 m; OverallWidth: 1.16 m; Material: Aluminium laqué - Blanc, Verre, Bois - Pin
Pset_WindowCommon - IsExternal: yes

# IfcWindow: Fenêtre type 1:120 x 125cm (2)
In: Niveau 00 - 02
Type - ParameterTakesPrecedence: no; Sizeable: no; Material: Aluminium laqué - Blanc (3), Bois - Pin
Type - Pset_QuantityTakeOff - Reference: 120 x 125cm
Type - Pset_WindowCommon - IsExternal: no; Reference: 120 x 125cm
OverallHeight: 1.25 m; OverallWidth: 1.2 m; Material: Aluminium laqué - Blanc, Verre, Bois - Pin
Pset_OpeningElementCommon - Reference: 120 x 125cm; sets with these values: 2
Name (Fenêtre type 1:120 x 125cm:...)
1348661
1348994

# IfcWindow: Fenêtre type 1:120 x 240 cm (2)
In: Niveau 00 - 02
Type - ParameterTakesPrecedence: no; Sizeable: no; Material: Aluminium laqué - Blanc (3), Bois - Pin
Type - Pset_QuantityTakeOff - Reference: 120 x 240 cm
Type - Pset_WindowCommon - IsExternal: no; Reference: 120 x 240 cm
OverallHeight: 2.4 m; OverallWidth: 1.2 m; Material: Aluminium laqué - Blanc, Verre, Bois - Pin
Pset_OpeningElementCommon - Reference: 120 x 240 cm; sets with these values: 2
Name (Fenêtre type 1:120 x 240 cm:...)
1340367
1340778

# IfcWindow: Fenêtre type 1:156 x 50cm, Fenêtre type 1:156 x 50cm:1358811
In: Niveau 00 - 02
Type - ParameterTakesPrecedence: no; Sizeable: no; Material: Bois - Pin, Aluminium laqué - Blanc (3)
Type - Pset_QuantityTakeOff - Reference: 156 x 50cm
Type - Pset_WindowCommon - IsExternal: no; Reference: 156 x 50cm
OverallHeight: 0.5 m; OverallWidth: 1.56 m; Material: Aluminium laqué - Blanc, Verre, Bois - Pin
Pset_OpeningElementCommon - Reference: 156 x 50cm; sets with these values: 2

# IfcWindow: Fenêtre type 1:195 x 240 cm, Fenêtre type 1:195 x 240 cm:1529050
In: Niveau 00 - 02
Type - ParameterTakesPrecedence: no; Sizeable: no; Material: Aluminium laqué - Blanc (3), Bois - Pin
Type - Pset_QuantityTakeOff - Reference: 195 x 240 cm
Type - Pset_WindowCommon - IsExternal: no; Reference: 195 x 240 cm
OverallHeight: 2.4 m; OverallWidth: 1.95 m; Material: Aluminium laqué - Blanc, Verre, Bois - Pin
Pset_WindowCommon - IsExternal: yes

# IfcWindow: Fenêtre type 1:200 x 220cm, Fenêtre type 1:200 x 220cm:1352954
In: Niveau 00 - 02
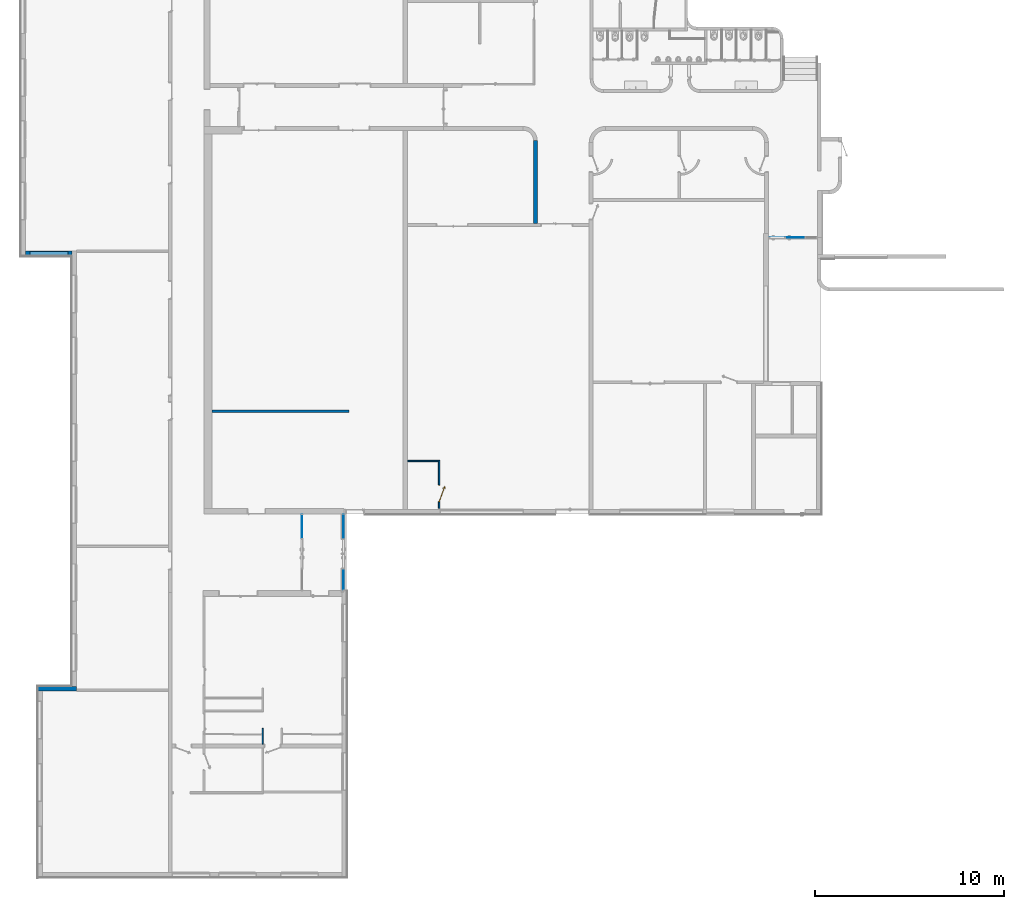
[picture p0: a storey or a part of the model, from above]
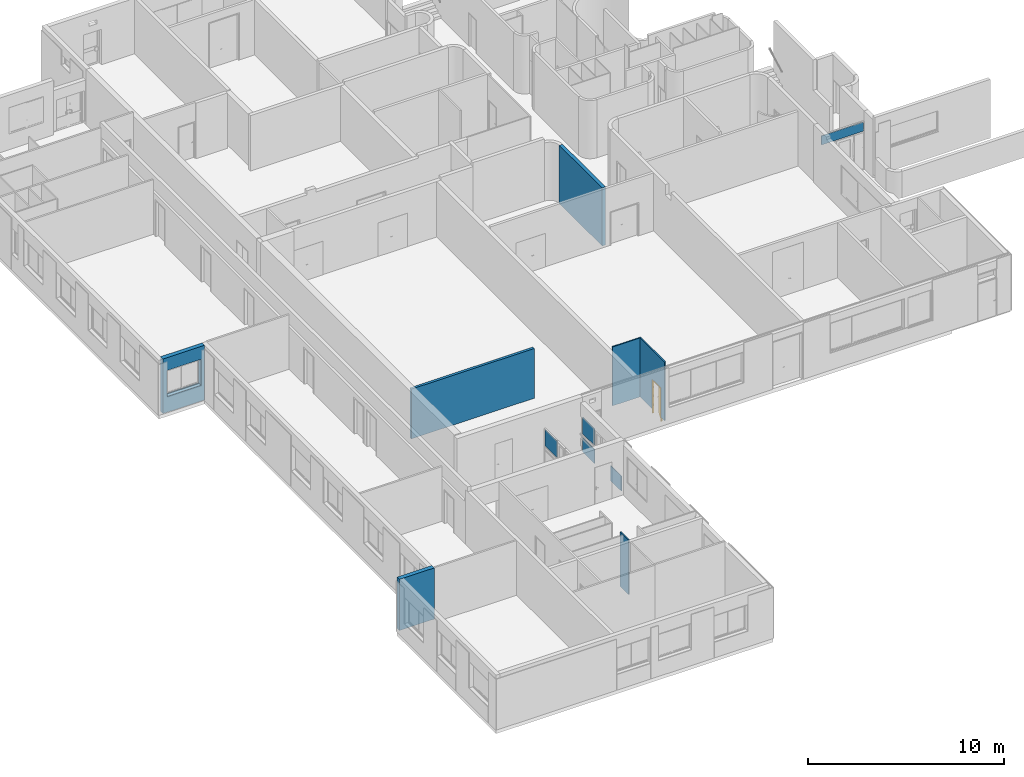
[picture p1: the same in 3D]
Properties of the parts of a building model (IFC2X3), part 4 of 4

# IfcWindow: Fenêtre type 1:200 x 220cm, Fenêtre type 1:200 x 220cm:1352954
Type - ParameterTakesPrecedence: no; Sizeable: no; Material: Aluminium laqué - Blanc (3), Bois - Pin
Type - Pset_QuantityTakeOff - Reference: 200 x 220cm
Type - Pset_WindowCommon - IsExternal: no; Reference: 200 x 220cm
OverallHeight: 2.2 m; OverallWidth: 2 m; Material: Aluminium laqué - Blanc, Verre, Bois - Pin
Pset_OpeningElementCommon - Reference: 200 x 220cm; sets with these values: 2

# IfcWindow: Fenêtre type 1:280 x 245 cm, Fenêtre type 1:280 x 245 cm:1357347
In: Niveau 00 - 02
Type - ParameterTakesPrecedence: no; Sizeable: no; Material: Aluminium laqué - Blanc (3), Bois - Pin
Type - Pset_QuantityTakeOff - Reference: 280 x 245 cm
Type - Pset_WindowCommon - IsExternal: no; Reference: 280 x 245 cm
OverallHeight: 2.4 m; OverallWidth: 2.83 m; Material: Aluminium laqué - Blanc, Verre, Bois - Pin
Pset_WindowCommon - IsExternal: yes

# IfcWindow: Fenêtre type 1:282 x 125 cm, Fenêtre type 1:282 x 125 cm:1361839
In: Niveau 00 - 02
Type - ParameterTakesPrecedence: no; Sizeable: no; Material: Aluminium laqué - Blanc (3), Bois - Pin
Type - Pset_QuantityTakeOff - Reference: 282 x 125 cm
Type - Pset_WindowCommon - IsExternal: no; Reference: 282 x 125 cm
OverallHeight: 1.25 m; OverallWidth: 2.82 m; Material: Aluminium laqué - Blanc, Verre, Bois - Pin
Pset_WindowCommon - IsExternal: yes

# IfcWindow: Fenêtre type 1:32 x 105 cm (3)
Type - ParameterTakesPrecedence: no; Sizeable: no; Material: Aluminium laqué - Blanc (3), Bois - Pin
Type - Pset_QuantityTakeOff - Reference: 32 x 105 cm
Type - Pset_WindowCommon - IsExternal: no; Reference: 32 x 105 cm
OverallHeight: 1.05 m; OverallWidth: 0.32 m; Material: Aluminium laqué - Blanc, Verre, Bois - Pin
Pset_WindowCommon - IsExternal: yes
Name (Fenêtre type 1:32 x 105 cm:...) | In
1101346 | Niveau 1
1101503 | Niveau 2
1101789 | Niveau 1 - 03

# IfcWindow: Fenêtre type 1:32 x 105 cm, Fenêtre type 1:32 x 105 cm:1101788
In: Niveau 00 - 03
Type - ParameterTakesPrecedence: no; Sizeable: no; Material: Bois - Pin, Aluminium laqué - Blanc (3)
Type - Pset_QuantityTakeOff - Reference: 32 x 105 cm
Type - Pset_WindowCommon - IsExternal: no; Reference: 32 x 105 cm
OverallHeight: 1.05 m; OverallWidth: 0.32 m; Material: Aluminium laqué - Blanc, Verre, Bois - Pin
Pset_OpeningElementCommon - Reference: 32 x 105 cm; sets with these values: 2

# IfcWindow: Fenêtre type 1:48 x 240 cm (7)
In: Niveau 00 - 02
Type - ParameterTakesPrecedence: no; Sizeable: no; Material: Bois - Pin, Aluminium laqué - Blanc (3)
Type - Pset_QuantityTakeOff - Reference: 48 x 240 cm
Type - Pset_WindowCommon - IsExternal: no; Reference: 48 x 240 cm
OverallHeight: 2.4 m; OverallWidth: 0.48 m; Material: Aluminium laqué - Blanc, Verre, Bois - Pin
Pset_OpeningElementCommon - Reference: 48 x 240 cm; sets with these values: 2
Name (Fenêtre type 1:48 x 240 cm:...)
1341198
1344157
1344158
1347128
1396241
1396670
1528821

# IfcWindow: Fenêtre type 1:550 x 245 cm, Fenêtre type 1:550 x 245 cm:1344159
In: Niveau 00 - 02
Type - ParameterTakesPrecedence: no; Sizeable: no; Material: Bois - Pin, Aluminium laqué - Blanc (3)
Type - Pset_QuantityTakeOff - Reference: 550 x 245 cm
Type - Pset_WindowCommon - IsExternal: no; Reference: 550 x 245 cm
OverallHeight: 2.4 m; OverallWidth: 5.5 m; Material: Aluminium laqué - Blanc, Verre, Bois - Pin
Pset_WindowCommon - IsExternal: yes

# IfcWindow: Fenêtre type 1:70 x 160cm (2)
In: Niveau 00
Type - ParameterTakesPrecedence: no; Sizeable: no; Material: Bois - Pin, Aluminium laqué - Blanc (3)
Type - Pset_QuantityTakeOff - Reference: 70 x 160cm
Type - Pset_WindowCommon - IsExternal: no; Reference: 70 x 160cm
OverallHeight: 1.6 m; OverallWidth: 0.7 m; Material: Aluminium laqué - Blanc, Verre, Bois - Pin
Pset_WindowCommon - IsExternal: yes
Name (Fenêtre type 1:70 x 160cm:...)
1386518
1386597

# IfcWindow: Fenêtre type 1:75 x 180cm, Fenêtre type 1:75 x 180cm:1357522
In: Niveau 00 - 02
Type - ParameterTakesPrecedence: no; Sizeable: no; Material: Bois - Pin, Aluminium laqué - Blanc (3)
Type - Pset_QuantityTakeOff - Reference: 75 x 180cm
Type - Pset_WindowCommon - IsExternal: no; Reference: 75 x 180cm
OverallHeight: 1.8 m; OverallWidth: 0.75 m; Material: Aluminium laqué - Blanc, Verre, Bois - Pin
Pset_WindowCommon - IsExternal: yes

# IfcWindow: Fenêtre type 1:80 x 240 cm, Fenêtre type 1:80 x 240 cm:1340913
In: Niveau 00 - 02
Type - ParameterTakesPrecedence: no; Sizeable: no; Material: Aluminium laqué - Blanc (3), Bois - Pin
Type - Pset_QuantityTakeOff - Reference: 80 x 240 cm
Type - Pset_WindowCommon - IsExternal: no; Reference: 80 x 240 cm
OverallHeight: 2.4 m; OverallWidth: 0.8 m; Material: Aluminium laqué - Blanc, Verre, Bois - Pin
Pset_OpeningElementCommon - Reference: 80 x 240 cm; sets with these values: 2

# IfcWindow: Fenêtre type 1:90 x 60cm, Fenêtre type 1:90 x 60cm:1386851
In: Niveau 00
Type - ParameterTakesPrecedence: no; Sizeable: no; Material: Aluminium laqué - Blanc (3), Bois - Pin
Type - Pset_QuantityTakeOff - Reference: 90 x 60cm
Type - Pset_WindowCommon - IsExternal: no; Reference: 90 x 60cm
OverallHeight: 0.6 m; OverallWidth: 0.9 m; Material: Aluminium laqué - Blanc, Verre, Bois - Pin
Pset_WindowCommon - IsExternal: yes

# IfcWindow: Skydome Long:type 1, Skydome Long:type 1:1328249
In: Niveau 1 - 03
Type - ParameterTakesPrecedence: no; Sizeable: no; Material: Rubber - Wasco - Black, Aluminum - Wasco - Aged Copper, Glass - Wasco - Clear
Type - Pset_ManufacturerTypeInformation - Manufacturer: Wasco Skylights
Type - Pset_QuantityTakeOff - Reference: type 1
Type - Pset_WindowCommon - IsExternal: no; Reference: type 1
OverallHeight: 1.07179 m; OverallWidth: 10.092 m; Material: Aluminum - Wasco - Aged Copper, Glass - Wasco - Clear, Rubber - Wasco - Black

# IfcWindow: Skydome Long:type 2, Skydome Long:type 2:1328187
In: Niveau 1 - 03
Type - ParameterTakesPrecedence: no; Sizeable: no; Material: Glass - Wasco - Clear, Aluminum - Wasco - Aged Copper, Rubber - Wasco - Black
Type - Pset_ManufacturerTypeInformation - Manufacturer: Wasco Skylights
Type - Pset_QuantityTakeOff - Reference: type 2
Type - Pset_WindowCommon - IsExternal: no; Reference: type 2
OverallHeight: 1.07179 m; OverallWidth: 24.292 m; Material: Aluminum - Wasco - Aged Copper, Glass - Wasco - Clear, Rubber - Wasco - Black

# IfcStairFlightType, no part of this type: Volée monobloc:Profondeur de structure 200 mm
Pset_QuantityTakeOff - Reference: Profondeur de structure 200 mm
Pset_StairFlightCommon - Reference: Profondeur de structure 200 mm

# IfcStairFlightType, no part of this type: Volée monobloc:Profondeur de structure 200 mm
Pset_QuantityTakeOff - Reference: Profondeur de structure 200 mm
Pset_StairFlightCommon - Reference: Profondeur de structure 200 mm
